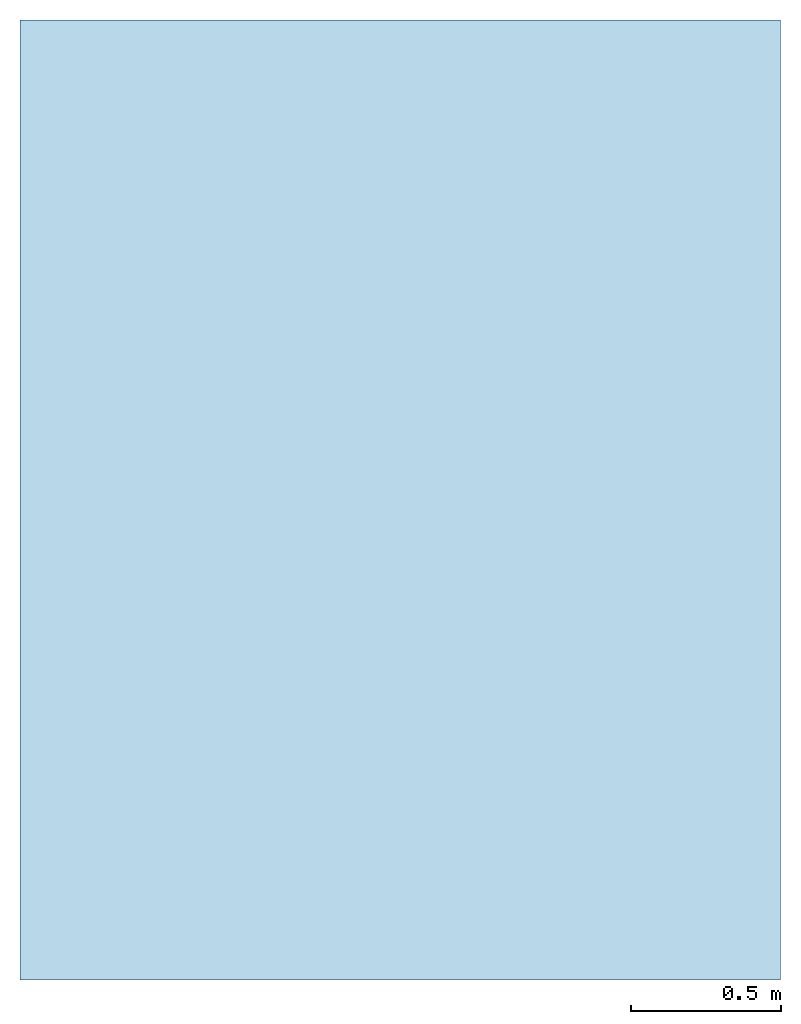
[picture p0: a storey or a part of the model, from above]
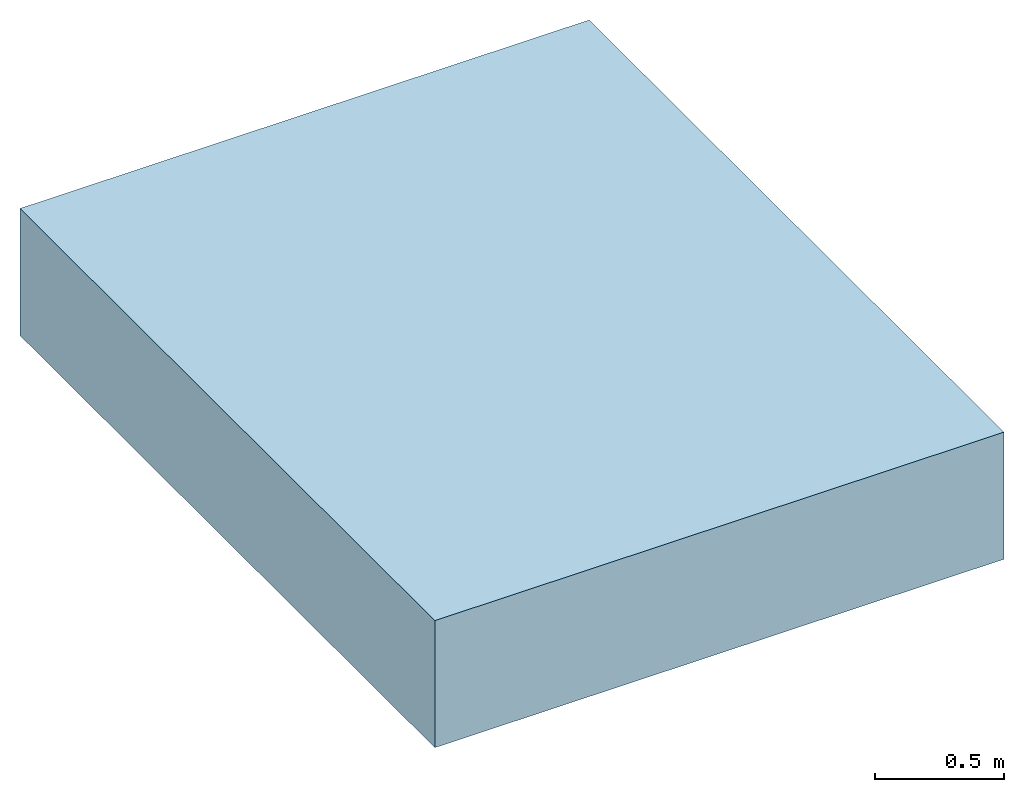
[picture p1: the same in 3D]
Properties of the parts of a building model (IFC2X3), part 1 of 4

# File
Description: ViewDefinition [CoordinationView_V2.0, SpaceBoundary2ndLevelAddOnView], Option [Drawing Scale: 100.000000], Option [Elements to export: Visible elements (on all stories)], Option [Partial Structure Display: Entire Model], Option [IFC Domain: All], Option [Structural Function: All Elements], Option [Convert Grid elements: On], Option [Convert IFC Annotations and ARCHICAD 2D elements: Off], Option [Convert 2D symbols of Doors and Windows: Off], Option [Export geometries that Participates in Collision Detection only: Off], Option [Split complex elements: On], Option [IFC Domain For Space Containment: Custom], Option [Elements in Solid Element Operations: Extruded/revolved], Option [Elements with junctions: Extruded/revolved without junctions], Option [Slabs with slanted edge(s): Extruded], Option [IFC Site Location: At Project Origin], Option [Curtain Wall export mode: Container Element], Option [Railing export mode: Container Element], Option [Stair export mode: Container Element], Option [Properties To Export: All properties], Option [Space containment: Off], Option [Bounding Box: Off], Option [Geometry to type objects: Off], Option [Element Properties: Visible Only], Option [Building Material Properties: Off], Option [Element Parameters: Off], Option [Component Parameters: Off], Option [IFC Base Quantities: Off], Option [Door Window Parameters: On], Option [IFC Space boundaries: On], Option [ARCHICAD Zone Categories as IFC Space classification data: Off], Option [Element Classifications: On]
File name: D:\Dropbox\01-L0121 Haapsalu, Paide ja Viljandi komandode ning Elva ühishoone projekteerimine\Elva ühishoone\08_KOONDMUDEL\01_IFC\AR_KUU90121E.ifc
Time: 2021-09-15T11:04:50
Author: Rohtla Juhan
Organization: Building Designer Office
Written by: The EXPRESS Data Manager Version 5.02.0100.09 : 26 Sep 2013
Made in: IFC file generated by GRAPHISOFT ARCHICAD 24.0.0 INT FULL Windows version (IFC add-on version: 3008 INT FULL).
Authorization: Rohtla Juhan

# IfcProject, ELVA ÜHISHOONE
Phase: PÕHIPROJEKT

# IfcSite, KIRDE 14, ELVA
Description: Kinnistu Kirjeldus; RefLatitude: 0, 0, 0, 0; RefLongitude: 0, 0, 0, 0; RefElevation: 0 mm; Classification: 1.0.1 IfcSite (kinnistu) (RKAS BIM + ARCHICAD Classification 24 + v 2.0)
AR_Kinnistu - 025_Max_kõrgus: 0 mm; 010_Katastritunnus: 17002:001:0035; 020_Pindala: 5119 m2; 015_Ehitatav_pindala: 1702.4 m2

# IfcBuilding, PPA ja Päästeameti ühishoone
Classification: 1.0.2 IfcBuilding (hoone) (RKAS BIM + ARCHICAD Classification 24 + v 2.0)
AR_Hoone - 035_Sprinkler: no; 040_Kõrgus: 0 mm; ?: 0 m2; 050_Neto_pindala: 0 m2; 055_Neto_ruumala: 0 m3; 001_Nimetus: PPA ja Päästreameti ühishoone; 030_Hoone_aadress: Kirde 14, Elva

# IfcBuildingStorey (5)
In: PPA ja Päästeameti ühishoone
Name | Elevation (mm)
Vundament | -1700
Esimene korrus | 0 | AR_Korrus - 060_Korruse_nimi: ESIMENE KORRUS; 065_Korruse_number: 1; 070_Maapealne: yes
Teine korrus | 3600 | AR_Korrus - 060_Korruse_nimi: TEINE KORRUS; 065_Korruse_number: 2; 070_Maapealne: yes
Katusekorrus | 7700
4. Story | 10700

# IfcSpace: 01_PPA (8)
InteriorOrExteriorSpace: INTERNAL; Classification: 1.21 IfcSpaceType (ruum) (RKAS BIM + ARCHICAD Classification)
Pset_SpaceCommon - Reference: Korruse avatud netopind; Category: 01_PPA
AR_Ruum - 115_Kategooria: 01_PPA; 110_Tüüp: Korruse avatud netopind
AC_Pset_RenovationAndPhasing - Renovation Status: Existing
Name | In | LongName = 100_Nimi | 105_Number | 120_Pindala (m2) | 125_Turvatsoon
007 | Esimene korrus | HOIURUUM | 007 | 66.6548 | PUNANE
008 | Esimene korrus | MAJAHOIDJA | 008 | 5.09534 | KOLLANE
105 | Esimene korrus | MENETLEJA | 105 | 7.96744 | SININE
106 | Esimene korrus | VESTLUSE RUUM | 106 | 8.04117 | SININE
108 | Esimene korrus | VARUSTUS | 108 | 4.1919 | PUNANE
107 | Esimene korrus | PIIRKONNA-KONSTAABLID | 107 | 26.3789 | SININE
222 | Teine korrus | PUHKERUUM+KÖÖK | 222 | 16.3328 | SININE
223 | Teine korrus | PATRULL-TEENISTUS | 223 | 20.7221 | SININE

# IfcSpace: 02_PUHAS TSOON PÄÄSTE (8)
In: Teine korrus
InteriorOrExteriorSpace: INTERNAL; Classification: 1.21 IfcSpaceType (ruum) (RKAS BIM + ARCHICAD Classification)
Pset_SpaceCommon - Reference: Korruse avatud netopind; Category: 02_PUHAS TSOON PÄÄSTE
AR_Ruum - 115_Kategooria: 02_PUHAS TSOON PÄÄSTE; 110_Tüüp: Korruse avatud netopind
AC_Pset_RenovationAndPhasing - Renovation Status: Existing
Name | LongName = 100_Nimi | 105_Number | 120_Pindala (m2) | 125_Turvatsoon
209 | WC | 209 | 1.18576 | RC3
207 | MEESKONNAVANEM | 207 | 11.2528 | ORANZ
208 | KOMANDOPEALIK | 208 | 14.178 | ORANZ
203 | PUHKETUBA | 203 | 9.59625 | ORANZ
202 | MEESKONNARUUM/KÖÖK | 202 | 64.1894 | ORANZ
204 | PUHKETUBA | 204 | 9.6 | ORANZ
205 | PUHKETUBA | 205 | 9.60045 | ORANZ
206 | PUHKETUBA | 206 | 11.0531 | ORANZ

# IfcSpace: 03_MUST TSOON PÄÄSTE (19)
In: Esimene korrus
InteriorOrExteriorSpace: INTERNAL; Classification: 1.21 IfcSpaceType (ruum) (RKAS BIM + ARCHICAD Classification)
Pset_SpaceCommon - Reference: Korruse avatud netopind; Category: 03_MUST TSOON PÄÄSTE
AR_Ruum - 115_Kategooria: 03_MUST TSOON PÄÄSTE
Name | LongName = 100_Nimi | 105_Number | 110_Tüüp | 120_Pindala (m2) | 125_Turvatsoon | Renovation Status
002 | VOOLIKUKUIVATUSTORN | 002 | Korruse avatud netopind | 8.11685 | ORANZ | New
121 | PR. HOOLDUS, HOIURUUM | 121 | Korruse avatud netopind | 42.4983 | ORANZ | Existing
004 | WC | 001 | Korruse avatud netopind | 1.7729 | ORANZ | New
119 | PUHAS LADU | 119 | Korruse avatud netopind | 23.362 | ORANZ | Existing
115 | ATV | 115 | Korruse avatud netopind | 46.0365 | ORANZ | Existing
114 | PESUBOKS | 114 | Korruse avatud netopind | 80.6371 | KOLLANE | Existing
11 | GARAAZ | 11 | Netopind | 318.751 | ORANZ | Existing
123 | TEHNIKAHOOLDUS | 123 | Korruse avatud netopind | 23.0162 | ORANZ | Existing
122 | HA. HOOLDUS | 122 | Korruse avatud netopind | 24.1263 | ORANZ | New
126 | PESURUUM/RIIETUS | 126 | Korruse avatud netopind | 14.4788 | ORANZ | Existing
116 | KORIDOR | 116 | Korruse avatud netopind | 8.95355 | KOLLANE | Existing
118 | PP.SEADE | 118 | Korruse avatud netopind | 1.87235 | KOLLANE | Existing
120 | MUST LADU | 120 | Korruse avatud netopind | 30.0442 | ORANZ | Existing
124 | KORISTUS | 124 | Korruse avatud netopind | 4.7031 | ORANZ | Existing
001 | VOOLIKUHOOLDUS | 001 | Korruse avatud netopind | 110.996 | ORANZ | New
117 | KORIDOR | 117 | Korruse avatud netopind | 2.50484 | ORANZ | New
005 | TÖÖRUUM | 005 | Korruse avatud netopind | 5.08268 | ORANZ | New
125 | WC | 125 | Korruse avatud netopind | 2.18599 | ORANZ | New
002 | VOOLIKULADU | 002 | Korruse avatud netopind | 28.539 | ORANZ | New

# IfcSpace: 04_TREPIKODA, KORIDORID, ÜLDRUUMID (9)
InteriorOrExteriorSpace: INTERNAL; Classification: 1.21 IfcSpaceType (ruum) (RKAS BIM + ARCHICAD Classification)
Pset_SpaceCommon - Category: 04_TREPIKODA, KORIDORID, ÜLDRUUMID
AR_Ruum - 115_Kategooria: 04_TREPIKODA, KORIDORID, ÜLDRUUMID
Name | In | LongName = 100_Nimi | Reference = 110_Tüüp | 105_Number | 120_Pindala (m2) | 125_Turvatsoon | Renovation Status
101 | Esimene korrus | FUAJEE, OOTERUUM | Korruse avatud netopind | 101 | 26.0202 | ROHELINE | Existing
103 | Esimene korrus | KORIDOR | Korruse avatud netopind | 103 | 12.2053 | RC3 | Existing
111 | Esimene korrus | KORIDOR | Vertikaalsete ühendusteede pind | 111 | 13.0543 | KOLLANE | Existing
100 | Esimene korrus | TK | Korruse avatud netopind | 100 | 3.10667 | ROHELINE | New
211 | Teine korrus | WC | Korruse avatud netopind | 211 | 1.40685 | KOLLANE | Existing
200 | Teine korrus | KORIDOR | Korruse avatud netopind | 200 | 47.0969 | KOLLANE | Existing
210 | Teine korrus | WC | Korruse avatud netopind | 210 | 1.40685 | KOLLANE | Existing
221 | Teine korrus | TREPIKODA | Vertikaalsete ühendusteede pind | 221 | 11.287 | KOLLANE | Existing
201 | Teine korrus | KORIDOR | Korruse avatud netopind | 200 | 3.16427 | KOLLANE | New

# IfcSpace: 04_ÜLDRUUMID (11)
InteriorOrExteriorSpace: INTERNAL; Classification: 1.21 IfcSpaceType (ruum) (RKAS BIM + ARCHICAD Classification)
Pset_SpaceCommon - Reference: Korruse avatud netopind; Category: 04_ÜLDRUUMID
AR_Ruum - 115_Kategooria: 04_ÜLDRUUMID; 110_Tüüp: Korruse avatud netopind
AC_Pset_RenovationAndPhasing - Renovation Status: Existing
Name | In | LongName = 100_Nimi | 105_Number | 120_Pindala (m2) | 125_Turvatsoon
104 | Esimene korrus | WC INVA | 104 | 6.46205 | ROHELINE
102 | Esimene korrus | ÕPPEKLASS | 102 | 64.6726 | KOLLANE
127 | Esimene korrus | TREPIKODA | 127 | 2.38765 | KOLLANE
218 | Teine korrus | WC | 218 | 1.62997 | KOLLANE
213 | Teine korrus | LEILIRUUM | 213 | 3.13597 | KOLLANE
212 | Teine korrus | RIIETUSRUUM | 212 | 57.9283 | KOLLANE
214 | Teine korrus | PESURUUM | 214 | 3.80744 | KOLLANE
215 | Teine korrus | WC | 215 | 1.90537 | KOLLANE
217 | Teine korrus | LEILIRUUM | 217 | 3.98084 | KOLLANE
216 | Teine korrus | PESURUUM | 216 | 6.3415 | KOLLANE
220 | Teine korrus | JÕUSAAL | 220 | 43.3762 | KOLLANE

# IfcSpace: 05_TEHNILISED RUUMID (8)
InteriorOrExteriorSpace: INTERNAL; Classification: 1.21 IfcSpaceType (ruum) (RKAS BIM + ARCHICAD Classification)
Pset_SpaceCommon - Category: 05_TEHNILISED RUUMID
AR_Ruum - 115_Kategooria: 05_TEHNILISED RUUMID
Name | In | LongName = 100_Nimi | Reference = 110_Tüüp | 105_Number | 120_Pindala (m2) | 125_Turvatsoon | Renovation Status
006 | Esimene korrus | GENERAATOR | Tehnopind | 006 | 16.381 | PUNANE | Existing
109 | Esimene korrus | SOOJASÕLM | Korruse avatud netopind | 109 | 5.34399 | KOLLANE | Existing
110 | Esimene korrus | KILBIRUUM | Tehnopind | 110 | 7.0841 | PUNANE | Existing
112 | Esimene korrus | KORISTUS | Korruse avatud netopind | 112 | 3.38859 | KOLLANE | Existing
224 | Teine korrus | VENTILATSIOON/KOMPRESSOR | Tehnopind | 224 | 51.1828 | KOLLANE | Existing
226 | Teine korrus | ÕVK | Tehnopind | 226 | 5.97177 | KOLLANE | Existing
226 | Teine korrus | KORISTAJA | Korruse avatud netopind | 226 | 3.3136 | KOLLANE | Existing
227 | Teine korrus | SERVER | Korruse avatud netopind | 227 | 4.10956 | PUNANE | New

# IfcSpace: 08_GARAAZ, 009
In: Esimene korrus
Type - ElementType: EXTERNAL; PredefinedType: USERDEFINED
LongName: KONTEINERITE VARJUALUNE; InteriorOrExteriorSpace: INTERNAL; Classification: External Space (RKAS BIM + ARCHICAD Classification)
Pset_SpaceCommon - Reference: Korruse avatud netopind; Category: 08_GARAAZ
AR_Ruum - 100_Nimi: KONTEINERITE VARJUALUNE; 105_Number: 009; 115_Kategooria: 08_GARAAZ; 110_Tüüp: Korruse avatud netopind; 120_Pindala: 226.204 m2; 125_Turvatsoon: ORANZ
AC_Pset_RenovationAndPhasing - Renovation Status: Existing

# IfcBeam: GENERIC - STRUCTURAL 100 x 60, LIIMPUITPRUSS
In: Esimene korrus
Type - PredefinedType: BEAM
Classification: 1.01 IfcBeamType (tala) (RKAS BIM + ARCHICAD Classification); Material: GENERIC - STRUCTURAL
Pset_BeamCommon - Reference: GENERIC - STRUCTURAL; Span: 12511 mm; Slope: 0 deg
AR_001-002 - 001_Nimetus: LIIMPUITPRUSS; 002_Tüüp: GENERIC - STRUCTURAL
AC_Pset_RenovationAndPhasing - Renovation Status: Existing

# IfcBeam: GENERIC - STRUCTURAL 160 x 50, LIIMPUITPRUSS
In: Esimene korrus
Type - PredefinedType: BEAM
Classification: 1.01 IfcBeamType (tala) (RKAS BIM + ARCHICAD Classification); Material: GENERIC - STRUCTURAL
Pset_BeamCommon - Reference: GENERIC - STRUCTURAL; Span: 1250 mm; Slope: 0 deg
AR_001-002 - 001_Nimetus: LIIMPUITPRUSS; 002_Tüüp: GENERIC - STRUCTURAL
AC_Pset_RenovationAndPhasing - Renovation Status: Existing

# IfcBeam: GENERIC - STRUCTURAL 160 x 60 (2)
In: Esimene korrus
Type - PredefinedType: BEAM
Classification: 1.01 IfcBeamType (tala) (RKAS BIM + ARCHICAD Classification); Material: GENERIC - STRUCTURAL
Pset_BeamCommon - Reference: GENERIC - STRUCTURAL; Slope: 0 deg
AR_001-002 - 001_Nimetus: LIIMPUITPRUSS; 002_Tüüp: GENERIC - STRUCTURAL
AC_Pset_RenovationAndPhasing - Renovation Status: Existing
Name | Span (mm)
LIIMPUITPRUSS | 12511
LIIMPUITPRUSS | 11211

# IfcBuildingElementPart (298)
Name | In | Material
34 x Vahtpolüstüreen (4) | Vundament | Vahtpolüstüreen (4)
10 x Concrete - Cast-in-Place Concrete - C12/15 | Vundament | Concrete - Cast-in-Place Concrete - C12/15
10 x Mineraalvill | Vundament | Mineraalvill
18 x Concrete, Cast In Situ | Vundament | Concrete, Cast In Situ
10 x Timber - Floor | Vundament | Timber - Floor
3 x Laudis | Esimene korrus | Laudis
2 x Tuulutusvahe (2) | Esimene korrus | Tuulutusvahe (2)
2 x ET-00_GENEERILINE - EHITUSTOODE | Esimene korrus | ET-00_GENEERILINE - EHITUSTOODE
2 x Profiilplekk | Esimene korrus | Profiilplekk
13 x Vahtpolüstüreen (4) | Esimene korrus | Vahtpolüstüreen (4)
2 x SBS Rullmaterjal | Esimene korrus | SBS Rullmaterjal
36 x Krohv | Esimene korrus | Krohv
13 x COLUMBIA KIVI | Esimene korrus | COLUMBIA KIVI
8 x Mineraalvill | Esimene korrus | Mineraalvill
7 x COLUMBIA KIVI (BETONEERITUD) | Esimene korrus | COLUMBIA KIVI (BETONEERITUD)
Kruus | Esimene korrus | Kruus
Liiv (2) | Esimene korrus | Liiv (2)
Betoonkivi | Esimene korrus | Betoonkivi
2 x Concrete - Cast-in-Place Concrete - C12/15 | Esimene korrus | Concrete - Cast-in-Place Concrete - C12/15
3 x Concrete, Cast In Situ | Esimene korrus | Concrete, Cast In Situ
3 x Timber - Floor | Esimene korrus | Timber - Floor
2 x  | Esimene korrus
2 x Fire Proofing | Esimene korrus | Fire Proofing
18 x Raudbetoon Paneelid (2) | Esimene korrus | Raudbetoon Paneelid (2)
Air Space | Esimene korrus | Air Space
Raudbetoon Paneelid | Esimene korrus | Raudbetoon Paneelid
7 x Laudis | Teine korrus | Laudis
Tuulutusvahe (2) | Teine korrus | Tuulutusvahe (2)
ET-00_GENEERILINE - EHITUSTOODE | Teine korrus | ET-00_GENEERILINE - EHITUSTOODE
Profiilplekk | Teine korrus | Profiilplekk
10 x Vahtpolüstüreen (4) | Teine korrus | Vahtpolüstüreen (4)
SBS Rullmaterjal | Teine korrus | SBS Rullmaterjal
5 x  | Teine korrus
5 x Fire Proofing | Teine korrus | Fire Proofing
6 x COLUMBIA KIVI (BETONEERITUD) | Teine korrus | COLUMBIA KIVI (BETONEERITUD)
18 x Air Space | Teine korrus | Air Space
18 x Raudbetoon Paneelid (2) | Teine korrus | Raudbetoon Paneelid (2)
Raudbetoon Paneelid | Teine korrus | Raudbetoon Paneelid
Mineraalvill | Teine korrus | Mineraalvill
Concrete, Cast In Situ | Teine korrus | Concrete, Cast In Situ
Timber - Floor | Teine korrus | Timber - Floor
8 x Krohv | Teine korrus | Krohv
4 x COLUMBIA KIVI | Teine korrus | COLUMBIA KIVI
2 x KON-00_GENEERILINE - KONSTRUKTSIOON | Teine korrus | KON-00_GENEERILINE - KONSTRUKTSIOON
2 x SV-00_GENEERILINE - SISEMINE VOODER | Teine korrus | SV-00_GENEERILINE - SISEMINE VOODER

# IfcBuildingElementProxy: A-SS01 260, VS-06
In: Esimene korrus
Classification: RKAS (RKAS BIM + ARCHICAD Classification)
AC_Pset_RenovationAndPhasing - Renovation Status: New

# IfcBuildingElementProxy: A-VS02 250, VS-06
In: Esimene korrus
Classification: RKAS (RKAS BIM + ARCHICAD Classification)
AC_Pset_RenovationAndPhasing - Renovation Status: New

# IfcColumn: Concrete - Structural 1300 x 400, RB post
In: Esimene korrus
Type - PredefinedType: COLUMN
Classification: 1.03 IfcColumnType (post) (RKAS BIM + ARCHICAD Classification); Material: Concrete - Structural
Pset_ColumnCommon - Slope: 0 deg; LoadBearing: yes; IsExternal: no
AR_001-002 - 001_Nimetus: RB post; 002_Tüüp: Concrete - Structural
AC_Pset_RenovationAndPhasing - Renovation Status: Existing

# IfcColumn: Concrete - Structural 1425 x 400, M_Concrete-Rectangular-Column:400 x 400mm:1416487
In: Esimene korrus
Type - PredefinedType: COLUMN
Classification: 1.03 IfcColumnType (post) (RKAS BIM + ARCHICAD Classification); Material: Concrete - Structural
Pset_ColumnCommon - Slope: 0 deg; Reference: 400 x 400mm; LoadBearing: yes; IsExternal: no
AR_001-002 - 001_Nimetus: RB post; 002_Tüüp: Concrete - Structural
AC_Pset_RenovationAndPhasing - Renovation Status: Existing

# IfcColumn: Concrete - Structural 1535 x 400, RB post
In: Esimene korrus
Type - PredefinedType: COLUMN
Classification: 1.03 IfcColumnType (post) (RKAS BIM + ARCHICAD Classification); Material: Concrete - Structural
Pset_ColumnCommon - Slope: 0 deg; LoadBearing: yes; IsExternal: no
AR_001-002 - 001_Nimetus: RB post; 002_Tüüp: Concrete - Structural
AC_Pset_RenovationAndPhasing - Renovation Status: Existing

# IfcColumn: Concrete - Structural 450 x 400 (4)
In: Esimene korrus
Type - PredefinedType: COLUMN
Classification: 1.03 IfcColumnType (post) (RKAS BIM + ARCHICAD Classification); Material: Concrete - Structural
Pset_ColumnCommon - Slope: 0 deg; LoadBearing: yes; IsExternal: no
AR_001-002 - 001_Nimetus: RB post; 002_Tüüp: Concrete - Structural
AC_Pset_RenovationAndPhasing - Renovation Status: Existing

# IfcColumn: GENERIC - STRUCTURAL 120 x 120 (2)
In: Teine korrus
Type - PredefinedType: COLUMN
Classification: 1.03 IfcColumnType (post) (RKAS BIM + ARCHICAD Classification); Material: GENERIC - STRUCTURAL
Pset_ColumnCommon - Slope: 90 deg
AR_001-002 - 001_Nimetus: TERASPOST; 002_Tüüp: GENERIC - STRUCTURAL
AC_Pset_RenovationAndPhasing - Renovation Status: New

# IfcColumn: GENERIC - STRUCTURAL 50 x 160 (19)
In: Esimene korrus
Type - PredefinedType: COLUMN
Classification: 1.03 IfcColumnType (post) (RKAS BIM + ARCHICAD Classification); Material: GENERIC - STRUCTURAL
Pset_ColumnCommon - Slope: 90 deg
AR_001-002 - 001_Nimetus: LIIMPUITPOST; 002_Tüüp: GENERIC - STRUCTURAL
AC_Pset_RenovationAndPhasing - Renovation Status: Existing

# IfcColumn: GENERIC - STRUCTURAL D140 (2)
In: Teine korrus
Type - PredefinedType: COLUMN
Classification: 1.03 IfcColumnType (post) (RKAS BIM + ARCHICAD Classification); Material: GENERIC - STRUCTURAL
Pset_ColumnCommon - Slope: 90 deg
AR_001-002 - 001_Nimetus: TORULIFT; 002_Tüüp: GENERIC - STRUCTURAL
AC_Pset_RenovationAndPhasing - Renovation Status: Existing

# IfcColumn: SBS Rullmaterjal D100 (16)
In: Esimene korrus
Type - PredefinedType: COLUMN
Classification: 1.03 IfcColumnType (post) (RKAS BIM + ARCHICAD Classification); Material: SBS Rullmaterjal
Pset_ColumnCommon - Slope: 0 deg; LoadBearing: yes; IsExternal: no
AR_001-002 - 001_Nimetus: RB post; 002_Tüüp: SBS Rullmaterjal
AC_Pset_RenovationAndPhasing - Renovation Status: New

# IfcCovering: IfcCovering (40)
In: Esimene korrus
Type - PredefinedType: FLOORING
Classification: 1.06 IfcCoveringType.FLOORING (põrandakatted) (RKAS BIM + ARCHICAD Classification); Material: SV-02_Puit - Põrand
Pset_CoveringCommon - TotalThickness: 5 mm
AR_Ripplagi_Viimistlus_Põrandakate - 215_Tulekindlusklass: Undefined; 220_Viimistlus: Undefined; 230_Niiskuskindel: no; 900_Tootja: Undefined; 905_Mudel: Undefined; 910_Tooteinfo: Undefined; 915_Kasutus-ja_hooldusjuhend: Undefined; 245_Aluspind: Undefined; 200_Materjal (MUDELIS): SV-02_Puit - Põrand
AC_Pset_RenovationAndPhasing - Renovation Status: New
Name | Reference = 205_Tüüp | AR_Ripplagi_Viimistlus_Põrandakate, 001_Nimetus = AR_001-002, 001_Nimetus | 210_Paksus (mm)
TV TÕUS - 001 | Riser | TV TÕUS - 001 | 1200
TV TÕUS - 002 | Riser | TV TÕUS - 002 | 1200
TV TÕUS - 003 | Riser | TV TÕUS - 003 | 1200
TV TÕUS - 004 | Riser | TV TÕUS - 004 | 1200
TV TÕUS - 005 | Riser | TV TÕUS - 005 | 1200
TV TÕUS - 006 | Riser | TV TÕUS - 006 | 1200
TV TÕUS - 007 | Riser | TV TÕUS - 007 | 1200
TV TÕUS - 008 | Riser | TV TÕUS - 008 | 1200
TV TÕUS - 009 | Riser | TV TÕUS - 009 | 1200
TV TÕUS - 010 | Riser | TV TÕUS - 010 | 1200
TV TÕUS - 011 | Riser | TV TÕUS - 011 | 1200
TV TÕUS - 012 | Riser | TV TÕUS - 012 | 1200
TV TÕUS - 013 | Riser | TV TÕUS - 013 | 1200
TV TÕUS - 014 | Riser | TV TÕUS - 014 | 1200
TV TÕUS - 015 | Riser | TV TÕUS - 015 | 1200
TV TÕUS - 016 | Riser | TV TÕUS - 016 | 1200
TV TÕUS - 017 | Riser | TV TÕUS - 017 | 1200
TV TÕUS - 018 | Riser | TV TÕUS - 018 | 1200
TV TÕUS - 019 | Riser | TV TÕUS - 019 | 1200
TV TÕUS - 020 | Riser | TV TÕUS - 020 | 1200
TV ASTE - 001 | Tread | TV ASTE - 001 | 5
TV ASTE - 002 | Tread | TV ASTE - 002 | 5
TV ASTE - 003 | Tread | TV ASTE - 003 | 5
TV ASTE - 004 | Tread | TV ASTE - 004 | 5
TV ASTE - 005 | Tread | TV ASTE - 005 | 5
TV ASTE - 006 | Tread | TV ASTE - 006 | 5
TV ASTE - 007 | Tread | TV ASTE - 007 | 5
TV ASTE - 008 | Tread | TV ASTE - 008 | 5
TV ASTE - 009 | Tread | TV ASTE - 009 | 5
TV ASTE - 010 | Tread | TV ASTE - 010 | 5
TV ASTE - 011 | Tread | TV ASTE - 011 | 5
TV ASTE - 012 | Tread | TV ASTE - 012 | 5
TV ASTE - 013 | Tread | TV ASTE - 013 | 5
TV ASTE - 014 | Tread | TV ASTE - 014 | 5
TV ASTE - 015 | Tread | TV ASTE - 015 | 5
TV ASTE - 016 | Tread | TV ASTE - 016 | 5
TV ASTE - 017 | Tread | TV ASTE - 017 | 5
TV ASTE - 018 | Tread | TV ASTE - 018 | 5
TV ASTE - 019 | Tread | TV ASTE - 019 | 5
TV ASTE - 020 | Tread | TV ASTE - 020 | 5

# IfcCovering: Titanium Zinc 100 (3)
In: Katusekorrus
Type - PredefinedType: CLADDING
Classification: 1.05 IfcCoveringType.CLADDING (viimistlus) (RKAS BIM + ARCHICAD Classification); Material: Titanium Zinc
Pset_CoveringCommon - Reference: Titanium Zinc; Material: Titanium Zinc; TotalThickness: 100 mm
AR_Ripplagi_Viimistlus_Põrandakate - 001_Nimetus: PARAPETIPLEKK; 200_Materjal: Titanium Zinc; 205_Tüüp: Titanium Zinc; 210_Paksus: 100 mm; 215_Tulekindlusklass: Undefined; 220_Viimistlus: Undefined; 230_Niiskuskindel: no; 900_Tootja: Undefined; 905_Mudel: Undefined; 910_Tooteinfo: Undefined; 915_Kasutus-ja_hooldusjuhend: Undefined; 240_Märghõõrdekindlus: Undefined; 245_Aluspind: Undefined; 200_Materjal (MUDELIS): Titanium Zinc
AR_001-002 - 001_Nimetus: PARAPETIPLEKK
AC_Pset_RenovationAndPhasing - Renovation Status: New
Name | 225_Pindala (m2)
PARAPETIPLEKK | 924.22
PARAPETIPLEKK | 10.4419
PARAPETIPLEKK | 247.46

# IfcDiscreteAccessory: Model Element 36 (7)
In: Katusekorrus
Description: Sewer component; Classification: 1.09 IfcDiscreteAccessoryType (tarvik) (RKAS BIM + ARCHICAD Classification); Material: IFC Building Material
AR_001-002 - 001_Nimetus: Katusetuulutus; 002_Tüüp: Model Element 36
Pset_QuantityTakeOff - Reference: Model Element 36
AC_Pset_RenovationAndPhasing - Renovation Status: Existing

# IfcDiscreteAccessory: Solar Collector Flat Plate 24 (135)
In: Katusekorrus
Description: Other pipe device; Classification: 1.09 IfcDiscreteAccessoryType (tarvik) (RKAS BIM + ARCHICAD Classification); Not defined (NS3420)
MagiCAD Pset_PipeDevice - PartType: Other pipe device; User Code: SPLIT3; RunningIndex: -; Status: Not defined; ProductCode: SPLIT3 "Panasonic WH-UX-09-DE8-1"; Manufacturer: Kaukomarkkinat; qv_SizingFlow_ls: 0.954; P_Heating_W: 12000; Storey: 3. KATUS
AR_001-002 - 001_Nimetus: Päikesepaneel; 002_Tüüp: Solar Collector Flat Plate
Pset_QuantityTakeOff - Reference: Solar Collector Flat Plate
AC_Pset_RenovationAndPhasing - Renovation Status: Existing

# IfcDiscreteAccessory: Text 3D 24 (2)
In: Teine korrus
Classification: 1.09 IfcDiscreteAccessoryType (tarvik) (RKAS BIM + ARCHICAD Classification)
Avatäited - 01 Nimetus: Katuseluuk
AR_001-002 - 001_Nimetus: HOONE SILT; 002_Tüüp: Text 3D
Pset_QuantityTakeOff - Reference: Text 3D
AC_Pset_RenovationAndPhasing - Renovation Status: Existing

# IfcDoor: Door 24, SU-06
In: Esimene korrus
Type - OperationType: SINGLE_SWING_LEFT; ParameterTakesPrecedence: no; Sizeable: no
Type - Door Lining Properties - LiningDepth: 115 mm; LiningThickness: 40 mm; LiningOffset: 190 mm
Type - Door Panel Properties - Panel 1 - PanelDepth: 40 mm; PanelOperation: SWINGING; PanelWidth: 1; PanelPosition: MIDDLE
OverallHeight: 2300 mm; OverallWidth: 900 mm; Classification: 1.10 IfcDoorStyle (uks) (RKAS BIM + ARCHICAD Classification); 522 Alumiiniumuksed (V1- EHITUSKULUDE LIIGITAMINE EVS 885:2005)
Avatäited - 10 Tulekindlus: EI-30
AR_Uks - 310_Materjal: ALUMIINIUM; 375_Viimistlus_seest: LENG JA RAAMID: PULBERVÄRVITUD, TOON: HALL, RAL 7045; 376_Viimistlus_väljast: LENG JA RAAMID: PULBERVÄRVITUD, TOON: HALL, RAL 7045; 001_Nimetus: SISEUKS; 300_Tüüp: SU-06; 305_Ava_mõõt: 900x2 300; 315_Avanemine: PAREMAKÄELINE ; ARCHICAD tüüp: Side Hung; 320_Klaas: ÜHEKORDNE KLAASPAKETT; 325_Helipidavus: UKSE HELIPIDAVUS 38 dB/ PAKETI HELIPIDAVUS 30 dB; 330_Tulekindlus: EI30; 335_Välispiire: no; 340_Soojusläbivus: 0; 345_Päikesekiirgus_tegur: Undefined; 350_Klaaspakett: KARASTATUD, LAMINEERITUD; 355_Pindala: 2.07 m2; 360_Ratastooliga: no; 365_Isesulguv: no; 370_Evakuatsiooniväljapääs: no; 380_Lukustus: UKS VARUSTADA SOLENOIDMOOTORLUKUGA (VT. NÕRKVOOLU PROJEKTI). SEESTPOOLT LIBLIKLUKUSTUSEGA, VÄLJASPOOLT VÕTMEGA LUKUSTATAV. KÄEPIDE ON ASSA RUKO-LINE, HARJATUD, ROOSTEVABA. HINGED VASTAVALT TOOTJALE. UKSESULGURINA KASUTADA UKSE VÕI LENGI SISSE SÜVISTATAVAT MUDELIT.; 900_Tootja: SCHÜCO; 905_Mudel: ADS 80 FR 30; 910_Tooteinfo: LÄHTUDA TOOTJAFIRMA INFOLEHELT; 915_Kasutus-ja_hooldusjuhend: LÄHTUDA TOOTJAFIRMA INFOLEHELT
Pset_DoorCommon - Reference: SU-06; ThermalTransmittance: 0; GlazingAreaFraction: 1.33437
AC_Pset_RenovationAndPhasing - Renovation Status: New

# IfcDoor: Door 24, SU-15
In: Esimene korrus
Type - OperationType: SINGLE_SWING_LEFT; ParameterTakesPrecedence: no; Sizeable: no
Type - Door Lining Properties - LiningThickness: 40 mm; ThresholdDepth: 100 mm; ThresholdThickness: 12 mm; LiningOffset: 0 mm; ThresholdOffset: 0 mm
Type - Door Panel Properties - Panel 1 - PanelDepth: 40 mm; PanelOperation: SWINGING; PanelWidth: 1; PanelPosition: MIDDLE
OverallHeight: 2300 mm; OverallWidth: 900 mm; Classification: 1.10 IfcDoorStyle (uks) (RKAS BIM + ARCHICAD Classification); 523 Terasuksed (V1- EHITUSKULUDE LIIGITAMINE EVS 885:2005)
Pset_ManufacturerTypeInformation - Manufacturer: SAKU METALL
AR_Uks - 310_Materjal: TERAS; 376_Viimistlus_väljast: LENG: HALL, RAL 7045, UKSELEHT: HALL, RAL 7045; 375_Viimistlus_seest: LENG: HALL, RAL 7045, UKSELEHT: HALL, RAL 7045; 001_Nimetus: SISEUKS; 300_Tüüp: SU-15; 305_Ava_mõõt: 900x2 300; 315_Avanemine: PAREMKÄE UKS ; ARCHICAD tüüp: Side Hung; 320_Klaas: -; 325_Helipidavus: -; 330_Tulekindlus: nõudeid ei esitata; 335_Välispiire: no; 340_Soojusläbivus: 0; 345_Päikesekiirgus_tegur: -; 350_Klaaspakett: -; 355_Pindala: 2.07 m2; 360_Ratastooliga: no; 365_Isesulguv: no; 370_Evakuatsiooniväljapääs: no; 380_Lukustus: SISSEPOOLE, SAN. RUUMI LIBLIKLUKUSTUS. VÄLJASPOOLT LUKUSTATAV, LUKUSTUSE ASENDI NÄITAJA. KÄEPIDE ASSA RUKOLINE, L-KUJULINE ÜMARATE KATETEGA LINK, HARJATUD, ROOSTEVABA, OTS TAGASIPÖÖRDEGA. HINGED VASTAVALT TOOTJALE.; 900_Tootja: SAKU METALL; 905_Mudel: -; 910_Tooteinfo: UKSESISENE VENTILATSIOONIREST (400x200 MM, TOON: HALL, RAL 7045). LÄHTUDA TOOTJAFIRMA INFOLEHEST; 915_Kasutus-ja_hooldusjuhend: LÄHTUDA TOOTJAFIRMA INFOLEHEST
Pset_DoorCommon - Reference: SU-15; ThermalTransmittance: 0
AC_Pset_RenovationAndPhasing - Renovation Status: New

# IfcDoor: Door 24 (2)
Type - OperationType: SINGLE_SWING_LEFT; ParameterTakesPrecedence: no; Sizeable: no
Type - Door Lining Properties - LiningThickness: 40 mm; ThresholdDepth: 100 mm; ThresholdThickness: 12 mm; LiningOffset: 0 mm; ThresholdOffset: 40 mm
Type - Door Panel Properties - Panel 1 - PanelDepth: 40 mm; PanelOperation: SWINGING; PanelWidth: 1; PanelPosition: MIDDLE
AR_Uks - 320_Klaas: -; 325_Helipidavus: -; 335_Välispiire: no; 340_Soojusläbivus: 0; 345_Päikesekiirgus_tegur: Undefined; 350_Klaaspakett: -; 360_Ratastooliga: no; 365_Isesulguv: no; 905_Mudel: -; 915_Kasutus-ja_hooldusjuhend: LÄHTUDA TOOTJAFIRMA INFOLEHEST
Pset_DoorCommon - ThermalTransmittance: 0
Pset_ManufacturerTypeInformation - Manufacturer: SAKU METALL VÕI ANALOOG
AC_Pset_RenovationAndPhasing - Renovation Status: New
Name | In | OverallHeight (mm) | OverallWidth (mm) | Classification | 310_Materjal | 376_Viimistlus_väljast | 375_Viimistlus_seest | 001_Nimetus | 300_Tüüp = Reference | 305_Ava_mõõt | 315_Avanemine | 330_Tulekindlus | 355_Pindala (m2) | 370_Evakuatsiooniväljapääs | 380_Lukustus | 900_Tootja | 910_Tooteinfo | FireRating = FireResistanceRating
SU-18* | Esimene korrus | 2300 | 900 | 1.10 IfcDoorStyle (uks) (RKAS BIM + ARCHICAD Classification); 523 Terasuksed (V1- EHITUSKULUDE LIIGITAMINE EVS 885:2005) | TERAS | LENG: HALL, RAL 7045, UKSELEHT: HALL, RAL 7045 | LENG: HALL, RAL 7045, UKSELEHT: HALL, RAL 7045 | SISEUKS | SU-18* | 900x2 300 | PAREMKÄE UKS ; ARCHICAD tüüp: Side Hung | EI30 | 2.07 | yes | VARUSTADA SOLENOIDMOOTORLUKUGA (VT. NÕRKVOOLU PROJEKTI). SISSEPOOLE LIBLIKLUKUSTUS, TREPIKOJA, KORIDORI POOLT LUKUSTAV VÕTMEGA. KÄEPIDE ASSA RUKOLINE, L-KUJULINE ÜMARATE KATETEGA LINK, HARJATUD, ROOSTEVABA, OTS TAGASIPÖÖRDEGA. HINGED VASTAVALT TOOTJALE. | SAKU METALL | LÄHTUDA TOOTJAFIRMA INFOLEHEST | EI-30 | Avatäited - 10 Tulekindlus: EI-30
SU-40 | Teine korrus | 2200 | 800 | 1.10 IfcDoorStyle (uks) (RKAS BIM + ARCHICAD Classification); 526 PVC uksed (V1- EHITUSKULUDE LIIGITAMINE EVS 885:2005) | PVC | <376_Viimistlus_väljast> | <375_Viimistlus_seest> | SISEUKS, PESURUUM | SU-40 | 800x2 200 | PAREMAKÄE UKS; ARCHICAD tüüp: Side Hung | nõudeid ei esitata | 1.76 | no | MITTELUKUSTATAV. KÄEPIDE ASSA RUKOLINE, L-KUJULINE ÜMARATE KATETEGA LINK, HARJATUD, ROOSTEVABA, OTS TAGASIPÖÖRDEGA. HINGED VASTAVALT TOOTJALE. | - | UKSESISENE VENTILATSIOONIREST (400x200 MM), TOON: UKSELEHEGA SAMASUUNE. LÄHTUDA TOOTJAFIRMA INFOLEHEST | EI-30/Sa

# IfcDoor: Door 24 (3)
In: Teine korrus
Type - OperationType: SINGLE_SWING_LEFT; ParameterTakesPrecedence: no; Sizeable: no
Type - Door Lining Properties - LiningThickness: 40 mm; ThresholdDepth: 100 mm; ThresholdThickness: 12 mm; LiningOffset: 140 mm; ThresholdOffset: 140 mm
Type - Door Panel Properties - Panel 1 - PanelDepth: 40 mm; PanelOperation: SWINGING; PanelWidth: 1; PanelPosition: MIDDLE
AR_Uks - 320_Klaas: -; 325_Helipidavus: -; 335_Välispiire: no; 340_Soojusläbivus: 0; 345_Päikesekiirgus_tegur: Undefined; 350_Klaaspakett: -; 365_Isesulguv: no; 915_Kasutus-ja_hooldusjuhend: LÄHTUDA TOOTJAFIRMA INFOLEHEST
Pset_DoorCommon - FireRating: EI-30/Sa; ThermalTransmittance: 0
Pset_FireRatingProperties - FireResistanceRating: EI-30/Sa
Pset_ManufacturerTypeInformation - Manufacturer: SAKU METALL VÕI ANALOOG
AC_Pset_RenovationAndPhasing - Renovation Status: New
Name | OverallHeight (mm) | OverallWidth (mm) | Classification | 310_Materjal | 375_Viimistlus_seest = 376_Viimistlus_väljast | 001_Nimetus | 300_Tüüp = Reference | 305_Ava_mõõt | 315_Avanemine | 330_Tulekindlus | 355_Pindala (m2) | 360_Ratastooliga | 370_Evakuatsiooniväljapääs | 380_Lukustus | 900_Tootja | 905_Mudel | 910_Tooteinfo
2 x SU-35 | 2200 | 800 | 1.10 IfcDoorStyle (uks) (RKAS BIM + ARCHICAD Classification); 525 Puituksed (V1- EHITUSKULUDE LIIGITAMINE EVS 885:2005) | PUIT | LENG: HALL, RAL 7045, UKSELEHT: KASESPOON | SU-35 | SU-35 | 800x2 200 | PAREMAKÄE UKS; ARCHICAD tüüp: Side Hung | nõudeid ei esitata | 1.76 | yes | no | VÄLJASPOOLT LUKUSTATAV JA LISADA LUKUSTUSASENDI NÄITAJA, SISSEPOOLE LIBLIKLUKUSTUS. KÄEPIDE ASSA RUKOLINE, L-KUJULINE ÜMARATE KATETEGA LINK, HARJATUD, ROOSTEVABA, OTS TAGASIPÖÖRDEGA. HINGED VASTAVALT TOOTJALE. | JELD-WEN | 40D | UKSE KOHALE VENTILATSIOONIREST. LÄHTUDA TOOTJAFIRMA INFOLEHEST
SU-23* | 2300 | 900 | 1.10 IfcDoorStyle (uks) (RKAS BIM + ARCHICAD Classification); 523 Terasuksed (V1- EHITUSKULUDE LIIGITAMINE EVS 885:2005) | TERAS | LENG: HALL, RAL 7045, UKSELEHT: HALL, RAL 7045 | SISEUKS | SU-23* | 900x2 300 | PAREMKÄE UKS ; ARCHICAD tüüp: Side Hung | EI30 | 2.07 | no | yes | VARUSTADA SOLENOIDMOOTORLUKUGA (VT. NÕRKVOOLU PROJEKTI). SISSEPOOLE LIBLIKLUKUSTUS, TREPIKOJA, KORIDORI POOLT LUKUSTAV VÕTMEGA. KÄEPIDE ASSA RUKOLINE, L-KUJULINE ÜMARATE KATETEGA LINK, HARJATUD, ROOSTEVABA, OTS TAGASIPÖÖRDEGA. HINGED VASTAVALT TOOTJALE. | SAKU METALL | - | LÄHTUDA TOOTJAFIRMA INFOLEHEST | Avatäited - 10 Tulekindlus: EI-30

# IfcDoor: Door 24, SU-34
In: Esimene korrus
Type - OperationType: SINGLE_SWING_LEFT; ParameterTakesPrecedence: no; Sizeable: no
Type - Door Lining Properties - LiningThickness: 40 mm; ThresholdDepth: 150 mm; ThresholdThickness: 12 mm; LiningOffset: 0 mm; ThresholdOffset: 0 mm
Type - Door Panel Properties - Panel 1 - PanelDepth: 40 mm; PanelOperation: SWINGING; PanelWidth: 1; PanelPosition: MIDDLE
OverallHeight: 2200 mm; OverallWidth: 1000 mm; Classification: 1.10 IfcDoorStyle (uks) (RKAS BIM + ARCHICAD Classification); 525 Puituksed (V1- EHITUSKULUDE LIIGITAMINE EVS 885:2005)
AR_Uks - 315_Avanemine: <315_Avanemine>; 310_Materjal: PUIT; 375_Viimistlus_seest: LENG: HALL, RAL 7045, UKSELEHT: KASESPOON; 376_Viimistlus_väljast: LENG: HALL, RAL 7045, UKSELEHT: KASESPOON; 001_Nimetus: SU-34; 300_Tüüp: SU-34; 305_Ava_mõõt: 1 000x2 200; 320_Klaas: -; 325_Helipidavus: -; 330_Tulekindlus: nõudeid ei esitata; 335_Välispiire: no; 340_Soojusläbivus: 0; 345_Päikesekiirgus_tegur: Undefined; 350_Klaaspakett: -; 355_Pindala: 2.2 m2; 360_Ratastooliga: yes; 365_Isesulguv: no; 370_Evakuatsiooniväljapääs: no; 380_Lukustus: VÄLJASPOOLT LUKUSTATAV JA LISADA LUKUSTUSASENDI NÄITAJA, SISSEPOOLE LIBLIKLUKUSTUS. KÄEPIDE ASSA RUKOLINE, L-KUJULINE ÜMARATE KATETEGA LINK, HARJATUD, ROOSTEVABA, OTS TAGASIPÖÖRDEGA. HINGED VASTAVALT TOOTJALE.; 900_Tootja: JELD-WEN; 905_Mudel: 40D; 910_Tooteinfo: UKSE KOHALE VENTILATSIOONIREST. LÄHTUDA TOOTJAFIRMA INFOLEHEST; 915_Kasutus-ja_hooldusjuhend: LÄHTUDA TOOTJAFIRMA INFOLEHEST
Pset_DoorCommon - Reference: SU-34; FireRating: EI-30/Sa; ThermalTransmittance: 0
Pset_FireRatingProperties - FireResistanceRating: EI-30/Sa
Pset_ManufacturerTypeInformation - Manufacturer: SAKU METALL VÕI ANALOOG
AC_Pset_RenovationAndPhasing - Renovation Status: New

# IfcDoor: Door 24 (2)
Type - OperationType: SINGLE_SWING_LEFT; ParameterTakesPrecedence: no; Sizeable: no
Type - Door Lining Properties - LiningThickness: 40 mm; ThresholdDepth: 150 mm; ThresholdThickness: 12 mm; LiningOffset: 0 mm; ThresholdOffset: 40 mm
Type - Door Panel Properties - Panel 1 - PanelDepth: 40 mm; PanelOperation: SWINGING; PanelWidth: 1; PanelPosition: MIDDLE
OverallHeight: 2200 mm
AR_Uks - 320_Klaas: -; 325_Helipidavus: -; 330_Tulekindlus: nõudeid ei esitata; 335_Välispiire: no; 340_Soojusläbivus: 0; 345_Päikesekiirgus_tegur: Undefined; 350_Klaaspakett: -; 360_Ratastooliga: no; 365_Isesulguv: no; 370_Evakuatsiooniväljapääs: no; 915_Kasutus-ja_hooldusjuhend: LÄHTUDA TOOTJAFIRMA INFOLEHEST
Pset_DoorCommon - FireRating: EI-30/Sa; ThermalTransmittance: 0
Pset_FireRatingProperties - FireResistanceRating: EI-30/Sa
Pset_ManufacturerTypeInformation - Manufacturer: SAKU METALL VÕI ANALOOG
AC_Pset_RenovationAndPhasing - Renovation Status: New
Name | In | OverallWidth (mm) | Classification | 380_Lukustus | 315_Avanemine | 310_Materjal | 375_Viimistlus_seest | 376_Viimistlus_väljast | 001_Nimetus | 300_Tüüp = Reference | 305_Ava_mõõt | 355_Pindala (m2) | 900_Tootja | 905_Mudel | 910_Tooteinfo
SU-37 | Esimene korrus | 900 | 1.10 IfcDoorStyle (uks) (RKAS BIM + ARCHICAD Classification); 525 Puituksed (V1- EHITUSKULUDE LIIGITAMINE EVS 885:2005) | VÄLJASPOOLT LUKUSTATAV, SISSEPOOLE LIBLIKLUKUSTUS. KÄEPIDE ASSA RUKOLINE, L-KUJULINE ÜMARATE KATETEGA LINK, HARJATUD, ROOSTEVABA, OTS TAGASIPÖÖRDEGA. HINGED VASTAVALT TOOTJALE. | <315_Avanemine> | PUIT | LENG: HALL, RAL 7045, UKSELEHT: KASESPOON | LENG: HALL, RAL 7045, UKSELEHT: KASESPOON | SU-37 | SU-37 | 900x2 200 | 1.98 | JELD-WEN | 40D | UKSE KOHALE VENTILATSIOONIREST. LÄHTUDA TOOTJAFIRMA INFOLEHEST
SU-40 | Teine korrus | 800 | 1.10 IfcDoorStyle (uks) (RKAS BIM + ARCHICAD Classification); 526 PVC uksed (V1- EHITUSKULUDE LIIGITAMINE EVS 885:2005) | MITTELUKUSTATAV. KÄEPIDE ASSA RUKOLINE, L-KUJULINE ÜMARATE KATETEGA LINK, HARJATUD, ROOSTEVABA, OTS TAGASIPÖÖRDEGA. HINGED VASTAVALT TOOTJALE. | PAREMAKÄE UKS; ARCHICAD tüüp: Side Hung | PVC | <375_Viimistlus_seest> | <376_Viimistlus_väljast> | SISEUKS, PESURUUM | SU-40 | 800x2 200 | 1.76 | - | - | UKSESISENE VENTILATSIOONIREST (400x200 MM), TOON: UKSELEHEGA SAMASUUNE. LÄHTUDA TOOTJAFIRMA INFOLEHEST

# IfcDoor: Door 24 (3)
In: Esimene korrus
Type - OperationType: SINGLE_SWING_LEFT; ParameterTakesPrecedence: no; Sizeable: no
Type - Door Lining Properties - LiningThickness: 40 mm; ThresholdDepth: 150 mm; ThresholdThickness: 12 mm; LiningOffset: 190 mm; ThresholdOffset: 230 mm
Type - Door Panel Properties - Panel 1 - PanelDepth: 40 mm; PanelOperation: SWINGING; PanelWidth: 1; PanelPosition: MIDDLE
OverallHeight: 2300 mm; OverallWidth: 900 mm
AR_Uks - 305_Ava_mõõt: 900x2 300; 320_Klaas: -; 325_Helipidavus: -; 335_Välispiire: no; 340_Soojusläbivus: 0; 345_Päikesekiirgus_tegur: Undefined; 350_Klaaspakett: -; 355_Pindala: 2.07 m2; 360_Ratastooliga: no; 365_Isesulguv: no; 910_Tooteinfo: LÄHTUDA TOOTJAFIRMA INFOLEHEST; 915_Kasutus-ja_hooldusjuhend: LÄHTUDA TOOTJAFIRMA INFOLEHEST
Pset_DoorCommon - ThermalTransmittance: 0
Pset_ManufacturerTypeInformation - Manufacturer: SAKU METALL VÕI ANALOOG
AC_Pset_RenovationAndPhasing - Renovation Status: New
Name | Classification | 310_Materjal | 376_Viimistlus_väljast = 375_Viimistlus_seest | 001_Nimetus | 300_Tüüp = Reference | 315_Avanemine | 330_Tulekindlus | 370_Evakuatsiooniväljapääs | 380_Lukustus | 900_Tootja | 905_Mudel | FireRating = FireResistanceRating
SU-17* | 1.10 IfcDoorStyle (uks) (RKAS BIM + ARCHICAD Classification); 523 Terasuksed (V1- EHITUSKULUDE LIIGITAMINE EVS 885:2005) | TERAS | LENG: HALL, RAL 7045, UKSELEHT: HALL, RAL 7045 | SISEUKS | SU-17* | PAREMAKÄE UKS ; ARCHICAD tüüp: Side Hung | EI30 | yes | VARUSTADA SOLENOIDMOOTORLUKUGA (VT. NÕRKVOOLU PROJEKTI). SISSEPOOLE LIBLIKLUKUSTUS, TREPIKOJA, KORIDORI POOLT LUKUSTAV VÕTMEGA. KÄEPIDE ASSA RUKOLINE, L-KUJULINE ÜMARATE KATETEGA LINK, HARJATUD, ROOSTEVABA, OTS TAGASIPÖÖRDEGA. HINGED VASTAVALT TOOTJALE. | SAKU METALL | - | EI-30 | Avatäited - 10 Tulekindlus: EI-30
SU-18* | 1.10 IfcDoorStyle (uks) (RKAS BIM + ARCHICAD Classification); 523 Terasuksed (V1- EHITUSKULUDE LIIGITAMINE EVS 885:2005) | TERAS | LENG: HALL, RAL 7045, UKSELEHT: HALL, RAL 7045 | SISEUKS | SU-18* | PAREMKÄE UKS ; ARCHICAD tüüp: Side Hung | EI30 | yes | VARUSTADA SOLENOIDMOOTORLUKUGA (VT. NÕRKVOOLU PROJEKTI). SISSEPOOLE LIBLIKLUKUSTUS, TREPIKOJA, KORIDORI POOLT LUKUSTAV VÕTMEGA. KÄEPIDE ASSA RUKOLINE, L-KUJULINE ÜMARATE KATETEGA LINK, HARJATUD, ROOSTEVABA, OTS TAGASIPÖÖRDEGA. HINGED VASTAVALT TOOTJALE. | SAKU METALL | -
SU-32 | 1.10 IfcDoorStyle (uks) (RKAS BIM + ARCHICAD Classification); 525 Puituksed (V1- EHITUSKULUDE LIIGITAMINE EVS 885:2005) | PUIT | LENG: HALL, RAL 7045, UKSELEHT: KASESPOON | SU-32 | SU-32 | <315_Avanemine> | nõudeid ei esitata | no | VÄLJASPOOLT LUKUSTATAV, SISSEPOOLE LIBLIKLUKUSTUS. KÄEPIDE ASSA RUKOLINE, L-KUJULINE ÜMARATE KATETEGA LINK, HARJATUD, ROOSTEVABA, OTS TAGASIPÖÖRDEGA. HINGED VASTAVALT TOOTJALE. | JELD-WEN | S41 | EI-30/Sa

# IfcDoor: Door 24 (2)
In: Teine korrus
Type - OperationType: SINGLE_SWING_LEFT; ParameterTakesPrecedence: no; Sizeable: no
Type - Door Lining Properties - LiningThickness: 40 mm; ThresholdDepth: 160 mm; ThresholdThickness: 12 mm; LiningOffset: 0 mm; ThresholdOffset: 40 mm
Type - Door Panel Properties - Panel 1 - PanelDepth: 40 mm; PanelOperation: SWINGING; PanelWidth: 1; PanelPosition: MIDDLE
AR_Uks - 320_Klaas: -; 325_Helipidavus: -; 330_Tulekindlus: nõudeid ei esitata; 335_Välispiire: no; 340_Soojusläbivus: 0; 345_Päikesekiirgus_tegur: Undefined; 350_Klaaspakett: -; 365_Isesulguv: no; 915_Kasutus-ja_hooldusjuhend: LÄHTUDA TOOTJAFIRMA INFOLEHEST
Pset_DoorCommon - FireRating: EI-30/Sa; ThermalTransmittance: 0
Pset_FireRatingProperties - FireResistanceRating: EI-30/Sa
Pset_ManufacturerTypeInformation - Manufacturer: SAKU METALL VÕI ANALOOG
AC_Pset_RenovationAndPhasing - Renovation Status: New
Name | OverallHeight (mm) | OverallWidth (mm) | Classification | 310_Materjal | 375_Viimistlus_seest = 376_Viimistlus_väljast | 001_Nimetus | 300_Tüüp = Reference | 305_Ava_mõõt | 315_Avanemine | 355_Pindala (m2) | 360_Ratastooliga | 370_Evakuatsiooniväljapääs | 380_Lukustus | 900_Tootja | 905_Mudel | 910_Tooteinfo
SU-19 | 2300 | 900 | 1.10 IfcDoorStyle (uks) (RKAS BIM + ARCHICAD Classification); 523 Terasuksed (V1- EHITUSKULUDE LIIGITAMINE EVS 885:2005) | TERAS | LENG: HALL, RAL 7045, UKSELEHT: HALL, RAL 7045 | SISEUKS | SU-19 | 900x2 300 | PAREMKÄE UKS ; ARCHICAD tüüp: Side Hung | 2.07 | no | yes | MITTELUKUSTATAV. KÄEPIDE ASSA RUKOLINE, L-KUJULINE ÜMARATE KATETEGA LINK, HARJATUD, ROOSTEVABA, OTS TAGASIPÖÖRDEGA. HINGED VASTAVALT TOOTJALE. | SAKU METALL | - | SOOJUSTATUD UKS. LÄHTUDA TOOTJAFIRMA INFOLEHEST | Avatäited - 10 Tulekindlus: EI-30
SU-35 | 2200 | 800 | 1.10 IfcDoorStyle (uks) (RKAS BIM + ARCHICAD Classification); 525 Puituksed (V1- EHITUSKULUDE LIIGITAMINE EVS 885:2005) | PUIT | LENG: HALL, RAL 7045, UKSELEHT: KASESPOON | SU-35 | SU-35 | 800x2 200 | PAREMAKÄE UKS; ARCHICAD tüüp: Side Hung | 1.76 | yes | no | VÄLJASPOOLT LUKUSTATAV JA LISADA LUKUSTUSASENDI NÄITAJA, SISSEPOOLE LIBLIKLUKUSTUS. KÄEPIDE ASSA RUKOLINE, L-KUJULINE ÜMARATE KATETEGA LINK, HARJATUD, ROOSTEVABA, OTS TAGASIPÖÖRDEGA. HINGED VASTAVALT TOOTJALE. | JELD-WEN | 40D | UKSE KOHALE VENTILATSIOONIREST. LÄHTUDA TOOTJAFIRMA INFOLEHEST

# IfcDoor: Door 24 (2)
In: Teine korrus
Type - OperationType: SINGLE_SWING_LEFT; ParameterTakesPrecedence: no; Sizeable: no
Type - Door Lining Properties - LiningThickness: 40 mm; ThresholdDepth: 160 mm; ThresholdThickness: 12 mm; LiningOffset: 200 mm; ThresholdOffset: 200 mm
Type - Door Panel Properties - Panel 1 - PanelDepth: 40 mm; PanelOperation: SWINGING; PanelWidth: 1; PanelPosition: MIDDLE
OverallHeight: 2300 mm; OverallWidth: 900 mm; Classification: 1.10 IfcDoorStyle (uks) (RKAS BIM + ARCHICAD Classification); 525 Puituksed (V1- EHITUSKULUDE LIIGITAMINE EVS 885:2005)
AR_Uks - 001_Nimetus: SU-33b; 300_Tüüp: SU-33b; 305_Ava_mõõt: 900x2 300; 315_Avanemine: PAREMAKÄE UKS; ARCHICAD tüüp: Side Hung; 320_Klaas: -; 325_Helipidavus: 30dB; 330_Tulekindlus: nõudeid ei esitata; 335_Välispiire: no; 340_Soojusläbivus: 0; 345_Päikesekiirgus_tegur: Undefined; 350_Klaaspakett: -; 355_Pindala: 2.07 m2; 360_Ratastooliga: no; 365_Isesulguv: no; 370_Evakuatsiooniväljapääs: no; 380_Lukustus: VÄLJASPOOLT LUKUSTATAV, SISSEPOOLE LIBLIKLUKUSTUS. KÄEPIDE ASSA RUKOLINE, L-KUJULINE ÜMARATE KATETEGA LINK, HARJATUD, ROOSTEVABA, OTS TAGASIPÖÖRDEGA. HINGED VASTAVALT TOOTJALE.; 900_Tootja: JELD-WEN; 905_Mudel: S41; 910_Tooteinfo: LÄHTUDA TOOTJAFIRMA INFOLEHEST; 915_Kasutus-ja_hooldusjuhend: LÄHTUDA TOOTJAFIRMA INFOLEHEST
Pset_DoorCommon - Reference: SU-33b; FireRating: EI-30/Sa; ThermalTransmittance: 0
Pset_FireRatingProperties - FireResistanceRating: EI-30/Sa
Pset_ManufacturerTypeInformation - Manufacturer: SAKU METALL VÕI ANALOOG
AC_Pset_RenovationAndPhasing - Renovation Status: New
Name | 310_Materjal | 375_Viimistlus_seest = 376_Viimistlus_väljast
SU-33b | PUIT | LENG: HALL, RAL 7045, UKSELEHT: KASESPOON
SU-33b | MUDELIS: väljast-PULBERVÄRVITUD, TOON: HALL, RAL 7045; KASESPOON; seest-PULBERVÄRVITUD, TOON: HALL, RAL 7045; KASESPOON; MÄRKUS: PUIT | MUDELIS: PULBERVÄRVITUD, TOON: HALL, RAL 7045; KASESPOON; MÄRKUS: LENG JA RAAMID: PULBERVÄRVITUD, TOON: HALL, RAL 7045, UKSELEHT: KASESPOON

# IfcDoor: Door 24 (2)
In: Esimene korrus
Type - OperationType: SINGLE_SWING_LEFT; ParameterTakesPrecedence: no; Sizeable: no
Type - Door Lining Properties - LiningThickness: 40 mm; ThresholdDepth: 200 mm; ThresholdThickness: 12 mm; LiningOffset: 0 mm; ThresholdOffset: 40 mm
Type - Door Panel Properties - Panel 1 - PanelDepth: 40 mm; PanelOperation: SWINGING; PanelWidth: 1; PanelPosition: MIDDLE
OverallHeight: 2300 mm; Classification: 1.10 IfcDoorStyle (uks) (RKAS BIM + ARCHICAD Classification); 523 Terasuksed (V1- EHITUSKULUDE LIIGITAMINE EVS 885:2005)
AR_Uks - 310_Materjal: TERAS; 376_Viimistlus_väljast: LENG: HALL, RAL 7045, UKSELEHT: HALL, RAL 7045; 375_Viimistlus_seest: LENG: HALL, RAL 7045, UKSELEHT: HALL, RAL 7045; 001_Nimetus: SISEUKS; 315_Avanemine: PAREMAKÄE UKS ; ARCHICAD tüüp: Side Hung; 320_Klaas: -; 325_Helipidavus: -; 335_Välispiire: no; 340_Soojusläbivus: 0; 350_Klaaspakett: -; 360_Ratastooliga: no; 365_Isesulguv: no; 900_Tootja: SAKU METALL; 905_Mudel: -; 915_Kasutus-ja_hooldusjuhend: LÄHTUDA TOOTJAFIRMA INFOLEHEST
Pset_DoorCommon - ThermalTransmittance: 0
AC_Pset_RenovationAndPhasing - Renovation Status: New
Name | OverallWidth (mm) | 300_Tüüp = Reference | 305_Ava_mõõt | 330_Tulekindlus | 345_Päikesekiirgus_tegur | 355_Pindala (m2) | 370_Evakuatsiooniväljapääs | 380_Lukustus | 910_Tooteinfo | Manufacturer
SU-17* | 900 | SU-17* | 900x2 300 | EI30 | Undefined | 2.07 | yes | VARUSTADA SOLENOIDMOOTORLUKUGA (VT. NÕRKVOOLU PROJEKTI). SISSEPOOLE LIBLIKLUKUSTUS, TREPIKOJA, KORIDORI POOLT LUKUSTAV VÕTMEGA. KÄEPIDE ASSA RUKOLINE, L-KUJULINE ÜMARATE KATETEGA LINK, HARJATUD, ROOSTEVABA, OTS TAGASIPÖÖRDEGA. HINGED VASTAVALT TOOTJALE. | LÄHTUDA TOOTJAFIRMA INFOLEHEST | SAKU METALL VÕI ANALOOG | Avatäited - 10 Tulekindlus: EI-30; Pset_DoorCommon - FireRating: EI-30; Pset_FireRatingProperties - FireResistanceRating: EI-30
SU-13 | 800 | SU-13 | 800x2 300 | nõudeid ei esitata | - | 1.84 | no | SISSEPOOLE, SAN. RUUMI LIBLIKLUKUSTUS. VÄLJASPOOLT LUKUSTATAV, LUKUSTUSE ASENDI NÄITAJA. KÄEPIDE ASSA RUKOLINE, L-KUJULINE ÜMARATE KATETEGA LINK, HARJATUD, ROOSTEVABA, OTS TAGASIPÖÖRDEGA. HINGED VASTAVALT TOOTJALE. | UKSESISENE VENTILATSIOONIREST (400x200 MM, TOON: HALL, RAL 7045). LÄHTUDA TOOTJAFIRMA INFOLEHEST | SAKU METALL

# IfcDoor: Door 24 (2)
In: Teine korrus
Type - OperationType: SINGLE_SWING_LEFT; ParameterTakesPrecedence: no; Sizeable: no
Type - Door Lining Properties - LiningThickness: 40 mm; ThresholdDepth: 257 mm; ThresholdThickness: 12 mm; LiningOffset: 297 mm; ThresholdOffset: 297 mm
Type - Door Panel Properties - Panel 1 - PanelDepth: 40 mm; PanelOperation: SWINGING; PanelWidth: 1; PanelPosition: MIDDLE
OverallHeight: 2200 mm; OverallWidth: 700 mm; Classification: 1.10 IfcDoorStyle (uks) (RKAS BIM + ARCHICAD Classification); 524 Klaasuksed (V1- EHITUSKULUDE LIIGITAMINE EVS 885:2005)
AR_Uks - 310_Materjal: PUIT; 375_Viimistlus_seest: LENG: HALL, RAL 7045, UKSELEHT: KASESPOON; 376_Viimistlus_väljast: LENG: HALL, RAL 7045, UKSELEHT: KASESPOON; 001_Nimetus: SISEUKS, LEILIRUUM; 300_Tüüp: SU-39; 305_Ava_mõõt: 700x2 200; 315_Avanemine: PAREMAKÄE UKS; ARCHICAD tüüp: Side Hung; 320_Klaas: ÜHEKORDNE KLAASIST UKSELEHT; 325_Helipidavus: -; 330_Tulekindlus: nõudeid ei esitata; 335_Välispiire: no; 340_Soojusläbivus: 0; 345_Päikesekiirgus_tegur: Undefined; 350_Klaaspakett: 8 MM, MATISTATUD KARASTATUD KLAAS; 355_Pindala: 1.54 m2; 360_Ratastooliga: no; 365_Isesulguv: no; 370_Evakuatsiooniväljapääs: no; 380_Lukustus: MITTELUKUSTATAV. PUIDUST VERTIKAALNE KÄEPIDE. HINGED VASTAVALT TOOTJALE.; 900_Tootja: JELD-WEN; 905_Mudel: SAUNA SAVU; 910_Tooteinfo: LÄHTUDA TOOTJAFIRMA INFOLEHEST; 915_Kasutus-ja_hooldusjuhend: LÄHTUDA TOOTJAFIRMA INFOLEHEST
Pset_DoorCommon - Reference: SU-39; ThermalTransmittance: 0
Pset_ManufacturerTypeInformation - Manufacturer: JELD-WEN/ SAUNA SAVU VÕI ANALOOG
AC_Pset_RenovationAndPhasing - Renovation Status: New

# IfcDoor: Door 24, SU-36
In: Teine korrus
Type - OperationType: SINGLE_SWING_RIGHT; ParameterTakesPrecedence: no; Sizeable: no
Type - Door Lining Properties - LiningThickness: 40 mm; ThresholdDepth: 100 mm; ThresholdThickness: 12 mm; LiningOffset: 0 mm; ThresholdOffset: 40 mm
Type - Door Panel Properties - Panel 1 - PanelDepth: 40 mm; PanelOperation: SWINGING; PanelWidth: 1; PanelPosition: MIDDLE
OverallHeight: 2200 mm; OverallWidth: 800 mm; Classification: 1.10 IfcDoorStyle (uks) (RKAS BIM + ARCHICAD Classification); 525 Puituksed (V1- EHITUSKULUDE LIIGITAMINE EVS 885:2005)
AR_Uks - 310_Materjal: PUIT; 375_Viimistlus_seest: LENG: HALL, RAL 7045, UKSELEHT: KASESPOON; 376_Viimistlus_väljast: LENG: HALL, RAL 7045, UKSELEHT: KASESPOON; 001_Nimetus: SU-36; 300_Tüüp: SU-36; 305_Ava_mõõt: 800x2 200; 315_Avanemine: VASAKUKÄE UKS; ARCHICAD tüüp: Side Hung; 320_Klaas: -; 325_Helipidavus: -; 330_Tulekindlus: nõudeid ei esitata; 335_Välispiire: no; 340_Soojusläbivus: 0; 345_Päikesekiirgus_tegur: Undefined; 350_Klaaspakett: -; 355_Pindala: 1.76 m2; 360_Ratastooliga: yes; 365_Isesulguv: no; 370_Evakuatsiooniväljapääs: no; 380_Lukustus: VÄLJASPOOLT LUKUSTATAV JA LISADA LUKUSTUSASENDI NÄITAJA, SISSEPOOLE LIBLIKLUKUSTUS. KÄEPIDE ASSA RUKOLINE, L-KUJULINE ÜMARATE KATETEGA LINK, HARJATUD, ROOSTEVABA, OTS TAGASIPÖÖRDEGA. HINGED VASTAVALT TOOTJALE.; 900_Tootja: JELD-WEN; 905_Mudel: 40D; 910_Tooteinfo: UKSE KOHALE VENTILATSIOONIREST. LÄHTUDA TOOTJAFIRMA INFOLEHEST; 915_Kasutus-ja_hooldusjuhend: LÄHTUDA TOOTJAFIRMA INFOLEHEST
Pset_DoorCommon - Reference: SU-36; FireRating: EI-30/Sa; ThermalTransmittance: 0
Pset_FireRatingProperties - FireResistanceRating: EI-30/Sa
Pset_ManufacturerTypeInformation - Manufacturer: SAKU METALL VÕI ANALOOG
AC_Pset_RenovationAndPhasing - Renovation Status: New

# IfcDoor: Door 24, SU-13
In: Esimene korrus
Type - OperationType: SINGLE_SWING_RIGHT; ParameterTakesPrecedence: no; Sizeable: no
Type - Door Lining Properties - LiningThickness: 40 mm; ThresholdDepth: 100 mm; ThresholdThickness: 12 mm; LiningOffset: 140 mm; ThresholdOffset: 180 mm
Type - Door Panel Properties - Panel 1 - PanelDepth: 40 mm; PanelOperation: SWINGING; PanelWidth: 1; PanelPosition: MIDDLE
OverallHeight: 2300 mm; OverallWidth: 800 mm; Classification: 1.10 IfcDoorStyle (uks) (RKAS BIM + ARCHICAD Classification); 523 Terasuksed (V1- EHITUSKULUDE LIIGITAMINE EVS 885:2005)
Pset_DoorCommon - Reference: SU-13; ThermalTransmittance: 0
AR_Uks - 001_Nimetus: SISEUKS; 300_Tüüp: SU-13; 305_Ava_mõõt: 800x2 300; 310_Materjal: MUDELIS: väljast-PULBERVÄRVITUD, TOON: HALL, RAL 7045; PULBERVÄRVITUD, TOON: HALL, RAL 7045; seest-PULBERVÄRVITUD, TOON: HALL, RAL 7045; PULBERVÄRVITUD, TOON: HALL, RAL 7045; MÄRKUS: TERAS; 315_Avanemine: PAREMAKÄE UKS ; ARCHICAD tüüp: Side Hung; 320_Klaas: -; 325_Helipidavus: -; 330_Tulekindlus: nõudeid ei esitata; 335_Välispiire: no; 340_Soojusläbivus: 0; 345_Päikesekiirgus_tegur: -; 350_Klaaspakett: -; 355_Pindala: 1.84 m2; 360_Ratastooliga: no; 365_Isesulguv: no; 370_Evakuatsiooniväljapääs: no; 375_Viimistlus_seest: MUDELIS: PULBERVÄRVITUD, TOON: HALL, RAL 7045; PULBERVÄRVITUD, TOON: HALL, RAL 7045; MÄRKUS: LENG: HALL, RAL 7045, UKSELEHT: HALL, RAL 7045; 376_Viimistlus_väljast: MUDELIS: PULBERVÄRVITUD, TOON: HALL, RAL 7045; PULBERVÄRVITUD, TOON: HALL, RAL 7045; MÄRKUS: LENG: HALL, RAL 7045, UKSELEHT: HALL, RAL 7045; 380_Lukustus: SISSEPOOLE, SAN. RUUMI LIBLIKLUKUSTUS. VÄLJASPOOLT LUKUSTATAV, LUKUSTUSE ASENDI NÄITAJA. KÄEPIDE ASSA RUKOLINE, L-KUJULINE ÜMARATE KATETEGA LINK, HARJATUD, ROOSTEVABA, OTS TAGASIPÖÖRDEGA. HINGED VASTAVALT TOOTJALE.; 900_Tootja: SAKU METALL; 905_Mudel: -; 910_Tooteinfo: UKSESISENE VENTILATSIOONIREST (400x200 MM, TOON: HALL, RAL 7045). LÄHTUDA TOOTJAFIRMA INFOLEHEST; 915_Kasutus-ja_hooldusjuhend: LÄHTUDA TOOTJAFIRMA INFOLEHEST
Pset_ManufacturerTypeInformation - Manufacturer: JELD-WEN/ 40D VÕI ANALOOG
AC_Pset_RenovationAndPhasing - Renovation Status: New

# IfcDoor: Door 24 (2)
In: Teine korrus
Type - OperationType: SINGLE_SWING_RIGHT; ParameterTakesPrecedence: no; Sizeable: no
Type - Door Lining Properties - LiningThickness: 40 mm; ThresholdDepth: 150 mm; ThresholdThickness: 12 mm; LiningOffset: 0 mm; ThresholdOffset: 0 mm
Type - Door Panel Properties - Panel 1 - PanelDepth: 40 mm; PanelOperation: SWINGING; PanelWidth: 1; PanelPosition: MIDDLE
AR_Uks - 320_Klaas: -; 325_Helipidavus: -; 335_Välispiire: no; 340_Soojusläbivus: 0; 345_Päikesekiirgus_tegur: Undefined; 350_Klaaspakett: -; 360_Ratastooliga: no; 365_Isesulguv: no; 915_Kasutus-ja_hooldusjuhend: LÄHTUDA TOOTJAFIRMA INFOLEHEST
Pset_DoorCommon - FireRating: EI-30/Sa; ThermalTransmittance: 0
Pset_FireRatingProperties - FireResistanceRating: EI-30/Sa
Pset_ManufacturerTypeInformation - Manufacturer: SAKU METALL VÕI ANALOOG
AC_Pset_RenovationAndPhasing - Renovation Status: New
Name | OverallHeight (mm) | OverallWidth (mm) | Classification | 310_Materjal | 375_Viimistlus_seest = 376_Viimistlus_väljast | 001_Nimetus | 300_Tüüp = Reference | 305_Ava_mõõt | 315_Avanemine | 330_Tulekindlus | 355_Pindala (m2) | 370_Evakuatsiooniväljapääs | 380_Lukustus | 900_Tootja | 905_Mudel | 910_Tooteinfo
SU-17*b | 2300 | 900 | 1.10 IfcDoorStyle (uks) (RKAS BIM + ARCHICAD Classification); 523 Terasuksed (V1- EHITUSKULUDE LIIGITAMINE EVS 885:2005) | TERAS | LENG: HALL, RAL 7045, UKSELEHT: HALL, RAL 7045 | SISEUKS | SU-17*b | 900x2 300 | PAREMAKÄE UKS ; ARCHICAD tüüp: Side Hung | EI30 | 2.07 | yes | VARUSTADA SOLENOIDMOOTORLUKUGA (VT. NÕRKVOOLU PROJEKTI). SISSEPOOLE LIBLIKLUKUSTUS, TREPIKOJA, KORIDORI POOLT LUKUSTAV VÕTMEGA. KÄEPIDE ASSA RUKOLINE, L-KUJULINE ÜMARATE KATETEGA LINK, HARJATUD, ROOSTEVABA, OTS TAGASIPÖÖRDEGA. HINGED VASTAVALT TOOTJALE. | SAKU METALL | - | LÄHTUDA TOOTJAFIRMA INFOLEHEST | Avatäited - 10 Tulekindlus: EI-30
SU-37b | 2200 | 800 | 1.10 IfcDoorStyle (uks) (RKAS BIM + ARCHICAD Classification); 525 Puituksed (V1- EHITUSKULUDE LIIGITAMINE EVS 885:2005) | PUIT | LENG: HALL, RAL 7045, UKSELEHT: KASESPOON | SU-37b | SU-37b | 800x2 200 | VASAKUKÄE UKS; ARCHICAD tüüp: Side Hung | nõudeid ei esitata | 1.76 | no | VÄLJASPOOLT LUKUSTATAV, SISSEPOOLE LIBLIKLUKUSTUS. KÄEPIDE ASSA RUKOLINE, L-KUJULINE ÜMARATE KATETEGA LINK, HARJATUD, ROOSTEVABA, OTS TAGASIPÖÖRDEGA. HINGED VASTAVALT TOOTJALE. | JELD-WEN | 40D | UKSE KOHALE VENTILATSIOONIREST. LÄHTUDA TOOTJAFIRMA INFOLEHEST

# IfcDoor: Door 24, SU-40
In: Teine korrus
Type - OperationType: SINGLE_SWING_RIGHT; ParameterTakesPrecedence: no; Sizeable: no
Type - Door Lining Properties - LiningThickness: 40 mm; ThresholdDepth: 150 mm; ThresholdThickness: 12 mm; LiningOffset: 0 mm; ThresholdOffset: 40 mm
Type - Door Panel Properties - Panel 1 - PanelDepth: 40 mm; PanelOperation: SWINGING; PanelWidth: 1; PanelPosition: MIDDLE
OverallHeight: 2200 mm; OverallWidth: 800 mm; Classification: 1.10 IfcDoorStyle (uks) (RKAS BIM + ARCHICAD Classification); 526 PVC uksed (V1- EHITUSKULUDE LIIGITAMINE EVS 885:2005)
AR_Uks - 360_Ratastooliga: no; 375_Viimistlus_seest: <375_Viimistlus_seest>; 376_Viimistlus_väljast: <376_Viimistlus_väljast>; 310_Materjal: PVC; 001_Nimetus: SISEUKS, PESURUUM; 300_Tüüp: SU-40; 305_Ava_mõõt: 800x2 200; 315_Avanemine: PAREMAKÄE UKS; ARCHICAD tüüp: Side Hung; 320_Klaas: -; 325_Helipidavus: -; 330_Tulekindlus: nõudeid ei esitata; 335_Välispiire: no; 340_Soojusläbivus: 0; 345_Päikesekiirgus_tegur: Undefined; 350_Klaaspakett: -; 355_Pindala: 1.76 m2; 365_Isesulguv: no; 370_Evakuatsiooniväljapääs: no; 380_Lukustus: MITTELUKUSTATAV. KÄEPIDE ASSA RUKOLINE, L-KUJULINE ÜMARATE KATETEGA LINK, HARJATUD, ROOSTEVABA, OTS TAGASIPÖÖRDEGA. HINGED VASTAVALT TOOTJALE.; 900_Tootja: -; 905_Mudel: -; 910_Tooteinfo: UKSESISENE VENTILATSIOONIREST (400x200 MM), TOON: UKSELEHEGA SAMASUUNE. LÄHTUDA TOOTJAFIRMA INFOLEHEST; 915_Kasutus-ja_hooldusjuhend: LÄHTUDA TOOTJAFIRMA INFOLEHEST
Pset_DoorCommon - Reference: SU-40; FireRating: EI-30/Sa; ThermalTransmittance: 0
Pset_FireRatingProperties - FireResistanceRating: EI-30/Sa
Pset_ManufacturerTypeInformation - Manufacturer: SAKU METALL VÕI ANALOOG
AC_Pset_RenovationAndPhasing - Renovation Status: New

# IfcDoor: Door 24, SU-14
In: Esimene korrus
Type - OperationType: SINGLE_SWING_RIGHT; ParameterTakesPrecedence: no; Sizeable: no
Type - Door Lining Properties - LiningThickness: 40 mm; ThresholdDepth: 150 mm; ThresholdThickness: 12 mm; LiningOffset: 190 mm; ThresholdOffset: 190 mm
Type - Door Panel Properties - Panel 1 - PanelDepth: 40 mm; PanelOperation: SWINGING; PanelWidth: 1; PanelPosition: MIDDLE
OverallHeight: 2300 mm; OverallWidth: 900 mm; Classification: 1.10 IfcDoorStyle (uks) (RKAS BIM + ARCHICAD Classification); 523 Terasuksed (V1- EHITUSKULUDE LIIGITAMINE EVS 885:2005)
Pset_ManufacturerTypeInformation - Manufacturer: SAKU METALL
AR_Uks - 310_Materjal: TERAS; 376_Viimistlus_väljast: LENG: HALL, RAL 7045, UKSELEHT: HALL, RAL 7045; 375_Viimistlus_seest: LENG: HALL, RAL 7045, UKSELEHT: HALL, RAL 7045; 001_Nimetus: SISEUKS; 300_Tüüp: SU-14; 305_Ava_mõõt: 900x2 300; 315_Avanemine: VASAKUKÄE UKS; ARCHICAD tüüp: Side Hung; 320_Klaas: -; 325_Helipidavus: -; 330_Tulekindlus: nõudeid ei esitata; 335_Välispiire: no; 340_Soojusläbivus: 0; 345_Päikesekiirgus_tegur: -; 350_Klaaspakett: -; 355_Pindala: 2.07 m2; 360_Ratastooliga: no; 365_Isesulguv: no; 370_Evakuatsiooniväljapääs: no; 380_Lukustus: SISSEPOOLE, SAN. RUUMI LIBLIKLUKUSTUS. VÄLJASPOOLT LUKUSTATAV, LUKUSTUSE ASENDI NÄITAJA. KÄEPIDE ASSA RUKOLINE, L-KUJULINE ÜMARATE KATETEGA LINK, HARJATUD, ROOSTEVABA, OTS TAGASIPÖÖRDEGA. HINGED VASTAVALT TOOTJALE.; 900_Tootja: SAKU METALL; 905_Mudel: -; 910_Tooteinfo: UKSESISENE VENTILATSIOONIREST (400x200 MM, TOON: HALL, RAL 7045). LÄHTUDA TOOTJAFIRMA INFOLEHEST; 915_Kasutus-ja_hooldusjuhend: LÄHTUDA TOOTJAFIRMA INFOLEHEST
Pset_DoorCommon - Reference: SU-14; ThermalTransmittance: 0
AC_Pset_RenovationAndPhasing - Renovation Status: New

# IfcDoor: Door 24, SU-15
In: Esimene korrus
Type - OperationType: SINGLE_SWING_RIGHT; ParameterTakesPrecedence: no; Sizeable: no
Type - Door Lining Properties - LiningThickness: 40 mm; ThresholdDepth: 150 mm; ThresholdThickness: 12 mm; LiningOffset: 190 mm; ThresholdOffset: 230 mm
Type - Door Panel Properties - Panel 1 - PanelDepth: 40 mm; PanelOperation: SWINGING; PanelWidth: 1; PanelPosition: MIDDLE
OverallHeight: 2300 mm; OverallWidth: 900 mm; Classification: 1.10 IfcDoorStyle (uks) (RKAS BIM + ARCHICAD Classification); 523 Terasuksed (V1- EHITUSKULUDE LIIGITAMINE EVS 885:2005)
Pset_ManufacturerTypeInformation - Manufacturer: SAKU METALL
AR_Uks - 310_Materjal: TERAS; 376_Viimistlus_väljast: LENG: HALL, RAL 7045, UKSELEHT: HALL, RAL 7045; 375_Viimistlus_seest: LENG: HALL, RAL 7045, UKSELEHT: HALL, RAL 7045; 001_Nimetus: SISEUKS; 300_Tüüp: SU-15; 305_Ava_mõõt: 900x2 300; 315_Avanemine: PAREMKÄE UKS ; ARCHICAD tüüp: Side Hung; 320_Klaas: -; 325_Helipidavus: -; 330_Tulekindlus: nõudeid ei esitata; 335_Välispiire: no; 340_Soojusläbivus: 0; 345_Päikesekiirgus_tegur: -; 350_Klaaspakett: -; 355_Pindala: 2.07 m2; 360_Ratastooliga: no; 365_Isesulguv: no; 370_Evakuatsiooniväljapääs: no; 380_Lukustus: SISSEPOOLE, SAN. RUUMI LIBLIKLUKUSTUS. VÄLJASPOOLT LUKUSTATAV, LUKUSTUSE ASENDI NÄITAJA. KÄEPIDE ASSA RUKOLINE, L-KUJULINE ÜMARATE KATETEGA LINK, HARJATUD, ROOSTEVABA, OTS TAGASIPÖÖRDEGA. HINGED VASTAVALT TOOTJALE.; 900_Tootja: SAKU METALL; 905_Mudel: -; 910_Tooteinfo: UKSESISENE VENTILATSIOONIREST (400x200 MM, TOON: HALL, RAL 7045). LÄHTUDA TOOTJAFIRMA INFOLEHEST; 915_Kasutus-ja_hooldusjuhend: LÄHTUDA TOOTJAFIRMA INFOLEHEST
Pset_DoorCommon - Reference: SU-15; ThermalTransmittance: 0
AC_Pset_RenovationAndPhasing - Renovation Status: New

# IfcDoor: Door 24 (3)
In: Teine korrus
Type - OperationType: SINGLE_SWING_RIGHT; ParameterTakesPrecedence: no; Sizeable: no
Type - Door Lining Properties - LiningThickness: 40 mm; ThresholdDepth: 160 mm; ThresholdThickness: 12 mm; LiningOffset: 200 mm; ThresholdOffset: 200 mm
Type - Door Panel Properties - Panel 1 - PanelDepth: 40 mm; PanelOperation: SWINGING; PanelWidth: 1; PanelPosition: MIDDLE
OverallHeight: 2300 mm; OverallWidth: 900 mm; Classification: 1.10 IfcDoorStyle (uks) (RKAS BIM + ARCHICAD Classification); 525 Puituksed (V1- EHITUSKULUDE LIIGITAMINE EVS 885:2005)
AR_Uks - 310_Materjal: PUIT; 375_Viimistlus_seest: LENG: HALL, RAL 7045, UKSELEHT: KASESPOON; 376_Viimistlus_väljast: LENG: HALL, RAL 7045, UKSELEHT: KASESPOON; 001_Nimetus: SU-33; 300_Tüüp: SU-33; 305_Ava_mõõt: 900x2 300; 315_Avanemine: VASAKUKÄE UKS; ARCHICAD tüüp: Side Hung; 320_Klaas: -; 325_Helipidavus: 30dB; 330_Tulekindlus: nõudeid ei esitata; 335_Välispiire: no; 340_Soojusläbivus: 0; 345_Päikesekiirgus_tegur: Undefined; 350_Klaaspakett: -; 355_Pindala: 2.07 m2; 360_Ratastooliga: no; 365_Isesulguv: no; 370_Evakuatsiooniväljapääs: no; 380_Lukustus: VÄLJASPOOLT LUKUSTATAV, SISSEPOOLE LIBLIKLUKUSTUS. KÄEPIDE ASSA RUKOLINE, L-KUJULINE ÜMARATE KATETEGA LINK, HARJATUD, ROOSTEVABA, OTS TAGASIPÖÖRDEGA. HINGED VASTAVALT TOOTJALE.; 900_Tootja: JELD-WEN; 905_Mudel: S41; 910_Tooteinfo: LÄHTUDA TOOTJAFIRMA INFOLEHEST; 915_Kasutus-ja_hooldusjuhend: LÄHTUDA TOOTJAFIRMA INFOLEHEST
Pset_DoorCommon - Reference: SU-33; FireRating: EI-30/Sa; ThermalTransmittance: 0
Pset_FireRatingProperties - FireResistanceRating: EI-30/Sa
Pset_ManufacturerTypeInformation - Manufacturer: SAKU METALL VÕI ANALOOG
AC_Pset_RenovationAndPhasing - Renovation Status: New

# IfcDoor: Door with Sidelight on Side 2 24 (4)
Type - OperationType: SINGLE_SWING_LEFT; ParameterTakesPrecedence: no; Sizeable: no
Type - Door Panel Properties - Panel 1 - PanelDepth: 40 mm; PanelOperation: SWINGING; PanelWidth: 1; PanelPosition: MIDDLE
OverallHeight: 2300 mm
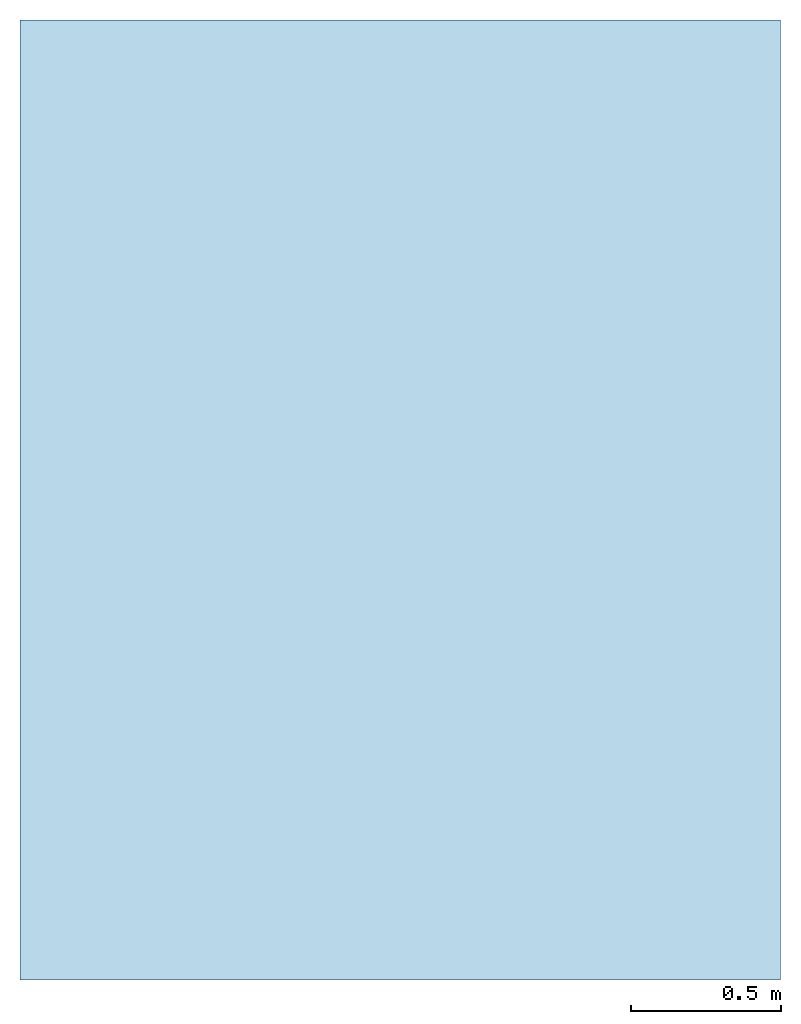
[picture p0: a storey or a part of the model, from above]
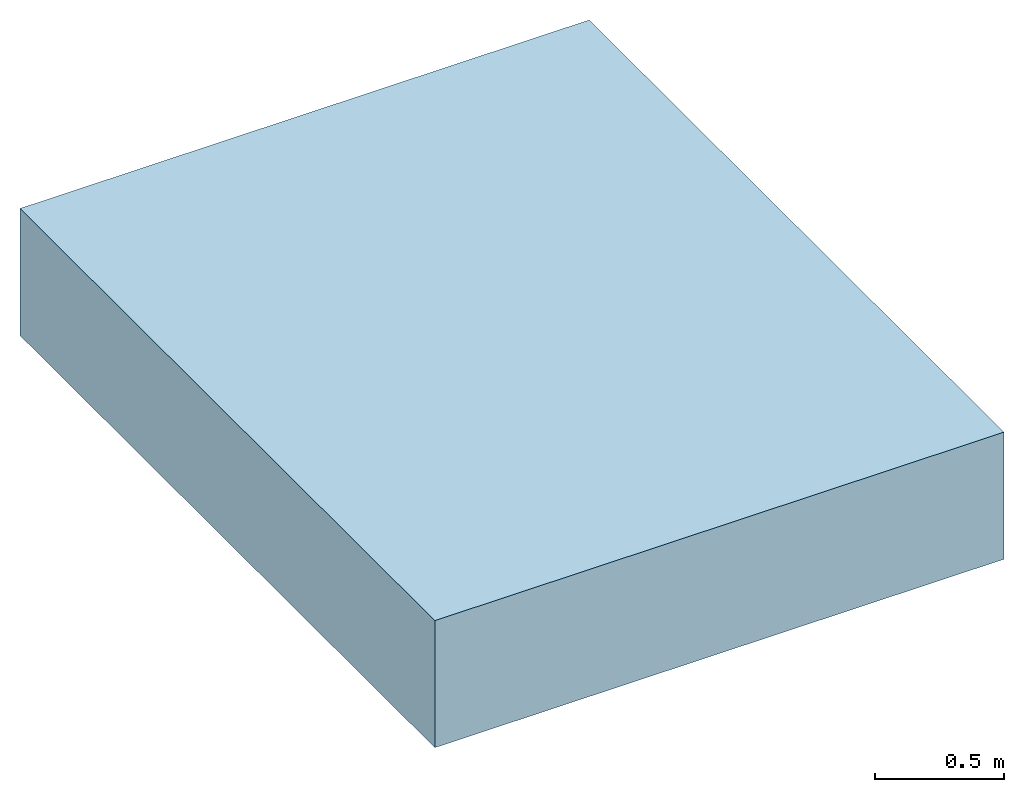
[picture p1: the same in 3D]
Properties of the parts of a building model (IFC2X3), part 2 of 4

# IfcDoor: Door with Sidelight on Side 2 24 (4)
AR_Uks - 001_Nimetus: SISEUKS; 330_Tulekindlus: nõudeid ei esitata; 335_Välispiire: no; 340_Soojusläbivus: 0; 360_Ratastooliga: yes; 910_Tooteinfo: LÄHTUDA TOOTJAFIRMA INFOLEHEST; 915_Kasutus-ja_hooldusjuhend: LÄHTUDA TOOTJAFIRMA INFOLEHEST
Pset_DoorCommon - ThermalTransmittance: 0
AC_Pset_RenovationAndPhasing - Renovation Status: New
Name | In | OverallWidth (mm) | Classification | 315_Avanemine | 310_Materjal | 375_Viimistlus_seest = 376_Viimistlus_väljast | 300_Tüüp = Reference | 305_Ava_mõõt | 320_Klaas | 325_Helipidavus | 345_Päikesekiirgus_tegur | 350_Klaaspakett | 355_Pindala (m2) | 365_Isesulguv = 370_Evakuatsiooniväljapääs | 380_Lukustus | 900_Tootja | 905_Mudel | AcousticRating | GlazingAreaFraction | Manufacturer
SU-28 | Esimene korrus | 2000 | 1.10 IfcDoorStyle (uks) (RKAS BIM + ARCHICAD Classification); 525 Puituksed (V1- EHITUSKULUDE LIIGITAMINE EVS 885:2005) | <315_Avanemine> | PUIT | LENG: HALL, RAL 7045, UKSELEHT: KASESPOON | SU-28 | 2 000x2 300 | 6+6MM, KARASTATUD KLAAS, LAMINEERITUD | 30dB | - | 2X PAKETT | 4.6 | no | SISSEPOOLE LIBLIKLUKUSTUS, VÄLJASPOOLT LUKUSTAV VÕTMEGA. KÄEPIDE ASSA RUKOLINE, L-KUJULINE ÜMARATE KATETEGA LINK, HARJATUD, ROOSTEVABA, OTS TAGASIPÖÖRATUD. HINGED VASTAVALT TOOTJALE. | JELD-WEN | S41 | 30dB | 2.2644 | JELD-WEN/ S41 VÕI ANALOOG
SU-04 | Esimene korrus | 1300 | 1.10 IfcDoorStyle (uks) (RKAS BIM + ARCHICAD Classification); 522 Alumiiniumuksed (V1- EHITUSKULUDE LIIGITAMINE EVS 885:2005) | AKTIIVNE UKSELEHT PAREMAKÄELINE ; ARCHICAD tüüp: Side Hung | ALUMIINIUM | LENG JA RAAMID: PULBERVÄRVITUD, TOON: HALL, RAL 7045 | SU-04 | 1 300x2 300 | ÜHEKORDNE PAKETT | - | Undefined | KARASTATUD KLAAS, LAMINEERITUD | 2.99 | yes | VARUSTADA SOLENOIDMOOTORLUKUGA (VT. NÕRKVOOL). MÕLEMALE POOLE AKTIIVSELE UKSELEHELE LIBLIKLUKUSTUS. KÄEPIDE ASSA RUKOLINE, L-KUJULINE ÜMARATE KATETEGA LINK, HARJATUD, ROOSTEVABA, OTS TAGASIPÖÖRDEGA. HINGED VASTAVALT TOOTJALE. UKSETÕKIS TOOTEKESKNE (UKSESULGURIS). UKSESULGUR VT LUKUSTUSPROJEKT. | SCHÜCO | AWS/ADS 50.NI |  | 2.12765 | SCHÜCO
SU-29 | Teine korrus | 2424.05 | 1.10 IfcDoorStyle (uks) (RKAS BIM + ARCHICAD Classification); 525 Puituksed (V1- EHITUSKULUDE LIIGITAMINE EVS 885:2005) | PAREMAKÄE UKS; ARCHICAD tüüp: Side Hung | PUIT | LENG: HALL, RAL 7045, UKSELEHT: KASESPOON | SU-29 | 2 424x2 300 | 6+6MM, KARASTATUD KLAAS, LAMINEERITUD | 30dB | - | 2X PAKETT | 5.57532 | no | SISSEPOOLE LIBLIKLUKUSTUS, VÄLJASPOOLT LUKUSTAV VÕTMEGA. KÄEPIDE ASSA RUKOLINE, L-KUJULINE ÜMARATE KATETEGA LINK, HARJATUD, ROOSTEVABA, OTS TAGASIPÖÖRATUD. HINGED VASTAVALT TOOTJALE. | JELD-WEN | S41 | 30dB | 3.20579 | JELD-WEN/ S41 VÕI ANALOOG
SU-29 | Teine korrus | 2434.05 | 1.10 IfcDoorStyle (uks) (RKAS BIM + ARCHICAD Classification); 525 Puituksed (V1- EHITUSKULUDE LIIGITAMINE EVS 885:2005) | PAREMAKÄE UKS; ARCHICAD tüüp: Side Hung | PUIT | LENG: HALL, RAL 7045, UKSELEHT: KASESPOON | SU-29 | 2 434x2 300 | 6+6MM, KARASTATUD KLAAS, LAMINEERITUD | 30dB | - | 2X PAKETT | 5.59832 | no | SISSEPOOLE LIBLIKLUKUSTUS, VÄLJASPOOLT LUKUSTAV VÕTMEGA. KÄEPIDE ASSA RUKOLINE, L-KUJULINE ÜMARATE KATETEGA LINK, HARJATUD, ROOSTEVABA, OTS TAGASIPÖÖRATUD. HINGED VASTAVALT TOOTJALE. | JELD-WEN | S41 | 30dB | 3.22799 | JELD-WEN/ S41 VÕI ANALOOG

# IfcDoor: Door with Sidelight on Side 2 24 (6)
Type - OperationType: SINGLE_SWING_RIGHT; ParameterTakesPrecedence: no; Sizeable: no
Type - Door Panel Properties - Panel 1 - PanelDepth: 40 mm; PanelOperation: SWINGING; PanelWidth: 1; PanelPosition: MIDDLE
OverallHeight: 2300 mm
AR_Uks - 001_Nimetus: SISEUKS; 330_Tulekindlus: nõudeid ei esitata; 335_Välispiire: no; 340_Soojusläbivus: 0; 910_Tooteinfo: LÄHTUDA TOOTJAFIRMA INFOLEHEST; 915_Kasutus-ja_hooldusjuhend: LÄHTUDA TOOTJAFIRMA INFOLEHEST
Pset_DoorCommon - ThermalTransmittance: 0
AC_Pset_RenovationAndPhasing - Renovation Status: New
Name | In | OverallWidth (mm) | Classification | 315_Avanemine | 310_Materjal | 375_Viimistlus_seest = 376_Viimistlus_väljast | 300_Tüüp = Reference | 305_Ava_mõõt | 320_Klaas | 325_Helipidavus | 345_Päikesekiirgus_tegur | 350_Klaaspakett | 355_Pindala (m2) | 360_Ratastooliga | 365_Isesulguv | 370_Evakuatsiooniväljapääs | 380_Lukustus | 900_Tootja | 905_Mudel | GlazingAreaFraction | Manufacturer
2 x SU-27 | Esimene korrus | 1500 | 1.10 IfcDoorStyle (uks) (RKAS BIM + ARCHICAD Classification); 525 Puituksed (V1- EHITUSKULUDE LIIGITAMINE EVS 885:2005) | <315_Avanemine> | PUIT | LENG: HALL, RAL 7045, UKSELEHT: KASESPOON | SU-27 | 1 500x2 300 | 6+6MM, KARASTATUD KLAAS, LAMINEERITUD | 30dB | - | 2X PAKETT | 3.45 | yes | no | no | SISSEPOOLE LIBLIKLUKUSTUS, VÄLJASPOOLT LUKUSTAV VÕTMEGA. KÄEPIDE ASSA RUKOLINE, L-KUJULINE ÜMARATE KATETEGA LINK, HARJATUD, ROOSTEVABA, OTS TAGASIPÖÖRATUD. HINGED VASTAVALT TOOTJALE. | JELD-WEN | S41 | 1.1544 | JELD-WEN/ S41 VÕI ANALOOG | Pset_DoorCommon - AcousticRating: 30dB
SU-05 | Esimene korrus | 1200 | 1.10 IfcDoorStyle (uks) (RKAS BIM + ARCHICAD Classification); 522 Alumiiniumuksed (V1- EHITUSKULUDE LIIGITAMINE EVS 885:2005) | <315_Avanemine> | ALUMIINIUM | LENG JA RAAMID: PULBERVÄRVITUD, TOON: HALL, RAL 7045 | SU-05 | 1 200x2 300 | ÜHEKORDNE PAKETT | - | Undefined | KARASTATUD KLAAS, LAMINEERITUD | 2.76 | yes | yes | yes | MITTELUKUSTATAV. KÄEPIDE ON DIAMANTEK OLD SF 2200 MM, HARJATUD, ROOSTEVABA. UKSETÕKIS TOOTEKESKNE (UKSESULGURIS). UKSESULGUR VT LUKUSTUSPROJEKT. HINGED VASTAVALT TOOTJALE. | SCHÜCO | AWS/ADS 50.NI | 1.90565 | SCHÜCO
SU-31 | Teine korrus | 1300 | 1.10 IfcDoorStyle (uks) (RKAS BIM + ARCHICAD Classification); 525 Puituksed (V1- EHITUSKULUDE LIIGITAMINE EVS 885:2005) | VASAKUKÄE UKS; ARCHICAD tüüp: Side Hung | PUIT | LENG: HALL, RAL 7045, UKSELEHT: KASESPOON | SU-31 | 1 300x2 300 | 2X PAKETT | - | Undefined | 6+6MM, KARASTATUD KLAAS, LAMINEERITUD | 2.99 | no | no | yes | VARUSTADA SOLENOIDMOOTORLUKUGA (VT. NÕRKVOOL). MÕLEMALE POOLE AKTIIVSELE UKSELEHELE LIBLIKLUKUSTUS. KÄEPIDE ASSA RUKOLINE, L-KUJULINE ÜMARATE KATETEGA LINK, HARJATUD, ROOSTEVABA, OTS TAGASIPÖÖRDEGA. HINGED VASTAVALT TOOTJALE. UKSETÕKIS TOOTEKESKNE (UKSESULGURIS). UKSESULGUR VT LUKUSTUSPROJEKT. | JELD-WEN | 40D | 2.12765 | JELD-WEN/ 40D VÕI ANALOOG
SU-07 | Teine korrus | 1300 | 1.10 IfcDoorStyle (uks) (RKAS BIM + ARCHICAD Classification); 522 Alumiiniumuksed (V1- EHITUSKULUDE LIIGITAMINE EVS 885:2005) | AKTIIVNE UKSELEHT PAREMAKÄELINE ; ARCHICAD tüüp: Side Hung | ALUMIINIUM | LENG JA RAAMID: PULBERVÄRVITUD, TOON: HALL, RAL 7045 | SU-07 | 1 300x2 300 | ÜHEKORDNE PAKETT | - | Undefined | KARASTATUD KLAAS, LAMINEERITUD | 2.99 | no | no | yes | MITTELUKUSTATAV. KÄEPIDE ON ASSA RUKOLINE, L-KUJULINE ÜMARATE KATETEGA LINK, HARJATUD, ROOSTEVABA, OTS TAGASIPÖÖRATUD. HINGED VASTAVALT TOOTJALE (SCHÜCO). UKSETÕKIS TOOTEKESKNE (UKSESULGURIS). UKSESULGUR VT LUKUSTUSPROJEKT. | SCHÜCO | AWS/ADS 50.NI | 2.12765
SU-08 | Teine korrus | 1300 | 1.10 IfcDoorStyle (uks) (RKAS BIM + ARCHICAD Classification); 522 Alumiiniumuksed (V1- EHITUSKULUDE LIIGITAMINE EVS 885:2005) | VASAKUKÄE UKS; ARCHICAD tüüp: Side Hung | ALUMIINIUM | LENG JA RAAMID: PULBERVÄRVITUD, TOON: HALL, RAL 7045 | SU-08 | 1 300x2 300 | ÜHEKORDNE PAKETT | - | Undefined | KARASTATUD KLAAS, LAMINEERITUD | 2.99 | no | no | yes | VARUSTADA SOLENOIDMOOTORLUKUGA (VT. NÕRKVOOL). MÕLEMALE POOLE AKTIIVSELE UKSELEHELE LIBLIKLUKUSTUS. KÄEPIDE ASSA RUKOLINE, L-KUJULINE ÜMARATE KATETEGA LINK, HARJATUD, ROOSTEVABA, OTS TAGASIPÖÖRDEGA. HINGED VASTAVALT TOOTJALE. UKSETÕKIS TOOTEKESKNE (UKSESULGURIS). UKSESULGUR VT LUKUSTUSPROJEKT. | SCHÜCO | AWS/ADS 50.NI | 2.12765

# IfcDoor: Door with Sidelight on Side 2 and Transom 24, VU-02
In: Esimene korrus
Type - OperationType: SINGLE_SWING_RIGHT; ParameterTakesPrecedence: no; Sizeable: no
Type - Door Panel Properties - Panel 1 - PanelDepth: 40 mm; PanelOperation: SWINGING; PanelWidth: 1; PanelPosition: MIDDLE
OverallHeight: 2800 mm; OverallWidth: 1200 mm; Classification: 1.10 IfcDoorStyle (uks) (RKAS BIM + ARCHICAD Classification); 432 Alumiiniumuksed ja -väravad (V1- EHITUSKULUDE LIIGITAMINE EVS 885:2005)
Avatäited - 06 Soojusläbivus: U≤1,0 W/m²K
AR_Uks - 300_Tüüp: VU-02; 001_Nimetus: VÄLISUKS; 310_Materjal: ALUMIINIUM; 375_Viimistlus_seest: PULBERVÄRVITUD, TUMEHALL, RAL 7016; 376_Viimistlus_väljast: PULBERVÄRVITUD, TUMEHALL, RAL 7016; 305_Ava_mõõt: 1 200x2 800; 315_Avanemine: Väljapoole, vasak ; ARCHICAD tüüp: Side Hung; 320_Klaas: 2X KLAASPAKETT, PAKETI VAHELIISTU TOON: TUMEHALL, RAL 7016; 325_Helipidavus: 30dB; 330_Tulekindlus: EI30; 335_Välispiire: yes; 340_Soojusläbivus: 0; 345_Päikesekiirgus_tegur: g=0,38, VALGUSE LÄBIPAISTVUS 63%; 350_Klaaspakett: 2K SUNGUARD 6KarSel+16CF-14RST; 355_Pindala: 3.36 m2; 360_Ratastooliga: yes; 365_Isesulguv: yes; 370_Evakuatsiooniväljapääs: yes; 380_Lukustus: VARUSTADA MOOTORELEKTRILUKUGA (VT. NÕRKVOOLU PROJEKTI). VÄLJASPOOLT LUKUSTAV VÕTMEGA. SISSEPOOLE AKTIIVSELE UKSELEHELE LIBLIKLUKUSTUS, PASSIIVSELE SERVARIIV. LUKUKORPUS VASTAVALT LUKUSTUSPROJEKTILE. KÕIK LUKUD PEAVAD OLEMA SARJASTATAVAD. KÄEPIDE ON DIAMANTEK OLD SF 2200 MM, HARJATUD, ROOSTEVABA. LISADA RAAMISISENE ASENDIANDUR.; 900_Tootja: SCHÜCO; 905_Mudel: ADS 80 FR 30; 910_Tooteinfo: LÄHTUDA TOOTJAFIRMA INFOLEHEST; 915_Kasutus-ja_hooldusjuhend: LÄHTUDA TOOTJAFIRMA INFOLEHEST. TURVAMÄRGISTUS 1500MM KÕRGUSEL.
Pset_DoorCommon - Reference: VU-02; ThermalTransmittance: 0; GlazingAreaFraction: 2.34381; IsExternal: yes
AC_Pset_RenovationAndPhasing - Renovation Status: New

# IfcDoor: Door with Transom 24 (2)
In: Esimene korrus
Type - OperationType: SINGLE_SWING_LEFT; ParameterTakesPrecedence: no; Sizeable: no
Type - Door Lining Properties - LiningDepth: 115 mm; LiningThickness: 40 mm; TransomThickness: 40 mm; TransomOffset: 2300 mm; LiningOffset: 0 mm
Type - Door Panel Properties - Panel 1 - PanelDepth: 40 mm; PanelOperation: SWINGING; PanelWidth: 1; PanelPosition: MIDDLE
OverallHeight: 2800 mm; OverallWidth: 900 mm; Classification: 1.10 IfcDoorStyle (uks) (RKAS BIM + ARCHICAD Classification); 432 Alumiiniumuksed ja -väravad (V1- EHITUSKULUDE LIIGITAMINE EVS 885:2005)
Avatäited - 06 Soojusläbivus: U≤1,0 W/m²K
AR_Uks - 310_Materjal: TERAS; 375_Viimistlus_seest: PULBERVÄRVITUD, TUMEHALL, RAL 7016; 376_Viimistlus_väljast: PULBERVÄRVITUD, TUMEHALL, RAL 7016; 001_Nimetus: VÄLISUKS; 300_Tüüp: VU-03; 305_Ava_mõõt: 900x2 800; 315_Avanemine: Väljapoole, parem ; ARCHICAD tüüp: Side Hung; 320_Klaas: -; 325_Helipidavus: 30dB; 330_Tulekindlus: nõudeid ei esitata; 335_Välispiire: yes; 340_Soojusläbivus: 0; 345_Päikesekiirgus_tegur: -; 350_Klaaspakett: -; 355_Pindala: 2.52 m2; 360_Ratastooliga: yes; 365_Isesulguv: yes; 370_Evakuatsiooniväljapääs: no; 380_Lukustus: VARUSTADA MOOTORELEKTRILUKUGA (VT. NÕRKVOOLU PROJEKTI). MÕLEMALTPOOLT LUKUSTATAV VÕTMEGA. LUKUKORPUS VASTAVALT LUKUSTUSPROJEKTILE. KÕIK LUKUD PEAVAD OLEMA SARJASTATAVAD. KÄEPIDE ASSA RUKOLINE, L-KUJULINE ÜMARATE KATETEGA LINK, HARJATUD, ROOSTEVABA, ÄRAPÖÖRATUD OTSAGA. LISADA RAAMISISENE ASENDIANDUR.; 900_Tootja: SAKU METALL; 905_Mudel: -; 910_Tooteinfo: LÄHTUDA TOOTJAFIRMA INFOLEHEST; 915_Kasutus-ja_hooldusjuhend: LÄHTUDA TOOTJAFIRMA INFOLEHEST
Pset_DoorCommon - Reference: VU-03; ThermalTransmittance: 0; GlazingAreaFraction: 0.3444; IsExternal: yes
AC_Pset_RenovationAndPhasing - Renovation Status: New

# IfcDoor: Door with Transom 24, VU-03
In: Esimene korrus
Type - OperationType: SINGLE_SWING_RIGHT; ParameterTakesPrecedence: no; Sizeable: no
Type - Door Lining Properties - LiningDepth: 115 mm; LiningThickness: 40 mm; TransomThickness: 40 mm; TransomOffset: 2300 mm; LiningOffset: 250 mm
Type - Door Panel Properties - Panel 1 - PanelDepth: 40 mm; PanelOperation: SWINGING; PanelWidth: 1; PanelPosition: MIDDLE
OverallHeight: 2800 mm; OverallWidth: 900 mm; Classification: 1.10 IfcDoorStyle (uks) (RKAS BIM + ARCHICAD Classification); 432 Alumiiniumuksed ja -väravad (V1- EHITUSKULUDE LIIGITAMINE EVS 885:2005)
Avatäited - 06 Soojusläbivus: U≤1,0 W/m²K
AR_Uks - 310_Materjal: TERAS; 375_Viimistlus_seest: PULBERVÄRVITUD, TUMEHALL, RAL 7016; 376_Viimistlus_väljast: PULBERVÄRVITUD, TUMEHALL, RAL 7016; 001_Nimetus: VÄLISUKS; 300_Tüüp: VU-03; 305_Ava_mõõt: 900x2 800; 315_Avanemine: Väljapoole, parem ; ARCHICAD tüüp: Side Hung; 320_Klaas: -; 325_Helipidavus: 30dB; 330_Tulekindlus: nõudeid ei esitata; 335_Välispiire: yes; 340_Soojusläbivus: 0; 345_Päikesekiirgus_tegur: -; 350_Klaaspakett: -; 355_Pindala: 2.52 m2; 360_Ratastooliga: yes; 365_Isesulguv: yes; 370_Evakuatsiooniväljapääs: no; 380_Lukustus: VARUSTADA MOOTORELEKTRILUKUGA (VT. NÕRKVOOLU PROJEKTI). MÕLEMALTPOOLT LUKUSTATAV VÕTMEGA. LUKUKORPUS VASTAVALT LUKUSTUSPROJEKTILE. KÕIK LUKUD PEAVAD OLEMA SARJASTATAVAD. KÄEPIDE ASSA RUKOLINE, L-KUJULINE ÜMARATE KATETEGA LINK, HARJATUD, ROOSTEVABA, ÄRAPÖÖRATUD OTSAGA. LISADA RAAMISISENE ASENDIANDUR.; 900_Tootja: SAKU METALL; 905_Mudel: -; 910_Tooteinfo: LÄHTUDA TOOTJAFIRMA INFOLEHEST; 915_Kasutus-ja_hooldusjuhend: LÄHTUDA TOOTJAFIRMA INFOLEHEST
Pset_DoorCommon - Reference: VU-03; ThermalTransmittance: 0; GlazingAreaFraction: 0.3444; IsExternal: yes
AC_Pset_RenovationAndPhasing - Renovation Status: New

# IfcDoor: Door with Transom 24, VU-03
In: Esimene korrus
Type - OperationType: SINGLE_SWING_RIGHT; ParameterTakesPrecedence: no; Sizeable: no
Type - Door Lining Properties - LiningDepth: 115 mm; LiningThickness: 40 mm; TransomThickness: 40 mm; TransomOffset: 2300 mm; LiningOffset: 350 mm
Type - Door Panel Properties - Panel 1 - PanelDepth: 40 mm; PanelOperation: SWINGING; PanelWidth: 1; PanelPosition: MIDDLE
OverallHeight: 4200 mm; OverallWidth: 900 mm; Classification: 1.10 IfcDoorStyle (uks) (RKAS BIM + ARCHICAD Classification); 432 Alumiiniumuksed ja -väravad (V1- EHITUSKULUDE LIIGITAMINE EVS 885:2005)
Pset_DoorCommon - Reference: VU-03; ThermalTransmittance: 0; GlazingAreaFraction: 1.4924; IsExternal: yes
AR_Uks - 001_Nimetus: VÄLISUKS; 300_Tüüp: VU-03; 305_Ava_mõõt: 900x4 200; 310_Materjal: MUDELIS: väljast-PULBERVÄRVITUD, TOON: TUMEHALL, RAL 7016; PULBERVÄRVITUD, TOON: TUMEHALL, RAL 7016; seest-PULBERVÄRVITUD, TOON: TUMEHALL, RAL 7016; PULBERVÄRVITUD, TOON: TUMEHALL, RAL 7016; MÄRKUS: TERAS; 315_Avanemine: Väljapoole, parem ; ARCHICAD tüüp: Side Hung; 320_Klaas: -; 325_Helipidavus: 30dB; 330_Tulekindlus: nõudeid ei esitata; 335_Välispiire: yes; 340_Soojusläbivus: 0; 345_Päikesekiirgus_tegur: -; 350_Klaaspakett: -; 355_Pindala: 3.78 m2; 360_Ratastooliga: yes; 365_Isesulguv: yes; 370_Evakuatsiooniväljapääs: no; 375_Viimistlus_seest: MUDELIS: PULBERVÄRVITUD, TOON: TUMEHALL, RAL 7016; PULBERVÄRVITUD, TOON: TUMEHALL, RAL 7016; MÄRKUS: PULBERVÄRVITUD, TOON: TUMEHALL, RAL 7016; 376_Viimistlus_väljast: MUDELIS: PULBERVÄRVITUD, TOON: TUMEHALL, RAL 7016; PULBERVÄRVITUD, TOON: TUMEHALL, RAL 7016; MÄRKUS: PULBERVÄRVITUD, TOON: TUMEHALL, RAL 7016; 380_Lukustus: VARUSTADA MOOTORELEKTRILUKUGA (VT. NÕRKVOOLU PROJEKTI). MÕLEMALTPOOLT LUKUSTATAV VÕTMEGA. LUKUKORPUS VASTAVALT LUKUSTUSPROJEKTILE. KÕIK LUKUD PEAVAD OLEMA SARJASTATAVAD. KÄEPIDE ASSA RUKOLINE, L-KUJULINE ÜMARATE KATETEGA LINK, HARJATUD, ROOSTEVABA, ÄRAPÖÖRATUD OTSAGA. LISADA RAAMISISENE ASENDIANDUR.; 900_Tootja: SAKU METALL; 905_Mudel: -; 910_Tooteinfo: LÄHTUDA TOOTJAFIRMA INFOLEHEST; 915_Kasutus-ja_hooldusjuhend: LÄHTUDA TOOTJAFIRMA INFOLEHEST
AC_Pset_RenovationAndPhasing - Renovation Status: New

# IfcDoor: Doors-Industrial_ASSA-ABLOY-OH1042F-overhead-sectional-door (7)
In: Esimene korrus
Type - ParameterTakesPrecedence: no; Sizeable: no
OverallWidth: 4000 mm; Classification: 1.10 IfcDoorStyle (uks) (RKAS BIM + ARCHICAD Classification); 432 Alumiiniumuksed ja -väravad (V1- EHITUSKULUDE LIIGITAMINE EVS 885:2005)
AR_Uks - 365_Isesulguv: no; 001_Nimetus: GARAAŽIUKS; 310_Materjal: ALUMIINIUM; 315_Avanemine: MOOTORIGA AVATAV JA SULETAV; 320_Klaas: 3x, KARASTATUD, LAMINEERITUD; 325_Helipidavus: 30dB; 330_Tulekindlus: nõudeid ei esitata; 335_Välispiire: yes; 340_Soojusläbivus: 2.2; 360_Ratastooliga: no; 900_Tootja: ASSA-ABLOY; 905_Mudel: OH1042F; 910_Tooteinfo: VASTAVALT TOOTJAFIRMA INFOLEHELE
Pset_DoorCommon - IsExternal: yes
AC_Pset_RenovationAndPhasing - Renovation Status: New
Name | OverallHeight (mm) | 370_Evakuatsiooniväljapääs | 300_Tüüp = Reference | 376_Viimistlus_väljast | 375_Viimistlus_seest | 305_Ava_mõõt | 345_Päikesekiirgus_tegur | 350_Klaaspakett | 355_Pindala (m2) | 380_Lukustus | 915_Kasutus-ja_hooldusjuhend
GU-03 | 2800 | yes | GU-03 | <376_Viimistlus_väljast> | <375_Viimistlus_seest> | 4 000x2 800 | g=0,55; VALGUSE LÄBIPAISTVUS 70% | 6 MM SELEKTIIV + 4 + 6 MM SELEKTIIV / 14mm ChrU | 11.2 | AJAM, MIS VÕIMALDAB UKSELEHE TÕSTE 2,8 M KÕRGUSENI 21 SEKUNDIGA. LUKUSTUS INNER RANGE SEERIA. KÄIGUTEEUKS VARUSTADA SOLENOIDMOOTORLUKUGA (VT. NÕRKVOOLU PROJEKTI). SISSEPOOLE LIBLIKLUKUSTUS, VÄLJASPOOLT LUKUSTATAV VÕTMEGA. KÄEPIDE ON ASSA RUKO-LINE, HARJATUD, ROOSTEVABA. HINGED VASTAVALT TOOTJALE, OTS TAGASIPÖÖRDEGA . KÄIGUTEE UKSETÕKIS TOOTEKESKNE. VARUSTADA | VASTAVALT TOOTJAFIRMA INFOLEHELE. 1-VT. JOONISEID AR-7-07, AR-7-08, AR-7-15 2-IGA VÄRAV KOMPLEKTEERITUD KAHE KAASASKANTAVA PULDIGA (ÜKS MASINAS, TEINE KOMANDOPEALIKU KÄES). SAMAST PULDIST PEAB OLEMA VÕIMALIK GARAAŽI VALVE ALLA PANNA. GARAAŽIUSTE PULT PEAB AVAMA MÕLEMA PIIRDEAIA VÄRAVAD JA VÕIMALDAMA HOONE VALVESTAMIST. 3- LISAKS VÄRAVA AVAMISEKS-SULGEMISEKS STATSIONAARNE LÜLITI GARAAZIVÄRAVA KÕRVAL SEINAL. 4- KÕIKI VÄRAVAID PEAB OLEMA VÕIMALIK VABASTADA AJAMI VEOSÜSTEEMIST JA AVADA-SULGEDA KÄSITSI. PEAB OLEMA KIIRESTI JA ILMA LISAVAHENDITETA KÄSITSI AVATAV. 5- VÄLJAKUTSELE REAGEERIVA PÄÄSTETEHNIKA GARAAŽIVÄRAVATE AVANEMISKIIRUS MINIMAALSELT 21 CM SEKUNDIGA. 6- PESUBOKSI JA REMONDIBOKSI VÄRAVAAJAM PEAB OLEMA VEEJOAKINDEL (IP 65). 7- IGALE VÄRAVALE PAIGALDADA KAHE SIGNAALTULEGA (PUNANE JA ROHELINE) FOOR. ROHELINE SÜTTIB ALLES VÄRAVA TÄIELIKUL AVANEMISEL. FOORI ASUKOHT PEAB OLEMA HÄSTI JÄLGITAV OPERATIIVSÕIDUKI JUHI KOHALT. 8- ARVESTADA ÖÖPÄEVARINGSEKS UKSETSÜKLITE ARVUKS VÄHEMALT 50 9- VÄRAVATEL PEAB OLEMA TURVALISUST TAGAV ÜLESLÜKKAMISKAITSE 10- KÕIGIL PAIGALDATAVATEL VÄRAVATEL ON NÕUTAV TOOTJAPOOLNE ÖÖPÄEVARINGNE TEHNILINE TUGI 11-GARAAŽIUKSES KÄÄNDUKS AVANEB VÄLJAPOOLE
4 x GU-01 | 4400 | no | GU-01 | PULBERVÄRVITUD, TUMEHALL, RAL 7016 | PULBERVÄRVITUD, TUMEHALL, RAL 7016 | 4 000x4 400 | g=0,38, VALGUSE LÄBIPAISTVUS 63% | 6MM SUNGUARD SN70/37 + 4 + 6MM SELEKTIIV / 14MM CHRU | 17.6 | AJAM, MIS VÕIMALDAB UKSELEHE TÕSTE 4,4M KÕRGUSENI 21 SEKUNDIGA. LUKUSTUS INNER RANGE SEERIA. | VASTAVALT TOOTJAFIRMA INFOLEHELE. 1-VT. JOONISEID AR-7-07, AR-7-08, AR-7-15 2-IGA VÄRAV KOMPLEKTEERITUD KAHE KAASASKANTAVA PULDIGA (ÜKS MASINAS, TEINE KOMANDOPEALIKU KÄES). SAMAST PULDIST PEAB OLEMA VÕIMALIK GARAAŽI VALVE ALLA PANNA. GARAAŽIUSTE PULT PEAB AVAMA MÕLEMA PIIRDEAIA VÄRAVAD JA VÕIMALDAMA HOONE VALVESTAMIST. 3- LISAKS VÄRAVA AVAMISEKS-SULGEMISEKS STATSIONAARNE LÜLITI GARAAZIVÄRAVA KÕRVAL SEINAL. 4- KÕIKI VÄRAVAID PEAB OLEMA VÕIMALIK VABASTADA AJAMI VEOSÜSTEEMIST JA AVADA-SULGEDA KÄSITSI. PEAB OLEMA KIIRESTI JA ILMA LISAVAHENDITETA KÄSITSI AVATAV. 5- VÄLJAKUTSELE REAGEERIVA PÄÄSTETEHNIKA GARAAŽIVÄRAVATE AVANEMISKIIRUS MINIMAALSELT 21 CM SEKUNDIGA. 6- PESUBOKSI JA REMONDIBOKSI VÄRAVAAJAM PEAB OLEMA VEEJOAKINDEL (IP 65). 7- IGALE VÄRAVALE PAIGALDADA KAHE SIGNAALTULEGA (PUNANE JA ROHELINE) FOOR. ROHELINE SÜTTIB ALLES VÄRAVA TÄIELIKUL AVANEMISEL. FOORI ASUKOHT PEAB OLEMA HÄSTI JÄLGITAV OPERATIIVSÕIDUKI JUHI KOHALT. 8- ARVESTADA ÖÖPÄEVARINGSEKS UKSETSÜKLITE ARVUKS VÄHEMALT 50 9- VÄRAVATEL PEAB OLEMA TURVALISUST TAGAV ÜLESLÜKKAMISKAITSE 10- KÕIGIL PAIGALDATAVATEL VÄRAVATEL ON NÕUTAV TOOTJAPOOLNE ÖÖPÄEVARINGNE TEHNILINE TUGI.
2 x GU-02 | 4400 | yes | GU-02 | PULBERVÄRVITUD, TUMEHALL, RAL 7016 | PULBERVÄRVITUD, TUMEHALL, RAL 7016 | 4 000x4 400 | g=0,38, VALGUSE LÄBIPAISTVUS 63% | 6MM SUNGUARD SN70/37 + 4 + 6MM SELEKTIIV / 14MM CHRU | 17.6 | AJAM, MIS VÕIMALDAB UKSELEHE TÕSTE 4,4M KÕRGUSENI 21 SEKUNDIGA. LUKUSTUS INNER RANGE SEERIA. KÄIGUTEEUKS VARUSTADA SOLENOIDMOOTORLUKUGA (VT. NÕRKVOOLU PROJEKTI). SISSEPOOLE LIBLIKLUKUSTUS, VÄLJASPOOLT LUKUSTATAV VÕTMEGA. KÄEPIDE ON ASSA RUKO-LINE, HARJATUD, ROOSTEVABA. HINGED VASTAVALT TOOTJALE, OTS TAGASIPÖÖRDEGA . KÄIGUTEE UKSETÕKIS TOOTEKESKNE. VARUSTADA KAABLIÜLEVIIGUGA . | VASTAVALT TOOTJAFIRMA INFOLEHELE. 1-VT. JOONISEID AR-7-07, AR-7-08, AR-7-15 2-IGA VÄRAV KOMPLEKTEERITUD KAHE KAASASKANTAVA PULDIGA (ÜKS MASINAS, TEINE KOMANDOPEALIKU KÄES). SAMAST PULDIST PEAB OLEMA VÕIMALIK GARAAŽI VALVE ALLA PANNA. GARAAŽIUSTE PULT PEAB AVAMA MÕLEMA PIIRDEAIA VÄRAVAD JA VÕIMALDAMA HOONE VALVESTAMIST. 3- LISAKS VÄRAVA AVAMISEKS-SULGEMISEKS STATSIONAARNE LÜLITI GARAAZIVÄRAVA KÕRVAL SEINAL. 4- KÕIKI VÄRAVAID PEAB OLEMA VÕIMALIK VABASTADA AJAMI VEOSÜSTEEMIST JA AVADA-SULGEDA KÄSITSI. PEAB OLEMA KIIRESTI JA ILMA LISAVAHENDITETA KÄSITSI AVATAV. 5- VÄLJAKUTSELE REAGEERIVA PÄÄSTETEHNIKA GARAAŽIVÄRAVATE AVANEMISKIIRUS MINIMAALSELT 21 CM SEKUNDIGA. 6- PESUBOKSI JA REMONDIBOKSI VÄRAVAAJAM PEAB OLEMA VEEJOAKINDEL (IP 65). 7- IGALE VÄRAVALE PAIGALDADA KAHE SIGNAALTULEGA (PUNANE JA ROHELINE) FOOR. ROHELINE SÜTTIB ALLES VÄRAVA TÄIELIKUL AVANEMISEL. FOORI ASUKOHT PEAB OLEMA HÄSTI JÄLGITAV OPERATIIVSÕIDUKI JUHI KOHALT. 8- ARVESTADA ÖÖPÄEVARINGSEKS UKSETSÜKLITE ARVUKS VÄHEMALT 50 9- VÄRAVATEL PEAB OLEMA TURVALISUST TAGAV ÜLESLÜKKAMISKAITSE 10- KÕIGIL PAIGALDATAVATEL VÄRAVATEL ON NÕUTAV TOOTJAPOOLNE ÖÖPÄEVARINGNE TEHNILINE TUGI 11-GARAAŽIUKSES KÄÄNDUKS AVANEB VÄLJAPOOLE

# IfcDoor: Double Door 24, SU-25
In: Teine korrus
Type - OperationType: DOUBLE_DOOR_SINGLE_SWING; ParameterTakesPrecedence: no; Sizeable: no
Type - Door Lining Properties - LiningDepth: 115 mm; LiningThickness: 40 mm; LiningOffset: 190 mm
Type - Door Panel Properties - Panel 1 - PanelDepth: 40 mm; PanelOperation: SWINGING; PanelWidth: 0.512371; PanelPosition: RIGHT
Type - Door Panel Properties - Panel 2 - PanelDepth: 40 mm; PanelOperation: SWINGING; PanelWidth: 0.512371; PanelPosition: LEFT
OverallHeight: 2300 mm; OverallWidth: 1050 mm; Classification: 1.10 IfcDoorStyle (uks) (RKAS BIM + ARCHICAD Classification); 523 Terasuksed (V1- EHITUSKULUDE LIIGITAMINE EVS 885:2005)
AR_Uks - 310_Materjal: TERAS; 375_Viimistlus_seest: LENG: HALL, RAL 7045, UKSELEHT: HALL, RAL 7045; 376_Viimistlus_väljast: LENG: HALL, RAL 7045, UKSELEHT: HALL, RAL 7045; 001_Nimetus: SISEUKS; 300_Tüüp: SU-25; 305_Ava_mõõt: 1 050x2 300; 315_Avanemine: -; ARCHICAD tüüp: Side Hung; 320_Klaas: -; 325_Helipidavus: -; 330_Tulekindlus: nõudeid ei esitata; 335_Välispiire: no; 340_Soojusläbivus: 0; 345_Päikesekiirgus_tegur: Undefined; 350_Klaaspakett: -; 355_Pindala: 2.415 m2; 360_Ratastooliga: no; 365_Isesulguv: no; 370_Evakuatsiooniväljapääs: no; 380_Lukustus: MITTELUKUSTATAV, MAGNETFIKSAATORITEGA. HINGED VASTAVALT TOOTJALE. UKSESULGURINA KASUTADA UKSE VÕI LENGI SISSE SÜVISTATAVAT MUDELIT; 900_Tootja: SAKU METALL; 905_Mudel: -; 910_Tooteinfo: LÄHTUDA TOOTJAFIRMA INFOLEHEST; 915_Kasutus-ja_hooldusjuhend: LÄHTUDA TOOTJAFIRMA INFOLEHEST
Pset_DoorCommon - Reference: SU-25; ThermalTransmittance: 0
AC_Pset_RenovationAndPhasing - Renovation Status: New

# IfcDoor: Double Door 24, SU-25
In: Teine korrus
Type - OperationType: DOUBLE_DOOR_SINGLE_SWING; ParameterTakesPrecedence: no; Sizeable: no
Type - Door Lining Properties - LiningDepth: 115 mm; LiningThickness: 40 mm; LiningOffset: 240 mm
Type - Door Panel Properties - Panel 1 - PanelDepth: 40 mm; PanelOperation: SWINGING; PanelWidth: 0.512371; PanelPosition: RIGHT
Type - Door Panel Properties - Panel 2 - PanelDepth: 40 mm; PanelOperation: SWINGING; PanelWidth: 0.512371; PanelPosition: LEFT
OverallHeight: 2300 mm; OverallWidth: 1050 mm; Classification: 1.10 IfcDoorStyle (uks) (RKAS BIM + ARCHICAD Classification); 523 Terasuksed (V1- EHITUSKULUDE LIIGITAMINE EVS 885:2005)
AR_Uks - 310_Materjal: TERAS; 375_Viimistlus_seest: LENG: HALL, RAL 7045, UKSELEHT: HALL, RAL 7045; 376_Viimistlus_väljast: LENG: HALL, RAL 7045, UKSELEHT: HALL, RAL 7045; 001_Nimetus: SISEUKS; 300_Tüüp: SU-25; 305_Ava_mõõt: 1 050x2 300; 315_Avanemine: -; ARCHICAD tüüp: Side Hung; 320_Klaas: -; 325_Helipidavus: -; 330_Tulekindlus: nõudeid ei esitata; 335_Välispiire: no; 340_Soojusläbivus: 0; 345_Päikesekiirgus_tegur: Undefined; 350_Klaaspakett: -; 355_Pindala: 2.415 m2; 360_Ratastooliga: no; 365_Isesulguv: no; 370_Evakuatsiooniväljapääs: no; 380_Lukustus: MITTELUKUSTATAV, MAGNETFIKSAATORITEGA. HINGED VASTAVALT TOOTJALE. UKSESULGURINA KASUTADA UKSE VÕI LENGI SISSE SÜVISTATAVAT MUDELIT; 900_Tootja: SAKU METALL; 905_Mudel: -; 910_Tooteinfo: LÄHTUDA TOOTJAFIRMA INFOLEHEST; 915_Kasutus-ja_hooldusjuhend: LÄHTUDA TOOTJAFIRMA INFOLEHEST
Pset_DoorCommon - Reference: SU-25; ThermalTransmittance: 0
AC_Pset_RenovationAndPhasing - Renovation Status: New

# IfcDoor: Double Door 24, SU-01
In: Esimene korrus
Type - OperationType: DOUBLE_DOOR_SINGLE_SWING; ParameterTakesPrecedence: no; Sizeable: no
Type - Door Lining Properties - LiningDepth: 115 mm; LiningThickness: 40 mm; ThresholdDepth: 75 mm; ThresholdThickness: 12 mm; LiningOffset: 0 mm; ThresholdOffset: 40 mm
Type - Door Panel Properties - Panel 1 - PanelDepth: 40 mm; PanelOperation: SWINGING; PanelWidth: 0.506977; PanelPosition: RIGHT
Type - Door Panel Properties - Panel 2 - PanelDepth: 40 mm; PanelOperation: SWINGING; PanelWidth: 0.506977; PanelPosition: LEFT
OverallHeight: 2300 mm; OverallWidth: 1800 mm; Classification: 1.10 IfcDoorStyle (uks) (RKAS BIM + ARCHICAD Classification); 522 Alumiiniumuksed (V1- EHITUSKULUDE LIIGITAMINE EVS 885:2005)
Pset_ManufacturerTypeInformation - Manufacturer: SCHÜCO
AR_Uks - 365_Isesulguv: yes; 310_Materjal: ALUMIINIUM; 315_Avanemine: VÄLJAPOOLE AVANEV, AKTIIVNE UKSELEHT PAREMAKÄELINE; 375_Viimistlus_seest: LENG JA RAAMID: PULBERVÄRVITUD, TOON: HALL, RAL 7045; 376_Viimistlus_väljast: LENG JA RAAMID: PULBERVÄRVITUD, TOON: HALL, RAL 7045; 001_Nimetus: SISEMINE TUULEKOJA UKS; 300_Tüüp: SU-01; 305_Ava_mõõt: 1 800x2 300; 320_Klaas: ÜHEKORDNE PAKETT; 325_Helipidavus: -; 330_Tulekindlus: nõudeid ei esitata; 335_Välispiire: no; 340_Soojusläbivus: 0; 345_Päikesekiirgus_tegur: -; 350_Klaaspakett: KARASTATUD KLAAS, LAMINEERITUD; 355_Pindala: 4.14 m2; 360_Ratastooliga: yes; 370_Evakuatsiooniväljapääs: yes; 380_Lukustus: AKTIIVNE UKSELEHT MITTELUKUSTATAV, PASSIIVSELE SERVARIIV. KÄEPIDE DIAMANTEK OLD SF 2200 MM, HARJATUD, ROOSTEVABA. HINGED VASTAVALT TOOTJALE. UKSETÕKIS TOOTEKESKNE (UKSESULGURIS). UKSESULGUR MÕLEMAL UKSELEHEL VT LUKUSTUSPROJEKT; 900_Tootja: SCHÜCO; 905_Mudel: AWS/ADS 50.NI; 910_Tooteinfo: LÄHTUDA TOOTJAFIRMA INFOLEHEST; 915_Kasutus-ja_hooldusjuhend: LÄHTUDA TOOTJAFIRMA INFOLEHEST
Pset_DoorCommon - Reference: SU-01; ThermalTransmittance: 0; GlazingAreaFraction: 2.78477; IsExternal: no
AC_Pset_RenovationAndPhasing - Renovation Status: New

# IfcDoor: Double Door 24, SU-02*
In: Esimene korrus
Type - OperationType: DOUBLE_DOOR_SINGLE_SWING; ParameterTakesPrecedence: no; Sizeable: no
Type - Door Lining Properties - LiningDepth: 115 mm; LiningThickness: 40 mm; ThresholdDepth: 75 mm; ThresholdThickness: 12 mm; LiningOffset: 190 mm; ThresholdOffset: 230 mm
Type - Door Panel Properties - Panel 1 - PanelDepth: 40 mm; PanelOperation: SWINGING; PanelWidth: 0.506977; PanelPosition: RIGHT
Type - Door Panel Properties - Panel 2 - PanelDepth: 40 mm; PanelOperation: SWINGING; PanelWidth: 0.506977; PanelPosition: LEFT
OverallHeight: 2300 mm; OverallWidth: 1800 mm; Classification: 1.10 IfcDoorStyle (uks) (RKAS BIM + ARCHICAD Classification); 522 Alumiiniumuksed (V1- EHITUSKULUDE LIIGITAMINE EVS 885:2005)
AR_Uks - 315_Avanemine: VÄLJAPOOLE AVANEV, AKTIIVNE UKSELEHT PAREMAKÄELINE; 310_Materjal: ALUMIINIUM; 375_Viimistlus_seest: LENG JA RAAMID: PULBERVÄRVITUD, TOON: HALL, RAL 7045; 376_Viimistlus_väljast: LENG JA RAAMID: PULBERVÄRVITUD, TOON: HALL, RAL 7045; 001_Nimetus: SISEUKS; 300_Tüüp: SU-02*; 305_Ava_mõõt: 1 800x2 300; 320_Klaas: ÜHEKORDNE PAKETT; 325_Helipidavus: -; 330_Tulekindlus: EI30; 335_Välispiire: no; 340_Soojusläbivus: 0; 345_Päikesekiirgus_tegur: Undefined; 350_Klaaspakett: KARASTATUD KLAAS, LAMINEERITUD; 355_Pindala: 4.14 m2; 360_Ratastooliga: yes; 365_Isesulguv: no; 370_Evakuatsiooniväljapääs: yes; 380_Lukustus: VARUSTADA SOLENOIDMOOTORLUKUGA (VT. NÕRKVOOLU PROJEKTI). SISSEPOOLE (GARAAŽI POOLE) LIBLIKLUKUSTUS, VÄLJASPOOLT LUKUSTATAV VÕTMEGA, PASSIIVSELE UKSELEHELE SERVARIIV. KÄEPIDE ASSA RUKOLINE, L-KUJULINE ÜMARATE KATETEGA LINK, HARJATUD, ROOSTEVABA, OTS TAGASIPÖÖRDEGA. HINGED VASTAVALT TOOTJALE.; 900_Tootja: SCHÜCO; 905_Mudel: ADS 80 FR 30; 910_Tooteinfo: LÄHTUDA TOOTJAFIRMA INFOLEHEST; 915_Kasutus-ja_hooldusjuhend: LÄHTUDA TOOTJAFIRMA INFOLEHEST
Pset_ManufacturerTypeInformation - Manufacturer: SCHÜCO
Pset_FireRatingProperties - FireResistanceRating: EI-30
Pset_DoorCommon - FireRating: EI-30; Reference: SU-02*; ThermalTransmittance: 0; GlazingAreaFraction: 2.78477; IsExternal: no
AC_Pset_RenovationAndPhasing - Renovation Status: New

# IfcDoor: Double Door 24, SU-22*
In: Teine korrus
Type - OperationType: DOUBLE_DOOR_SINGLE_SWING; ParameterTakesPrecedence: no; Sizeable: no
Type - Door Lining Properties - LiningThickness: 40 mm; ThresholdDepth: 100 mm; ThresholdThickness: 12 mm; LiningOffset: 0 mm; ThresholdOffset: 40 mm
Type - Door Panel Properties - Panel 1 - PanelDepth: 40 mm; PanelOperation: SWINGING; PanelWidth: 0.796721; PanelPosition: LEFT
Type - Door Panel Properties - Panel 2 - PanelDepth: 40 mm; PanelOperation: SWINGING; PanelWidth: 0.222951; PanelPosition: RIGHT
OverallHeight: 2300 mm; OverallWidth: 1300 mm; Classification: 1.10 IfcDoorStyle (uks) (RKAS BIM + ARCHICAD Classification); 523 Terasuksed (V1- EHITUSKULUDE LIIGITAMINE EVS 885:2005)
AR_Uks - 310_Materjal: TERAS; 375_Viimistlus_seest: LENG: HALL, RAL 7045, UKSELEHT: HALL, RAL 7045; 376_Viimistlus_väljast: LENG: HALL, RAL 7045, UKSELEHT: HALL, RAL 7045; 001_Nimetus: SISEUKS; 300_Tüüp: SU-22*; 305_Ava_mõõt: 1 300x2 300; 315_Avanemine: Undefined - Vasak ; ARCHICAD tüüp: Side Hung; 320_Klaas: -; 325_Helipidavus: -; 330_Tulekindlus: EI30; 335_Välispiire: no; 340_Soojusläbivus: 0; 345_Päikesekiirgus_tegur: Undefined; 350_Klaaspakett: -; 355_Pindala: 2.99 m2; 360_Ratastooliga: no; 365_Isesulguv: no; 370_Evakuatsiooniväljapääs: yes; 380_Lukustus: VARUSTADA SOLENOIDMOOTORLUKUGA (VT. NÕRKVOOLU PROJEKTI). SISSEPOOLE LIBLIKLUKUSTUS, TREPIKOJA, KORIDORI POOLT LUKUSTAV VÕTMEGA. KÄEPIDE ASSA RUKOLINE, L-KUJULINE ÜMARATE KATETEGA LINK, HARJATUD, ROOSTEVABA, OTS TAGASIPÖÖRDEGA. HINGED VASTAVALT TOOTJALE.; 900_Tootja: SAKU METALL; 905_Mudel: -; 910_Tooteinfo: LÄHTUDA TOOTJAFIRMA INFOLEHEST; 915_Kasutus-ja_hooldusjuhend: LÄHTUDA TOOTJAFIRMA INFOLEHEST
Pset_DoorCommon - Reference: SU-22*; FireRating: EI-30/Sa; ThermalTransmittance: 0
Pset_FireRatingProperties - FireResistanceRating: EI-30/Sa
Pset_ManufacturerTypeInformation - Manufacturer: SAKU METALL VÕI ANALOOG
AC_Pset_RenovationAndPhasing - Renovation Status: New

# IfcDoor: Double Door 24, SU-21*
In: Teine korrus
Type - OperationType: DOUBLE_DOOR_SINGLE_SWING; ParameterTakesPrecedence: no; Sizeable: no
Type - Door Lining Properties - LiningThickness: 40 mm; ThresholdDepth: 100 mm; ThresholdThickness: 12 mm; LiningOffset: 140 mm; ThresholdOffset: 180 mm
Type - Door Panel Properties - Panel 1 - PanelDepth: 40 mm; PanelOperation: SWINGING; PanelWidth: 0.796721; PanelPosition: RIGHT
Type - Door Panel Properties - Panel 2 - PanelDepth: 40 mm; PanelOperation: SWINGING; PanelWidth: 0.222951; PanelPosition: LEFT
OverallHeight: 2300 mm; OverallWidth: 1300 mm; Classification: 1.10 IfcDoorStyle (uks) (RKAS BIM + ARCHICAD Classification); 523 Terasuksed (V1- EHITUSKULUDE LIIGITAMINE EVS 885:2005)
AR_Uks - 310_Materjal: TERAS; 375_Viimistlus_seest: LENG: HALL, RAL 7045, UKSELEHT: HALL, RAL 7045; 376_Viimistlus_väljast: LENG: HALL, RAL 7045, UKSELEHT: HALL, RAL 7045; 001_Nimetus: SISEUKS; 300_Tüüp: SU-21*; 305_Ava_mõõt: 1 300x2 300; 315_Avanemine: PAREMKÄE UKS ; ARCHICAD tüüp: Side Hung; 320_Klaas: -; 325_Helipidavus: -; 330_Tulekindlus: EI30; 335_Välispiire: no; 340_Soojusläbivus: 0; 345_Päikesekiirgus_tegur: Undefined; 350_Klaaspakett: -; 355_Pindala: 2.99 m2; 360_Ratastooliga: no; 365_Isesulguv: no; 370_Evakuatsiooniväljapääs: yes; 380_Lukustus: VARUSTADA SOLENOIDMOOTORLUKUGA (VT. NÕRKVOOLU PROJEKTI). SISSEPOOLE LIBLIKLUKUSTUS, TREPIKOJA, KORIDORI POOLT LUKUSTAV VÕTMEGA. KÄEPIDE ASSA RUKOLINE, L-KUJULINE ÜMARATE KATETEGA LINK, HARJATUD, ROOSTEVABA, OTS TAGASIPÖÖRDEGA. HINGED VASTAVALT TOOTJALE.; 900_Tootja: SAKU METALL; 905_Mudel: -; 910_Tooteinfo: LÄHTUDA TOOTJAFIRMA INFOLEHEST; 915_Kasutus-ja_hooldusjuhend: LÄHTUDA TOOTJAFIRMA INFOLEHEST
Pset_DoorCommon - Reference: SU-21*; FireRating: EI-30/Sa; ThermalTransmittance: 0
Pset_FireRatingProperties - FireResistanceRating: EI-30/Sa
Pset_ManufacturerTypeInformation - Manufacturer: SAKU METALL VÕI ANALOOG
AC_Pset_RenovationAndPhasing - Renovation Status: New

# IfcDoor: Double Door 24, SU-03
In: Esimene korrus
Type - OperationType: DOUBLE_DOOR_SINGLE_SWING; ParameterTakesPrecedence: no; Sizeable: no
Type - Door Lining Properties - LiningThickness: 40 mm; ThresholdDepth: 150 mm; ThresholdThickness: 12 mm; LiningOffset: 0 mm; ThresholdOffset: 0 mm
Type - Door Panel Properties - Panel 1 - PanelDepth: 40 mm; PanelOperation: SWINGING; PanelWidth: 0.506593; PanelPosition: RIGHT
Type - Door Panel Properties - Panel 2 - PanelDepth: 40 mm; PanelOperation: SWINGING; PanelWidth: 0.506593; PanelPosition: LEFT
OverallHeight: 2300 mm; OverallWidth: 1900 mm; Classification: 1.10 IfcDoorStyle (uks) (RKAS BIM + ARCHICAD Classification); 522 Alumiiniumuksed (V1- EHITUSKULUDE LIIGITAMINE EVS 885:2005)
AR_Uks - 310_Materjal: ALUMIINIUM; 375_Viimistlus_seest: LENG JA RAAMID: PULBERVÄRVITUD, TOON: HALL, RAL 7045; 376_Viimistlus_väljast: LENG JA RAAMID: PULBERVÄRVITUD, TOON: HALL, RAL 7045; 001_Nimetus: SISEUKS; 300_Tüüp: SU-03; 305_Ava_mõõt: 1 900x2 300; 315_Avanemine: AKTIIVNE UKSELEHT PAREMAKÄELINE ; ARCHICAD tüüp: Side Hung; 320_Klaas: ÜHEKORDNE PAKETT; 325_Helipidavus: 30dB; 330_Tulekindlus: nõudeid ei esitata; 335_Välispiire: no; 340_Soojusläbivus: 0; 345_Päikesekiirgus_tegur: Undefined; 350_Klaaspakett: KARASTATUD KLAAS, LAMINEERITUD; 355_Pindala: 4.37 m2; 360_Ratastooliga: yes; 365_Isesulguv: no; 370_Evakuatsiooniväljapääs: yes; 380_Lukustus: VARUSTADA SOLENOIDMOOTORLUKUGA FUAJEE POOLE (VT. NÕRKVOOLU PROJEKTI). SISSEPOOLE LIBLIKLUKUSTUS, VÄLJASPOOLT LUKUSTATAV VÕTMEGA, PASSIIVSELE UKSELEHELE SERVARIIV. KÄEPIDE ASSA RUKOLINE, L-KUJULINE ÜMARATE KATETEGA LINK, HARJATUD, ROOSTEVABA, OTS TAGASIPÖÖRDEGA. HINGED VASTAVALT TOOTJALE.; 900_Tootja: SCHÜCO; 905_Mudel: AWS/ADS 50.NI; 910_Tooteinfo: LÄHTUDA TOOTJAFIRMA INFOLEHEST; 915_Kasutus-ja_hooldusjuhend: LÄHTUDA TOOTJAFIRMA INFOLEHEST
Pset_ManufacturerTypeInformation - Manufacturer: SCHÜCO
Pset_DoorCommon - Reference: SU-03; AcousticRating: 30dB; ThermalTransmittance: 0; GlazingAreaFraction: 2.99197
AC_Pset_RenovationAndPhasing - Renovation Status: New

# IfcDoor: Double Door 24, SU-24*
In: Teine korrus
Type - OperationType: DOUBLE_DOOR_SINGLE_SWING; ParameterTakesPrecedence: no; Sizeable: no
Type - Door Lining Properties - LiningThickness: 40 mm; ThresholdDepth: 150 mm; ThresholdThickness: 12 mm; LiningOffset: 0 mm; ThresholdOffset: 0 mm
Type - Door Panel Properties - Panel 1 - PanelDepth: 40 mm; PanelOperation: SWINGING; PanelWidth: 0.508451; PanelPosition: RIGHT
Type - Door Panel Properties - Panel 2 - PanelDepth: 40 mm; PanelOperation: SWINGING; PanelWidth: 0.508451; PanelPosition: LEFT
OverallHeight: 2300 mm; OverallWidth: 1500 mm; Classification: 1.10 IfcDoorStyle (uks) (RKAS BIM + ARCHICAD Classification); 523 Terasuksed (V1- EHITUSKULUDE LIIGITAMINE EVS 885:2005)
Avatäited - 10 Tulekindlus: EI-30
Pset_ManufacturerTypeInformation - Manufacturer: SAKU METALL
AR_Uks - 310_Materjal: TERAS; 375_Viimistlus_seest: LENG: HALL, RAL 7045, UKSELEHT: HALL, RAL 7045; 376_Viimistlus_väljast: LENG: HALL, RAL 7045, UKSELEHT: HALL, RAL 7045; 001_Nimetus: SISEUKS; 300_Tüüp: SU-24*; 305_Ava_mõõt: 1 500x2 300; 315_Avanemine: PAREMAKÄE UKS; ARCHICAD tüüp: Side Hung; 320_Klaas: -; 325_Helipidavus: 40 dB; 330_Tulekindlus: EI30; 335_Välispiire: no; 340_Soojusläbivus: 0; 345_Päikesekiirgus_tegur: Undefined; 350_Klaaspakett: -; 355_Pindala: 3.45 m2; 360_Ratastooliga: no; 365_Isesulguv: no; 370_Evakuatsiooniväljapääs: no; 380_Lukustus: VARUSTADA SOLENOIDMOOTORLUKUGA (VT. NÕRKVOOL). SISSEPOOLE LIBLIKLUKUSTUS, VÄLJASPOOLT (JÕUSAALIS) LUKUSTATAV VÕTMEGA, PASSIIVSELE UKSELEHELE SERVARIIV. KÄEPIDE ASSA RUKOLINE, L-KUJULINE ÜMARATE KATETEGA LINK, HARJATUD, ROOSTEVABA, OTS TAGASIPÖÖRDEGA. HINGED VASTAVALT TOOTJALE.; 900_Tootja: SAKU METALL; 905_Mudel: -; 910_Tooteinfo: LÄHTUDA TOOTJAFIRMA INFOLEHEST; 915_Kasutus-ja_hooldusjuhend: LÄHTUDA TOOTJAFIRMA INFOLEHEST
Pset_DoorCommon - Reference: SU-24*; FireRating: EI-30/Sa; ThermalTransmittance: 0
Pset_FireRatingProperties - FireResistanceRating: EI-30/Sa
AC_Pset_RenovationAndPhasing - Renovation Status: New

# IfcDoor: Double Door 24, SU-16
In: Esimene korrus
Type - OperationType: DOUBLE_DOOR_SINGLE_SWING; ParameterTakesPrecedence: no; Sizeable: no
Type - Door Lining Properties - LiningThickness: 40 mm; ThresholdDepth: 150 mm; ThresholdThickness: 12 mm; LiningOffset: 0 mm; ThresholdOffset: 40 mm
Type - Door Panel Properties - Panel 1 - PanelDepth: 40 mm; PanelOperation: SWINGING; PanelWidth: 0.307143; PanelPosition: LEFT
Type - Door Panel Properties - Panel 2 - PanelDepth: 40 mm; PanelOperation: SWINGING; PanelWidth: 0.714286; PanelPosition: RIGHT
OverallHeight: 2300 mm; OverallWidth: 1200 mm; Classification: 1.10 IfcDoorStyle (uks) (RKAS BIM + ARCHICAD Classification); 523 Terasuksed (V1- EHITUSKULUDE LIIGITAMINE EVS 885:2005)
Pset_ManufacturerTypeInformation - Manufacturer: SAKU METALL
AR_Uks - 310_Materjal: TERAS; 376_Viimistlus_väljast: LENG: HALL, RAL 7045, UKSELEHT: HALL, RAL 7045; 375_Viimistlus_seest: LENG: HALL, RAL 7045, UKSELEHT: HALL, RAL 7045; 001_Nimetus: SISEUKS; 300_Tüüp: SU-16; 305_Ava_mõõt: 1 200x2 300; 315_Avanemine: PAREMAKÄE UKS; ARCHICAD tüüp: Side Hung; 320_Klaas: -; 325_Helipidavus: -; 330_Tulekindlus: nõudeid ei esitata; 335_Välispiire: no; 340_Soojusläbivus: 0; 345_Päikesekiirgus_tegur: Undefined; 350_Klaaspakett: -; 355_Pindala: 2.76 m2; 360_Ratastooliga: no; 365_Isesulguv: no; 370_Evakuatsiooniväljapääs: no; 380_Lukustus: VARUSTADA SOLENOIDMOOTORLUKUGA (VT. NÕRKVOOL). SISSEPOOLE LIBLIKLUKUSTUS, VÄLJASPOOLT LUKUSTATAV VÕTMEGA, PASSIIVSELE UKSELEHELE SERVARIIV. KÄEPIDE ASSA RUKOLINE, L-KUJULINE ÜMARATE KATETEGA LINK, HARJATUD, ROOSTEVABA, OTS TAGASIPÖÖRDEGA. HINGED VASTAVALT TOOTJALE.; 900_Tootja: SAKU METALL; 905_Mudel: -; 910_Tooteinfo: LÄHTUDA TOOTJAFIRMA INFOLEHEST; 915_Kasutus-ja_hooldusjuhend: LÄHTUDA TOOTJAFIRMA INFOLEHEST
Pset_DoorCommon - Reference: SU-16; ThermalTransmittance: 0
AC_Pset_RenovationAndPhasing - Renovation Status: New

# IfcDoor: Double Door 24, SU-12
In: Esimene korrus
Type - OperationType: DOUBLE_DOOR_SINGLE_SWING; ParameterTakesPrecedence: no; Sizeable: no
Type - Door Lining Properties - LiningThickness: 40 mm; ThresholdDepth: 150 mm; ThresholdThickness: 12 mm; LiningOffset: 190 mm; ThresholdOffset: 190 mm
Type - Door Panel Properties - Panel 1 - PanelDepth: 40 mm; PanelOperation: SWINGING; PanelWidth: 0.307143; PanelPosition: LEFT
Type - Door Panel Properties - Panel 2 - PanelDepth: 40 mm; PanelOperation: SWINGING; PanelWidth: 0.714286; PanelPosition: RIGHT
OverallHeight: 2300 mm; OverallWidth: 1200 mm; Classification: 1.10 IfcDoorStyle (uks) (RKAS BIM + ARCHICAD Classification); 523 Terasuksed (V1- EHITUSKULUDE LIIGITAMINE EVS 885:2005)
Pset_ManufacturerTypeInformation - Manufacturer: SAKU METALL
AR_Uks - 310_Materjal: TERAS; 376_Viimistlus_väljast: LENG: HALL, RAL 7045, UKSELEHT: HALL, RAL 7045; 375_Viimistlus_seest: LENG: HALL, RAL 7045, UKSELEHT: HALL, RAL 7045; 001_Nimetus: SISEUKS; 300_Tüüp: SU-12; 305_Ava_mõõt: 1 200x2 300; 315_Avanemine: PAREMAKÄE UKS; ARCHICAD tüüp: Side Hung; 320_Klaas: -; 325_Helipidavus: -; 330_Tulekindlus: nõudeid ei esitata; 335_Välispiire: no; 340_Soojusläbivus: 0; 345_Päikesekiirgus_tegur: Undefined; 350_Klaaspakett: -; 355_Pindala: 2.76 m2; 360_Ratastooliga: no; 365_Isesulguv: no; 370_Evakuatsiooniväljapääs: no; 380_Lukustus: VARUSTADA SOLENOIDMOOTORLUKUGA (VT. NÕRKVOOL). SISSEPOOLE LIBLIKLUKUSTUS, VÄLJASPOOLT LUKUSTATAV VÕTMEGA, PASSIIVSELE UKSELEHELE SERVARIIV. KÄEPIDE ASSA RUKOLINE, L-KUJULINE ÜMARATE KATETEGA LINK, HARJATUD, ROOSTEVABA, OTS TAGASIPÖÖRDEGA. HINGED VASTAVALT TOOTJALE.; 900_Tootja: SAKU METALL; 905_Mudel: -; 910_Tooteinfo: LÄHTUDA TOOTJAFIRMA INFOLEHEST; 915_Kasutus-ja_hooldusjuhend: LÄHTUDA TOOTJAFIRMA INFOLEHEST
Pset_DoorCommon - Reference: SU-12; ThermalTransmittance: 0
AC_Pset_RenovationAndPhasing - Renovation Status: New

# IfcDoor: Double Door 24, SU-16
In: Esimene korrus
Type - OperationType: DOUBLE_DOOR_SINGLE_SWING; ParameterTakesPrecedence: no; Sizeable: no
Type - Door Lining Properties - LiningThickness: 40 mm; ThresholdDepth: 150 mm; ThresholdThickness: 12 mm; LiningOffset: 190 mm; ThresholdOffset: 190 mm
Type - Door Panel Properties - Panel 1 - PanelDepth: 40 mm; PanelOperation: SWINGING; PanelWidth: 0.307143; PanelPosition: RIGHT
Type - Door Panel Properties - Panel 2 - PanelDepth: 40 mm; PanelOperation: SWINGING; PanelWidth: 0.714286; PanelPosition: LEFT
OverallHeight: 2300 mm; OverallWidth: 1200 mm; Classification: 1.10 IfcDoorStyle (uks) (RKAS BIM + ARCHICAD Classification); 523 Terasuksed (V1- EHITUSKULUDE LIIGITAMINE EVS 885:2005)
Pset_ManufacturerTypeInformation - Manufacturer: SAKU METALL
AR_Uks - 310_Materjal: TERAS; 376_Viimistlus_väljast: LENG: HALL, RAL 7045, UKSELEHT: HALL, RAL 7045; 375_Viimistlus_seest: LENG: HALL, RAL 7045, UKSELEHT: HALL, RAL 7045; 001_Nimetus: SISEUKS; 300_Tüüp: SU-16; 305_Ava_mõõt: 1 200x2 300; 315_Avanemine: PAREMAKÄE UKS; ARCHICAD tüüp: Side Hung; 320_Klaas: -; 325_Helipidavus: -; 330_Tulekindlus: nõudeid ei esitata; 335_Välispiire: no; 340_Soojusläbivus: 0; 345_Päikesekiirgus_tegur: Undefined; 350_Klaaspakett: -; 355_Pindala: 2.76 m2; 360_Ratastooliga: no; 365_Isesulguv: no; 370_Evakuatsiooniväljapääs: no; 380_Lukustus: VARUSTADA SOLENOIDMOOTORLUKUGA (VT. NÕRKVOOL). SISSEPOOLE LIBLIKLUKUSTUS, VÄLJASPOOLT LUKUSTATAV VÕTMEGA, PASSIIVSELE UKSELEHELE SERVARIIV. KÄEPIDE ASSA RUKOLINE, L-KUJULINE ÜMARATE KATETEGA LINK, HARJATUD, ROOSTEVABA, OTS TAGASIPÖÖRDEGA. HINGED VASTAVALT TOOTJALE.; 900_Tootja: SAKU METALL; 905_Mudel: -; 910_Tooteinfo: LÄHTUDA TOOTJAFIRMA INFOLEHEST; 915_Kasutus-ja_hooldusjuhend: LÄHTUDA TOOTJAFIRMA INFOLEHEST
Pset_DoorCommon - Reference: SU-16; ThermalTransmittance: 0
AC_Pset_RenovationAndPhasing - Renovation Status: New

# IfcDoor: Double Door 24, SU-20*
In: Teine korrus
Type - OperationType: DOUBLE_DOOR_SINGLE_SWING; ParameterTakesPrecedence: no; Sizeable: no
Type - Door Lining Properties - LiningThickness: 40 mm; ThresholdDepth: 150 mm; ThresholdThickness: 12 mm; LiningOffset: 190 mm; ThresholdOffset: 190 mm
Type - Door Panel Properties - Panel 1 - PanelDepth: 40 mm; PanelOperation: SWINGING; PanelWidth: 0.621053; PanelPosition: RIGHT
Type - Door Panel Properties - Panel 2 - PanelDepth: 40 mm; PanelOperation: SWINGING; PanelWidth: 0.394737; PanelPosition: LEFT
OverallHeight: 2300 mm; OverallWidth: 1600 mm; Classification: 1.10 IfcDoorStyle (uks) (RKAS BIM + ARCHICAD Classification); 523 Terasuksed (V1- EHITUSKULUDE LIIGITAMINE EVS 885:2005)
Avatäited - 10 Tulekindlus: EI-30
Pset_ManufacturerTypeInformation - Manufacturer: SAKU METALL
AR_Uks - 310_Materjal: TERAS; 375_Viimistlus_seest: LENG: HALL, RAL 7045, UKSELEHT: HALL, RAL 7045; 376_Viimistlus_väljast: LENG: HALL, RAL 7045, UKSELEHT: HALL, RAL 7045; 001_Nimetus: SISEUKS; 300_Tüüp: SU-20*; 305_Ava_mõõt: 1 600x2 300; 315_Avanemine: PAREMAKÄE UKS; ARCHICAD tüüp: Side Hung; 320_Klaas: -; 325_Helipidavus: 40 dB; 330_Tulekindlus: EI30; 335_Välispiire: no; 340_Soojusläbivus: 0; 345_Päikesekiirgus_tegur: Undefined; 350_Klaaspakett: -; 355_Pindala: 3.68 m2; 360_Ratastooliga: no; 365_Isesulguv: no; 370_Evakuatsiooniväljapääs: no; 380_Lukustus: VARUSTADA SOLENOIDMOOTORLUKUGA (VT. NÕRKVOOL). SISSEPOOLE LIBLIKLUKUSTUS, VÄLJASPOOLT (JÕUSAALIS) LUKUSTATAV VÕTMEGA, PASSIIVSELE UKSELEHELE SERVARIIV. KÄEPIDE ASSA RUKOLINE, L-KUJULINE ÜMARATE KATETEGA LINK, HARJATUD, ROOSTEVABA, OTS TAGASIPÖÖRDEGA. HINGED VASTAVALT TOOTJALE.; 900_Tootja: SAKU METALL; 905_Mudel: -; 910_Tooteinfo: LÄHTUDA TOOTJAFIRMA INFOLEHEST; 915_Kasutus-ja_hooldusjuhend: LÄHTUDA TOOTJAFIRMA INFOLEHEST
Pset_DoorCommon - Reference: SU-20*; FireRating: EI-30/Sa; ThermalTransmittance: 0
Pset_FireRatingProperties - FireResistanceRating: EI-30/Sa
AC_Pset_RenovationAndPhasing - Renovation Status: New

# IfcDoor: Double Door 24, SU-12
In: Esimene korrus
Type - OperationType: DOUBLE_DOOR_SINGLE_SWING; ParameterTakesPrecedence: no; Sizeable: no
Type - Door Lining Properties - LiningThickness: 40 mm; ThresholdDepth: 150 mm; ThresholdThickness: 12 mm; LiningOffset: 190 mm; ThresholdOffset: 230 mm
Type - Door Panel Properties - Panel 1 - PanelDepth: 40 mm; PanelOperation: SWINGING; PanelWidth: 0.307143; PanelPosition: RIGHT
Type - Door Panel Properties - Panel 2 - PanelDepth: 40 mm; PanelOperation: SWINGING; PanelWidth: 0.714286; PanelPosition: LEFT
OverallHeight: 2300 mm; OverallWidth: 1200 mm; Classification: 1.10 IfcDoorStyle (uks) (RKAS BIM + ARCHICAD Classification); 523 Terasuksed (V1- EHITUSKULUDE LIIGITAMINE EVS 885:2005)
Pset_ManufacturerTypeInformation - Manufacturer: SAKU METALL
AR_Uks - 310_Materjal: TERAS; 376_Viimistlus_väljast: LENG: HALL, RAL 7045, UKSELEHT: HALL, RAL 7045; 375_Viimistlus_seest: LENG: HALL, RAL 7045, UKSELEHT: HALL, RAL 7045; 001_Nimetus: SISEUKS; 300_Tüüp: SU-12; 305_Ava_mõõt: 1 200x2 300; 315_Avanemine: PAREMAKÄE UKS; ARCHICAD tüüp: Side Hung; 320_Klaas: -; 325_Helipidavus: -; 330_Tulekindlus: nõudeid ei esitata; 335_Välispiire: no; 340_Soojusläbivus: 0; 345_Päikesekiirgus_tegur: Undefined; 350_Klaaspakett: -; 355_Pindala: 2.76 m2; 360_Ratastooliga: no; 365_Isesulguv: no; 370_Evakuatsiooniväljapääs: no; 380_Lukustus: VARUSTADA SOLENOIDMOOTORLUKUGA (VT. NÕRKVOOL). SISSEPOOLE LIBLIKLUKUSTUS, VÄLJASPOOLT LUKUSTATAV VÕTMEGA, PASSIIVSELE UKSELEHELE SERVARIIV. KÄEPIDE ASSA RUKOLINE, L-KUJULINE ÜMARATE KATETEGA LINK, HARJATUD, ROOSTEVABA, OTS TAGASIPÖÖRDEGA. HINGED VASTAVALT TOOTJALE.; 900_Tootja: SAKU METALL; 905_Mudel: -; 910_Tooteinfo: LÄHTUDA TOOTJAFIRMA INFOLEHEST; 915_Kasutus-ja_hooldusjuhend: LÄHTUDA TOOTJAFIRMA INFOLEHEST
Pset_DoorCommon - Reference: SU-12; ThermalTransmittance: 0
AC_Pset_RenovationAndPhasing - Renovation Status: New

# IfcDoor: Double Door 24, SU-11
In: Esimene korrus
Type - OperationType: DOUBLE_DOOR_SINGLE_SWING; ParameterTakesPrecedence: no; Sizeable: no
Type - Door Lining Properties - LiningThickness: 40 mm; ThresholdDepth: 160 mm; ThresholdThickness: 12 mm; LiningOffset: 200 mm; ThresholdOffset: 200 mm
Type - Door Panel Properties - Panel 1 - PanelDepth: 40 mm; PanelOperation: SWINGING; PanelWidth: 0.358678; PanelPosition: LEFT
Type - Door Panel Properties - Panel 2 - PanelDepth: 40 mm; PanelOperation: SWINGING; PanelWidth: 0.661157; PanelPosition: RIGHT
OverallHeight: 2300 mm; OverallWidth: 1290 mm; Classification: 1.10 IfcDoorStyle (uks) (RKAS BIM + ARCHICAD Classification); 523 Terasuksed (V1- EHITUSKULUDE LIIGITAMINE EVS 885:2005)
Pset_DoorCommon - Reference: SU-11; FireRating: EI-30/Sa; ThermalTransmittance: 0
AR_Uks - 001_Nimetus: SISEUKS; 300_Tüüp: SU-11; 305_Ava_mõõt: 1 290x2 300; 310_Materjal: MUDELIS: väljast-PULBERVÄRVITUD, TOON: HALL, RAL 7045; PULBERVÄRVITUD, TOON: HALL, RAL 7045; seest-PULBERVÄRVITUD, TOON: HALL, RAL 7045; PULBERVÄRVITUD, TOON: HALL, RAL 7045; MÄRKUS: TERAS; 315_Avanemine: PAREMAKÄE UKS; ARCHICAD tüüp: Side Hung; 320_Klaas: -; 325_Helipidavus: -; 330_Tulekindlus: nõudeid ei esitata; 335_Välispiire: no; 340_Soojusläbivus: 0; 345_Päikesekiirgus_tegur: Undefined; 350_Klaaspakett: -; 355_Pindala: 2.967 m2; 360_Ratastooliga: no; 365_Isesulguv: no; 370_Evakuatsiooniväljapääs: no; 375_Viimistlus_seest: MUDELIS: PULBERVÄRVITUD, TOON: HALL, RAL 7045; PULBERVÄRVITUD, TOON: HALL, RAL 7045; MÄRKUS: LENG: HALL, RAL 7045, UKSELEHT: HALL, RAL 7045; 376_Viimistlus_väljast: MUDELIS: PULBERVÄRVITUD, TOON: HALL, RAL 7045; PULBERVÄRVITUD, TOON: HALL, RAL 7045; MÄRKUS: LENG: HALL, RAL 7045, UKSELEHT: HALL, RAL 7045; 380_Lukustus: SISSEPOOLE LIBLIKLUKUSTUS, VÄLJASPOOLT LUKUSTATAV VÕTMEGA, PASSIIVSELE UKSELEHELE SERVARIIV. KÄEPIDE ASSA RUKOLINE, L-KUJULINE ÜMARATE KATETEGA LINK, HARJATUD, ROOSTEVABA, OTS TAGASIPÖÖRDEGA. HINGED VASTAVALT TOOTJALE.; 900_Tootja: SAKU METALL; 905_Mudel: -; 910_Tooteinfo: LÄHTUDA TOOTJAFIRMA INFOLEHEST; 915_Kasutus-ja_hooldusjuhend: LÄHTUDA TOOTJAFIRMA INFOLEHEST
Pset_FireRatingProperties - FireResistanceRating: EI-30/Sa
Pset_ManufacturerTypeInformation - Manufacturer: SAKU METALL VÕI ANALOOG
AC_Pset_RenovationAndPhasing - Renovation Status: New

# IfcDoor: Double Door 24 (3)
In: Esimene korrus
Type - OperationType: DOUBLE_DOOR_SINGLE_SWING; ParameterTakesPrecedence: no; Sizeable: no
Type - Door Lining Properties - LiningThickness: 40 mm; ThresholdDepth: 200 mm; ThresholdThickness: 12 mm; LiningOffset: 0 mm; ThresholdOffset: 40 mm
Type - Door Panel Properties - Panel 1 - PanelDepth: 40 mm; PanelOperation: SWINGING; PanelWidth: 0.307143; PanelPosition: RIGHT
Type - Door Panel Properties - Panel 2 - PanelDepth: 40 mm; PanelOperation: SWINGING; PanelWidth: 0.714286; PanelPosition: LEFT
OverallHeight: 2300 mm; OverallWidth: 1200 mm; Classification: 1.10 IfcDoorStyle (uks) (RKAS BIM + ARCHICAD Classification); 523 Terasuksed (V1- EHITUSKULUDE LIIGITAMINE EVS 885:2005)
Pset_ManufacturerTypeInformation - Manufacturer: SAKU METALL
AR_Uks - 310_Materjal: TERAS; 376_Viimistlus_väljast: LENG: HALL, RAL 7045, UKSELEHT: HALL, RAL 7045; 375_Viimistlus_seest: LENG: HALL, RAL 7045, UKSELEHT: HALL, RAL 7045; 001_Nimetus: SISEUKS; 305_Ava_mõõt: 1 200x2 300; 315_Avanemine: PAREMAKÄE UKS; ARCHICAD tüüp: Side Hung; 320_Klaas: -; 325_Helipidavus: -; 335_Välispiire: no; 340_Soojusläbivus: 0; 345_Päikesekiirgus_tegur: Undefined; 350_Klaaspakett: -; 355_Pindala: 2.76 m2; 360_Ratastooliga: no; 365_Isesulguv: no; 370_Evakuatsiooniväljapääs: no; 900_Tootja: SAKU METALL; 905_Mudel: -; 910_Tooteinfo: LÄHTUDA TOOTJAFIRMA INFOLEHEST; 915_Kasutus-ja_hooldusjuhend: LÄHTUDA TOOTJAFIRMA INFOLEHEST
Pset_DoorCommon - ThermalTransmittance: 0
AC_Pset_RenovationAndPhasing - Renovation Status: New
Name | 300_Tüüp = Reference | 330_Tulekindlus | 380_Lukustus | 10 Tulekindlus = FireRating = FireResistanceRating
SU-11 | SU-11 | nõudeid ei esitata | SISSEPOOLE LIBLIKLUKUSTUS, VÄLJASPOOLT LUKUSTATAV VÕTMEGA, PASSIIVSELE UKSELEHELE SERVARIIV. KÄEPIDE ASSA RUKOLINE, L-KUJULINE ÜMARATE KATETEGA LINK, HARJATUD, ROOSTEVABA, OTS TAGASIPÖÖRDEGA. HINGED VASTAVALT TOOTJALE.
2 x SU-10* | SU-10* | EI30 | VARUSTADA SOLENOIDMOOTORLUKUGA (VT. NÕRKVOOL). SISSEPOOLE LIBLIKLUKUSTUS, VÄLJASPOOLT LUKUSTATAV VÕTMEGA, PASSIIVSELE UKSELEHELE SERVARIIV. KÄEPIDE ASSA RUKOLINE, L-KUJULINE ÜMARATE KATETEGA LINK, HARJATUD, ROOSTEVABA, OTS TAGASIPÖÖRDEGA. HINGED VASTAVALT TOOTJALE. | EI-30

# IfcDoor: Double Door 24, VUA-02
In: Esimene korrus
Type - OperationType: DOUBLE_DOOR_SINGLE_SWING; ParameterTakesPrecedence: no; Sizeable: no
Type - Door Lining Properties - LiningThickness: 40 mm; ThresholdDepth: 210 mm; ThresholdThickness: 12 mm; LiningOffset: 250 mm; ThresholdOffset: 250 mm
Type - Door Panel Properties - Panel 1 - PanelDepth: 40 mm; PanelOperation: SWINGING; PanelWidth: 0.50625; PanelPosition: RIGHT
Type - Door Panel Properties - Panel 2 - PanelDepth: 40 mm; PanelOperation: SWINGING; PanelWidth: 0.50625; PanelPosition: LEFT
OverallHeight: 2400 mm; OverallWidth: 2000 mm; Classification: 1.10 IfcDoorStyle (uks) (RKAS BIM + ARCHICAD Classification); 433 Terasuksed ja -väravad (V1- EHITUSKULUDE LIIGITAMINE EVS 885:2005)
AR_Uks - 376_Viimistlus_väljast: <376_Viimistlus_väljast>; 375_Viimistlus_seest: <375_Viimistlus_seest>; 310_Materjal: TERAS; 001_Nimetus: VÄLISUKS, ABIHOONE; 300_Tüüp: VUA-02; 305_Ava_mõõt: 2 000x2 400; 315_Avanemine: VASAKUKÄE UKS; ARCHICAD tüüp: Side Hung; 320_Klaas: -; 325_Helipidavus: -; 330_Tulekindlus: nõudeid ei esitata; 335_Välispiire: no; 340_Soojusläbivus: 0; 345_Päikesekiirgus_tegur: -; 350_Klaaspakett: -; 355_Pindala: 4.8 m2; 360_Ratastooliga: no; 365_Isesulguv: no; 370_Evakuatsiooniväljapääs: no; 380_Lukustus: VÄLJASPOOLT LUKUSTATAV VÕTMEGA, PASSIIVSELE UKSELEHELE SERVARIIV. KÄEPIDE ASSA RUKOLINE, L-KUJULINE ÜMARATE KATETEGA LINK, HARJATUD, ROOSTEVABA, OTS TAGASIPÖÖRDEGA. HINGED VASTAVALT TOOTJALE.; 900_Tootja: SAKU METALL; 905_Mudel: -; 910_Tooteinfo: LÄHTUDA TOOTJAFIRMA INFOLEHEST; 915_Kasutus-ja_hooldusjuhend: LÄHTUDA TOOTJAFIRMA INFOLEHEST
Pset_DoorCommon - Reference: VUA-02; FireRating: EI-30/Sa; ThermalTransmittance: 0
Pset_FireRatingProperties - FireResistanceRating: EI-30/Sa
Pset_ManufacturerTypeInformation - Manufacturer: SAKU METALL VÕI ANALOOG
AC_Pset_RenovationAndPhasing - Renovation Status: New

# IfcDoor: Double Door 24 (2)
In: Esimene korrus
Type - OperationType: DOUBLE_DOOR_SINGLE_SWING; ParameterTakesPrecedence: no; Sizeable: no
Type - Door Lining Properties - LiningThickness: 40 mm; ThresholdDepth: 220 mm; ThresholdThickness: 12 mm; LiningOffset: 0 mm; ThresholdOffset: 0 mm
Type - Door Panel Properties - Panel 1 - PanelDepth: 40 mm; PanelOperation: SWINGING; PanelWidth: 0.504762; PanelPosition: RIGHT
Type - Door Panel Properties - Panel 2 - PanelDepth: 40 mm; PanelOperation: SWINGING; PanelWidth: 0.504762; PanelPosition: LEFT
OverallHeight: 2400 mm; OverallWidth: 2600 mm; Classification: 1.10 IfcDoorStyle (uks) (RKAS BIM + ARCHICAD Classification); 433 Terasuksed ja -väravad (V1- EHITUSKULUDE LIIGITAMINE EVS 885:2005)
AR_Uks - 315_Avanemine: PAREMAKÄE UKS; 376_Viimistlus_väljast: <376_Viimistlus_väljast>; 375_Viimistlus_seest: <375_Viimistlus_seest>; 310_Materjal: TERAS; 001_Nimetus: GARAAŽIUKS, ABIHOONE; 300_Tüüp: GUA-01; 305_Ava_mõõt: 2 600x2 400; 320_Klaas: -; 325_Helipidavus: -; 330_Tulekindlus: nõudeid ei esitata; 335_Välispiire: no; 340_Soojusläbivus: 0; 345_Päikesekiirgus_tegur: -; 350_Klaaspakett: -; 355_Pindala: 6.24 m2; 360_Ratastooliga: no; 365_Isesulguv: no; 370_Evakuatsiooniväljapääs: no; 380_Lukustus: ÜKS UKSELEHT SEESTPOOLT KINNITATAV SEESTPOOLT RIIVIGA. TEINE UKSELEHT VÄLJASPOOLT VÕTMEGA LUKUSTATAV. ASSA, HARJATUD, ROOSTEKINDEL. HINGED VASTAVALT TOOTJALE .; 900_Tootja: -; 905_Mudel: -; 910_Tooteinfo: LÄHTUDA TOOTJAFIRMA INFOLEHEST; 915_Kasutus-ja_hooldusjuhend: LÄHTUDA TOOTJAFIRMA INFOLEHEST
Pset_DoorCommon - Reference: GUA-01; ThermalTransmittance: 0
Pset_ManufacturerTypeInformation - Manufacturer: -
AC_Pset_RenovationAndPhasing - Renovation Status: New

# IfcDoor: Double Door 24 (2)
In: Esimene korrus
Type - OperationType: DOUBLE_DOOR_SINGLE_SWING; ParameterTakesPrecedence: no; Sizeable: no
Type - Door Lining Properties - LiningThickness: 40 mm; ThresholdDepth: 220 mm; ThresholdThickness: 12 mm; LiningOffset: 0 mm; ThresholdOffset: 40 mm
Type - Door Panel Properties - Panel 1 - PanelDepth: 40 mm; PanelOperation: SWINGING; PanelWidth: 0.50625; PanelPosition: RIGHT
Type - Door Panel Properties - Panel 2 - PanelDepth: 40 mm; PanelOperation: SWINGING; PanelWidth: 0.50625; PanelPosition: LEFT
OverallHeight: 2380 mm; OverallWidth: 2000 mm; Classification: 1.10 IfcDoorStyle (uks) (RKAS BIM + ARCHICAD Classification); 523 Terasuksed (V1- EHITUSKULUDE LIIGITAMINE EVS 885:2005)
Pset_DoorCommon - FireRating: -; ThermalTransmittance: 0
Pset_FireRatingProperties - FireResistanceRating: -
Pset_ManufacturerTypeInformation - Manufacturer: SAKU METALL
AR_Uks - 376_Viimistlus_väljast: <376_Viimistlus_väljast>; 375_Viimistlus_seest: <375_Viimistlus_seest>; 310_Materjal: TERAS; 001_Nimetus: SISEUKS, ABIHOONE; 305_Ava_mõõt: 2 000x2 380; 320_Klaas: -; 325_Helipidavus: -; 330_Tulekindlus: nõudeid ei esitata; 335_Välispiire: no; 340_Soojusläbivus: 0; 345_Päikesekiirgus_tegur: -; 350_Klaaspakett: -; 355_Pindala: 4.76 m2; 360_Ratastooliga: no; 365_Isesulguv: no; 370_Evakuatsiooniväljapääs: no; 380_Lukustus: MITTELUKUSTATAVAD. KÄEPIDE ASSA RUKOLINE, L-KUJULINE ÜMARATE KATETEGA LINK, HARJATUD, ROOSTEVABA, OTS TAGASIPÖÖRDEGA. HINGED VASTAVALT TOOTJALE.; 900_Tootja: SAKU METALL; 905_Mudel: -; 910_Tooteinfo: LÄHTUDA TOOTJAFIRMA INFOLEHEST; 915_Kasutus-ja_hooldusjuhend: LÄHTUDA TOOTJAFIRMA INFOLEHEST
AC_Pset_RenovationAndPhasing - Renovation Status: New
Name | Reference = 300_Tüüp | 315_Avanemine
SUA-01 | SUA-01 | PAREMAKÄE UKS; ARCHICAD tüüp: Side Hung
SUA-02 | SUA-02 | VASAKUKÄE UKS; ARCHICAD tüüp: Side Hung

# IfcDoor: Double Door 24, SU-11
In: Esimene korrus
Type - OperationType: DOUBLE_DOOR_SINGLE_SWING; ParameterTakesPrecedence: no; Sizeable: no
Type - Door Lining Properties - LiningThickness: 40 mm; ThresholdThickness: 12 mm; LiningOffset: 0 mm; ThresholdOffset: 40 mm
Type - Door Panel Properties - Panel 1 - PanelDepth: 40 mm; PanelOperation: SWINGING; PanelWidth: 0.307143; PanelPosition: LEFT
Type - Door Panel Properties - Panel 2 - PanelDepth: 40 mm; PanelOperation: SWINGING; PanelWidth: 0.714286; PanelPosition: RIGHT
OverallHeight: 2300 mm; OverallWidth: 1200 mm; Classification: 1.10 IfcDoorStyle (uks) (RKAS BIM + ARCHICAD Classification); 523 Terasuksed (V1- EHITUSKULUDE LIIGITAMINE EVS 885:2005)
Pset_ManufacturerTypeInformation - Manufacturer: SAKU METALL
AR_Uks - 310_Materjal: TERAS; 376_Viimistlus_väljast: LENG: HALL, RAL 7045, UKSELEHT: HALL, RAL 7045; 375_Viimistlus_seest: LENG: HALL, RAL 7045, UKSELEHT: HALL, RAL 7045; 001_Nimetus: SISEUKS; 300_Tüüp: SU-11; 305_Ava_mõõt: 1 200x2 300; 315_Avanemine: PAREMAKÄE UKS; ARCHICAD tüüp: Side Hung; 320_Klaas: -; 325_Helipidavus: -; 330_Tulekindlus: nõudeid ei esitata; 335_Välispiire: no; 340_Soojusläbivus: 0; 345_Päikesekiirgus_tegur: Undefined; 350_Klaaspakett: -; 355_Pindala: 2.76 m2; 360_Ratastooliga: no; 365_Isesulguv: no; 370_Evakuatsiooniväljapääs: no; 380_Lukustus: SISSEPOOLE LIBLIKLUKUSTUS, VÄLJASPOOLT LUKUSTATAV VÕTMEGA, PASSIIVSELE UKSELEHELE SERVARIIV. KÄEPIDE ASSA RUKOLINE, L-KUJULINE ÜMARATE KATETEGA LINK, HARJATUD, ROOSTEVABA, OTS TAGASIPÖÖRDEGA. HINGED VASTAVALT TOOTJALE.; 900_Tootja: SAKU METALL; 905_Mudel: -; 910_Tooteinfo: LÄHTUDA TOOTJAFIRMA INFOLEHEST; 915_Kasutus-ja_hooldusjuhend: LÄHTUDA TOOTJAFIRMA INFOLEHEST
Pset_DoorCommon - Reference: SU-11; ThermalTransmittance: 0
AC_Pset_RenovationAndPhasing - Renovation Status: New

# IfcDoor: Double Door with Sidelight 24, SU-09
In: Teine korrus
Type - OperationType: USERDEFINED; ParameterTakesPrecedence: no; Sizeable: no
OverallHeight: 2300 mm; OverallWidth: 4950 mm; Classification: 1.10 IfcDoorStyle (uks) (RKAS BIM + ARCHICAD Classification); 522 Alumiiniumuksed (V1- EHITUSKULUDE LIIGITAMINE EVS 885:2005)
AR_Uks - 310_Materjal: ALUMIINIUM, UKSELEHT: PUIT; 375_Viimistlus_seest: RAAM JA LENG: HALL, RAL 7045, UKSELEHED KASESPOON; 376_Viimistlus_väljast: RAAM JA LENG: HALL, RAL 7045, UKSELEHED KASESPOON; 001_Nimetus: SISEUKS; 300_Tüüp: SU-09; 305_Ava_mõõt: 4 950x2 300; 315_Avanemine: PAREMAKÄE UKS; ARCHICAD tüüp: Side Hung; 320_Klaas: ÜHEKORDNE KLAASPAKETT, KIRGAS; 325_Helipidavus: AKNA, UKSE HELIPIDAVUS 38 dB/ PAKETI HELIPIDAVUS 30 dB; 330_Tulekindlus: nõudeid ei esitata; 335_Välispiire: no; 340_Soojusläbivus: 0; 345_Päikesekiirgus_tegur: Undefined; 350_Klaaspakett: 1X, KARASTATUD, LAMINEERITUD; 355_Pindala: 11.385 m2; 360_Ratastooliga: no; 365_Isesulguv: no; 370_Evakuatsiooniväljapääs: yes; 380_Lukustus: UKS VARUSTADA SOLENOIDMOOTORLUKUGA KORIDORI POOLE (VT. NÕRKVOOLU PROJEKTI). SEESTPOOLT LIBLIKLUKUSTUSEGA, VÄLJASPOOLT VÕTMEGA LUKUSTATAV. KÄEPIDE ON ASSA RUKO-LINE, HARJATUD, TAGASIPÖÖRATUD OTSAGA, ROOSTEVABA. HINGED VASTAVALT TOOTJALE. UKSESULGURINA KASUTADA UKSE VÕI LENGI SISSE SÜVISTATAVAT MUDELIT.; 900_Tootja: SCHÜCO; 905_Mudel: AWS/ADS 50.NI; 910_Tooteinfo: LÄHTUDA TOOTJAFIRMA INFOLEHELT; 915_Kasutus-ja_hooldusjuhend: LÄHTUDA TOOTJAFIRMA INFOLEHELT
Pset_DoorCommon - Reference: SU-09; AcousticRating: 30dB; ThermalTransmittance: 0; GlazingAreaFraction: 7.7034
AC_Pset_RenovationAndPhasing - Renovation Status: New

# IfcDoor: Double Door with Transom 24, VU-01
In: Esimene korrus
Type - OperationType: DOUBLE_DOOR_SINGLE_SWING; ParameterTakesPrecedence: no; Sizeable: no
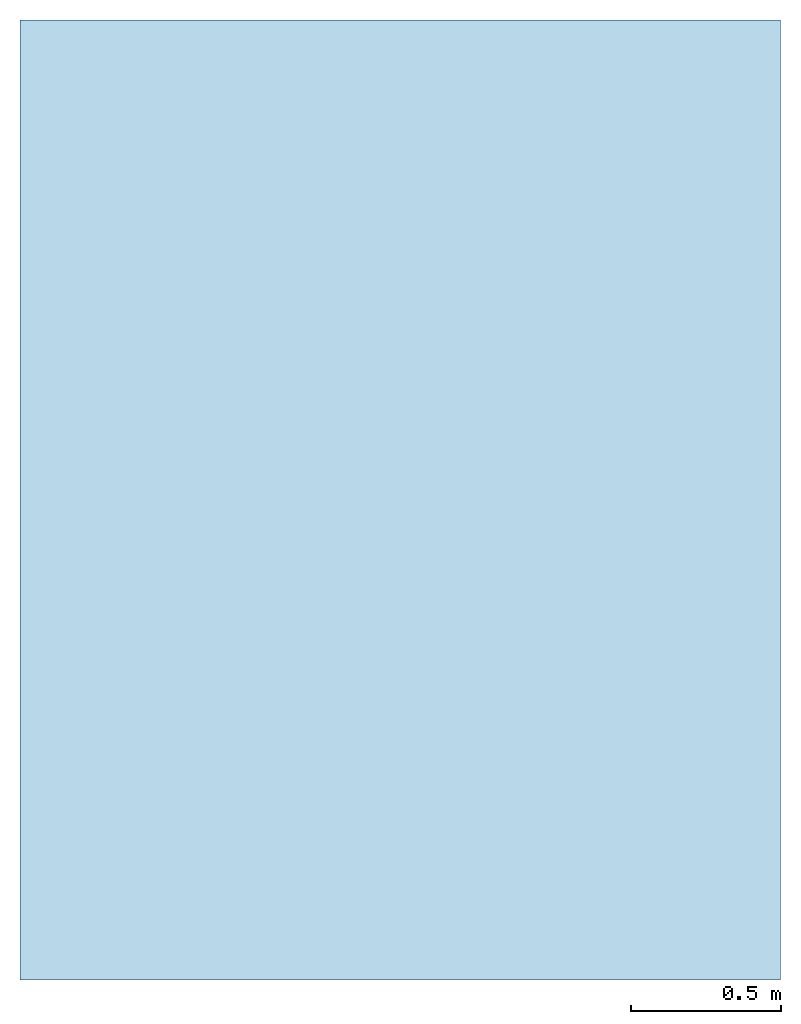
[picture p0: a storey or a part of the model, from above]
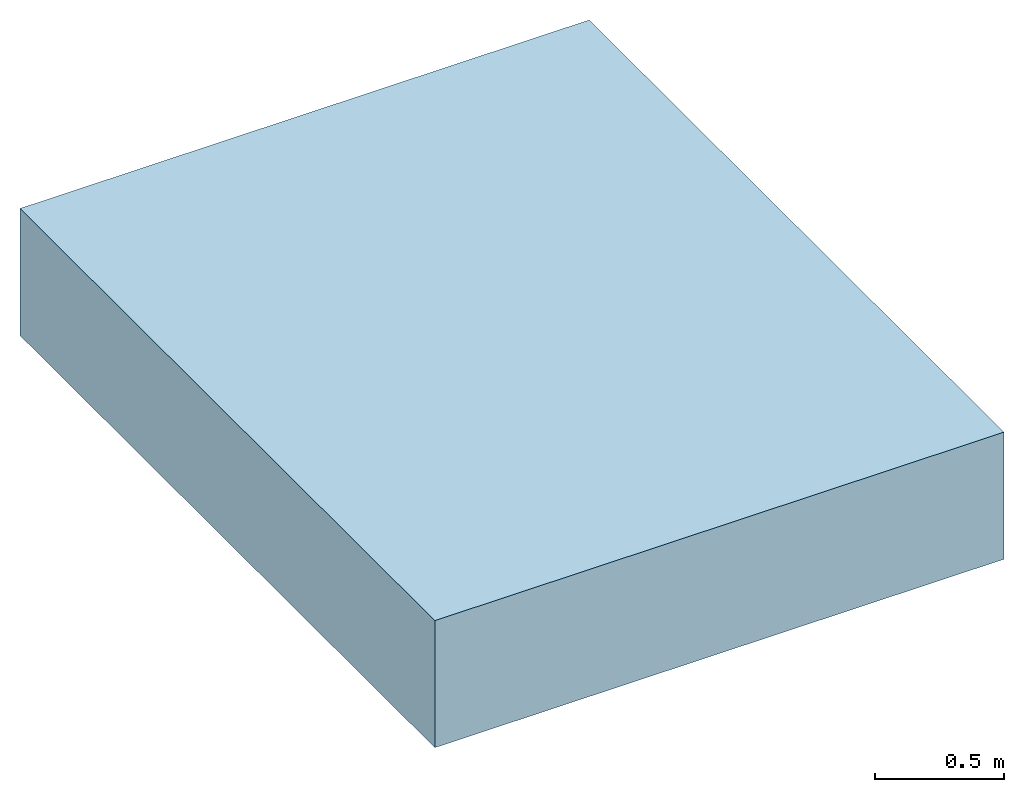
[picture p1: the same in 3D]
Properties of the parts of a building model (IFC2X3), part 3 of 4

# IfcDoor: Double Door with Transom 24, VU-01
Type - Door Lining Properties - LiningDepth: 115 mm; LiningThickness: 40 mm; TransomThickness: 40 mm; TransomOffset: 2300 mm; LiningOffset: 0 mm; CasingThickness: 25 mm; CasingDepth: 150 mm
Type - Door Panel Properties - Panel 1 - PanelDepth: 40 mm; PanelOperation: SWINGING; PanelWidth: 0.506977; PanelPosition: RIGHT
Type - Door Panel Properties - Panel 2 - PanelDepth: 40 mm; PanelOperation: SWINGING; PanelWidth: 0.506977; PanelPosition: LEFT
OverallHeight: 2800 mm; OverallWidth: 1800 mm; Classification: 1.10 IfcDoorStyle (uks) (RKAS BIM + ARCHICAD Classification); 432 Alumiiniumuksed ja -väravad (V1- EHITUSKULUDE LIIGITAMINE EVS 885:2005)
Avatäited - 06 Soojusläbivus: U≤1,0 W/m²K
Pset_ManufacturerTypeInformation - Manufacturer: SCHÜCO
AR_Uks - 315_Avanemine: <315_Avanemine>; 310_Materjal: ALUMIINIUM; 375_Viimistlus_seest: PULBERVÄRVITUD, TUMEHALL, RAL 7016; 376_Viimistlus_väljast: PULBERVÄRVITUD, TUMEHALL, RAL 7016; 001_Nimetus: VÄLISUKS; 300_Tüüp: VU-01; 305_Ava_mõõt: 1 800x2 800; 320_Klaas: 3X KLAASPAKETT, PAKETI VAHELIISTU TOON: TUMEHALL, RAL 7016; 325_Helipidavus: 30dB; 330_Tulekindlus: nõudeid ei esitata; 335_Välispiire: yes; 340_Soojusläbivus: 0; 345_Päikesekiirgus_tegur: g=0,55, VALGUSE LÄBIPAISTVUS 70%; 350_Klaaspakett: 6MM SELEKTIIV + 4 + 44.6 (P5A) LAMINEERITUD SELEKTIIV / 14MM CHRU; 355_Pindala: 5.04 m2; 360_Ratastooliga: yes; 365_Isesulguv: yes; 370_Evakuatsiooniväljapääs: yes; 380_Lukustus: VARUSTADA MOOTORELEKTRILUKUGA (VT. NÕRKVOOLU PROJEKTI). VÄLJASPOOLT LUKUSTAV VÕTMEGA. SISSEPOOLE AKTIIVSELE UKSELEHELE LIBLIKLUKUSTUS, PASSIIVSELE SERVARIIV. LUKUKORPUS VASTAVALT LUKUSTUSPROJEKTILE. KÕIK LUKUD PEAVAD OLEMA SARJASTATAVAD. KÄEPIDE ON DIAMANTEK OLD SF 2200 MM, HARJATUD, ROOSTEVABA. LISADA RAAMISISENE ASENDIANDUR.; 900_Tootja: SCHÜCO; 905_Mudel: AWS 90.SI+/ADS 90.SI; 910_Tooteinfo: LÄHTUDA TOOTJAFIRMA INFOLEHEST.; 915_Kasutus-ja_hooldusjuhend: LÄHTUDA TOOTJAFIRMA INFOLEHEST. TURVAMÄRGISTUS 1500MM KÕRGUSEL.
Pset_DoorCommon - Reference: VU-01; ThermalTransmittance: 0; GlazingAreaFraction: 3.42653; IsExternal: yes
AC_Pset_RenovationAndPhasing - Renovation Status: New

# IfcDoor: Overhead Garage Door 24, GUA-03
In: Esimene korrus
Type - OperationType: ROLLINGUP; ParameterTakesPrecedence: no; Sizeable: no
Type - Door Lining Properties - LiningThickness: 50 mm; LiningOffset: -350 mm
Type - Door Panel Properties - Panel 1 - PanelDepth: 40 mm; PanelOperation: ROLLINGUP; PanelWidth: 1; PanelPosition: MIDDLE
OverallHeight: 4200 mm; OverallWidth: 4000 mm; Classification: 1.10 IfcDoorStyle (uks) (RKAS BIM + ARCHICAD Classification); 433 Terasuksed ja -väravad (V1- EHITUSKULUDE LIIGITAMINE EVS 885:2005)
Pset_DoorCommon - FireRating: -; Reference: GUA-03; ThermalTransmittance: 0; GlazingAreaFraction: 2.64505
Pset_FireRatingProperties - FireResistanceRating: -
Pset_ManufacturerTypeInformation - Manufacturer: -
AR_Uks - 310_Materjal: TERAS; 375_Viimistlus_seest: LENG: HALL, RAL 7045, UKSELEHT: HALL, RAL 7045; 376_Viimistlus_väljast: LENG: HALL, RAL 7045, UKSELEHT: HALL, RAL 7045; 001_Nimetus: GARAAŽIUKS, ABIHOONE; 300_Tüüp: GUA-03; 305_Ava_mõõt: 4 000x4 200; 315_Avanemine: PAREMAKÄE UKS; 320_Klaas: -; 325_Helipidavus: -; 330_Tulekindlus: nõudeid ei esitata; 335_Välispiire: no; 340_Soojusläbivus: 0; 345_Päikesekiirgus_tegur: -; 350_Klaaspakett: -; 355_Pindala: 16.8 m2; 360_Ratastooliga: no; 365_Isesulguv: no; 370_Evakuatsiooniväljapääs: no; 380_Lukustus: AUTOMAATIKAGA AVATAV JA SULETAV.; 900_Tootja: -; 905_Mudel: -; 910_Tooteinfo: LÄHTUDA TOOTJAFIRMA INFOLEHEST; 915_Kasutus-ja_hooldusjuhend: LÄHTUDA TOOTJAFIRMA INFOLEHEST
AC_Pset_RenovationAndPhasing - Renovation Status: New

# IfcDoor: Overhead Garage Door 24 (5)
In: Esimene korrus
Type - OperationType: ROLLINGUP; ParameterTakesPrecedence: no; Sizeable: no
Type - Door Lining Properties - LiningThickness: 50 mm; LiningOffset: 0 mm
Type - Door Panel Properties - Panel 1 - PanelDepth: 40 mm; PanelOperation: ROLLINGUP; PanelWidth: 1; PanelPosition: MIDDLE
OverallHeight: 4200 mm; OverallWidth: 4000 mm; Classification: 1.10 IfcDoorStyle (uks) (RKAS BIM + ARCHICAD Classification); 433 Terasuksed ja -väravad (V1- EHITUSKULUDE LIIGITAMINE EVS 885:2005)
AR_Uks - 315_Avanemine: PAREMAKÄE UKS; 310_Materjal: TERAS; 375_Viimistlus_seest: LENG: HALL, RAL 7045, UKSELEHT: HALL, RAL 7045; 376_Viimistlus_väljast: LENG: HALL, RAL 7045, UKSELEHT: HALL, RAL 7045; 001_Nimetus: GARAAŽIUKS, ABIHOONE; 300_Tüüp: GUA-02; 305_Ava_mõõt: 4 000x4 200; 320_Klaas: -; 325_Helipidavus: -; 330_Tulekindlus: nõudeid ei esitata; 335_Välispiire: no; 340_Soojusläbivus: 0; 345_Päikesekiirgus_tegur: -; 350_Klaaspakett: -; 355_Pindala: 16.8 m2; 360_Ratastooliga: no; 365_Isesulguv: no; 370_Evakuatsiooniväljapääs: no; 380_Lukustus: AUTOMAATIKAGA AVATAV JA SULETAV.; 900_Tootja: -; 905_Mudel: -; 910_Tooteinfo: LÄHTUDA TOOTJAFIRMA INFOLEHEST; 915_Kasutus-ja_hooldusjuhend: LÄHTUDA TOOTJAFIRMA INFOLEHEST
Pset_ManufacturerTypeInformation - Manufacturer: -
Pset_DoorCommon - Reference: GUA-02; ThermalTransmittance: 0; GlazingAreaFraction: 2.64505
AC_Pset_RenovationAndPhasing - Renovation Status: New

# IfcFurnishingElement: Air Space 200 (2)
In: Esimene korrus
Classification: 1.11 IfcFurnitureType (mööbel) (RKAS BIM + ARCHICAD Classification); Material: Air Space
AR_001-002 - 001_Nimetus: plokk; 002_Tüüp: Air Space
Pset_QuantityTakeOff - Reference: Air Space
AC_Pset_RenovationAndPhasing - Renovation Status: New

# IfcMember: IfcMember (22)
In: Esimene korrus
Type - ElementType: Stair Riser; PredefinedType: USERDEFINED
Classification: Stair Riser (RKAS BIM + ARCHICAD Classification); Material: SV-02_Puit - Põrand
Pset_MemberCommon - Reference: Riser
AR_001-002 - 002_Tüüp: Riser
AC_Pset_RenovationAndPhasing - Renovation Status: New
Name | 001_Nimetus
SL RISER - 001 | SL RISER - 001
TV TÕUS - 021 | TV TÕUS - 021
TV TÕUS - 022 | TV TÕUS - 022
TV TÕUS - 023 | TV TÕUS - 023
TV TÕUS - 024 | TV TÕUS - 024
TV TÕUS - 025 | TV TÕUS - 025
TV TÕUS - 026 | TV TÕUS - 026
TV TÕUS - 027 | TV TÕUS - 027
TV TÕUS - 028 | TV TÕUS - 028
TV TÕUS - 029 | TV TÕUS - 029
TV TÕUS - 030 | TV TÕUS - 030
TV TÕUS - 031 | TV TÕUS - 031
TV TÕUS - 032 | TV TÕUS - 032
TV TÕUS - 033 | TV TÕUS - 033
TV TÕUS - 034 | TV TÕUS - 034
TV TÕUS - 035 | TV TÕUS - 035
TV TÕUS - 036 | TV TÕUS - 036
TV TÕUS - 037 | TV TÕUS - 037
TV TÕUS - 038 | TV TÕUS - 038
TV TÕUS - 039 | TV TÕUS - 039
TV TÕUS - 040 | TV TÕUS - 040
TV TÕUS - 041 | TV TÕUS - 041

# IfcMember: IfcMember (4)
In: Esimene korrus
Type - ElementType: Stair Structure; PredefinedType: USERDEFINED
Classification: Stair Structure (RKAS BIM + ARCHICAD Classification); Material: KON-04_Betoon - Konstuktsioon
Pset_MemberCommon - Reference: KON-04
AR_001-002 - 002_Tüüp: KON-04
AC_Pset_RenovationAndPhasing - Renovation Status: New
Name | 001_Nimetus
TT KONSTRUKTSIOON - 001 | TT KONSTRUKTSIOON - 001
TM KONSTRUKTSIOON - 001 | TM KONSTRUKTSIOON - 001
TT KONSTRUKTSIOON - 002 | TT KONSTRUKTSIOON - 002
TT KONSTRUKTSIOON - 003 | TT KONSTRUKTSIOON - 003

# IfcMember: IfcMember (22)
In: Esimene korrus
Type - ElementType: Stair Tread; PredefinedType: USERDEFINED
Classification: Stair Tread (RKAS BIM + ARCHICAD Classification); Material: SV-02_Puit - Põrand
Pset_MemberCommon - Reference: Tread
AR_001-002 - 002_Tüüp: Tread
AC_Pset_RenovationAndPhasing - Renovation Status: New
Name | 001_Nimetus
SL TREAD - 001 | SL TREAD - 001
TV ASTE - 021 | TV ASTE - 021
TV ASTE - 022 | TV ASTE - 022
TV ASTE - 023 | TV ASTE - 023
TV ASTE - 024 | TV ASTE - 024
TV ASTE - 025 | TV ASTE - 025
TV ASTE - 026 | TV ASTE - 026
TV ASTE - 027 | TV ASTE - 027
TV ASTE - 028 | TV ASTE - 028
TV ASTE - 029 | TV ASTE - 029
TV ASTE - 030 | TV ASTE - 030
TV ASTE - 031 | TV ASTE - 031
TV ASTE - 032 | TV ASTE - 032
TV ASTE - 033 | TV ASTE - 033
TV ASTE - 034 | TV ASTE - 034
TV ASTE - 035 | TV ASTE - 035
TV ASTE - 036 | TV ASTE - 036
TV ASTE - 037 | TV ASTE - 037
TV ASTE - 038 | TV ASTE - 038
TV ASTE - 039 | TV ASTE - 039
TV ASTE - 040 | TV ASTE - 040
TV ASTE - 041 | TV ASTE - 041

# IfcOpeningElement: OPENING (11)
Classification: 1.14 IfcOpeningElement (avaelement) (RKAS BIM + ARCHICAD Classification)
AR_001-002 - 001_Nimetus: AVA
AC_Pset_RenovationAndPhasing - Renovation Status: New
Name | In | Reference = 002_Tüüp
3 x AVA | Esimene korrus | AVA: 2 028x1 400
5 x AVA | Teine korrus | AVA: 2 028x1 400
3 x AVA | Teine korrus | AVA: 2 028x700

# IfcPlate: A-PP01 370, A-PP01
In: Esimene korrus
Classification: 1.15 IfcPlateType (plaat) (RKAS BIM + ARCHICAD Classification)
AR_001-002 - 001_Nimetus: A-PP01
AC_Pset_RenovationAndPhasing - Renovation Status: Existing
Pset_PlateCommon - LoadBearing: no; IsExternal: no

# IfcRailing: Air Space 200 (1676)
In: Esimene korrus
Classification: 1.16 IfcRailingType (piire) (RKAS BIM + ARCHICAD Classification); Material: Air Space
Pset_RailingCommon - Reference: Air Space; IsExternal: no
AR_001-002 - 001_Nimetus: plokk; 002_Tüüp: Air Space
AC_Pset_RenovationAndPhasing - Renovation Status: New

# IfcRailing: COLUMBIA KIVI (BETONEERITUD) 10 (6)
In: Teine korrus
Classification: 1.16 IfcRailingType (piire) (RKAS BIM + ARCHICAD Classification); Material: COLUMBIA KIVI (BETONEERITUD)
Pset_RailingCommon - Reference: COLUMBIA KIVI (BETONEERITUD); IsExternal: no
AR_001-002 - 001_Nimetus: TORULIFTI PIIRE; 002_Tüüp: COLUMBIA KIVI (BETONEERITUD)
AC_Pset_RenovationAndPhasing - Renovation Status: Existing

# IfcSlab: GENERIC - STRUCTURAL 300 (2)
In: Teine korrus
Type - PredefinedType: ROOF
Classification: 1.19 IfcSlabType.ROOF (katus) (RKAS BIM + ARCHICAD Classification); Material: GENERIC - STRUCTURAL 300 mm
Pset_SlabCommon - Reference: GENERIC - STRUCTURAL; LoadBearing: yes; IsExternal: yes
AR_Katus - 001_Nimetus: Varikatus; 205_Tüüp: GENERIC - STRUCTURAL; 325_Helipidavus: Undefined; 330_Tulekindlus: Undefined; 340_Soojusläbivus: 0; sets with these values: 2
AC_Pset_RenovationAndPhasing - Renovation Status: Existing

# IfcSlab: GKK-01_Geneeriline Katus/Koorik 465 (3)
Type - PredefinedType: ROOF
Classification: 1.19 IfcSlabType.ROOF (katus) (RKAS BIM + ARCHICAD Classification)
Pset_SlabCommon - Reference: GKK-01
AR_Katus - 001_Nimetus: KATUS; 205_Tüüp: GKK-01; 325_Helipidavus: Undefined; 330_Tulekindlus: Undefined; 340_Soojusläbivus: 0
AR_Vahelagi - 001_Nimetus: KATUS; 205_Tüüp: GKK-01; 325_Helipidavus: Undefined; 330_Tulekindlus: Undefined; 340_Soojusläbivus: 0
AC_Pset_RenovationAndPhasing - Renovation Status: New
Name | In | 520_Pindala (m2)
KATUS | Esimene korrus | 245.507
KATUS | Esimene korrus | 166.637
KATUS | Teine korrus | 219.102

# IfcSlab: GPK-01_Geneeriline Plaat/Katus 300 (2)
In: Teine korrus
Classification: 1.20 IfcSlabType (vahelagi) (RKAS BIM + ARCHICAD Classification)
Pset_SlabCommon - Reference: GPK-01; LoadBearing: yes; IsExternal: yes
AR_Katus - 001_Nimetus: VL-04; 205_Tüüp: GPK-01; 325_Helipidavus: Undefined; 330_Tulekindlus: Undefined; 340_Soojusläbivus: 0
AR_Vahelagi - 001_Nimetus: VL-04; 205_Tüüp: GPK-01; 325_Helipidavus: Undefined; 330_Tulekindlus: Undefined; 335_Välispiire: yes; 340_Soojusläbivus: 0; 505_Paksus: 300 mm; 500_Kandev: yes
AC_Pset_RenovationAndPhasing - Renovation Status: New
Name | 510_Bruto_pindala (m2) = 515_Neto_pindala (m2)
VL-04 | 22.2074
VL-04 | 44.4932

# IfcSlab: KON-04_Betoon - Konstuktsioon 315, KL-01
In: Teine korrus
Type - PredefinedType: ROOF
Classification: 1.19 IfcSlabType.ROOF (katus) (RKAS BIM + ARCHICAD Classification); Material: KON-04_Betoon - Konstuktsioon 315 mm
Pset_SlabCommon - Reference: KON-04; LoadBearing: yes; IsExternal: no
AR_Katus - 001_Nimetus: KL-01; 205_Tüüp: KON-04; 325_Helipidavus: Undefined; 330_Tulekindlus: Undefined; 340_Soojusläbivus: 0; sets with these values: 2
AC_Pset_RenovationAndPhasing - Renovation Status: New

# IfcSlab: P-01 PORAND PINNASEL 535 (12)
Type - PredefinedType: BASESLAB
Classification: Base Slab (RKAS BIM + ARCHICAD Classification)
Pset_SlabCommon - Reference: P-01 PORAND PINNASEL; LoadBearing: no; IsExternal: no
AR_Katus - 205_Tüüp: P-01 PORAND PINNASEL; 325_Helipidavus: Undefined; 330_Tulekindlus: Undefined; 340_Soojusläbivus: 0
AR_Vahelagi - 205_Tüüp: P-01 PORAND PINNASEL; 325_Helipidavus: Undefined; 330_Tulekindlus: Undefined; 335_Välispiire: no; 340_Soojusläbivus: 0; 505_Paksus: 535 mm; 500_Kandev: no
Name | In | AR_Katus, 001_Nimetus = AR_Vahelagi, 001_Nimetus | 510_Bruto_pindala (m2) | 515_Neto_pindala (m2) | Renovation Status
10 x PP-02 | Vundament | PP-02 | 0.27 | 0.27 | New
PP-02 | Esimene korrus | PP-02 | 401.173 | 391.273 | Existing
PP-01 | Esimene korrus | PP-01 | 449.185 | 449.185 | New

# IfcSlab: SBS Rullmaterjal, Vent pipe antifreeze-110
In: Teine korrus
Type - PredefinedType: ROOF
Description: Sewer component; Classification: 1.19 IfcSlabType.ROOF (katus) (RKAS BIM + ARCHICAD Classification); Material: SBS Rullmaterjal
Pset_SlabCommon - Reference: SBS Rullmaterjal
AR_Katus - 001_Nimetus: katusekalle; 205_Tüüp: SBS Rullmaterjal; 325_Helipidavus: Undefined; 330_Tulekindlus: Undefined; 340_Soojusläbivus: 0; sets with these values: 2
AC_Pset_RenovationAndPhasing - Renovation Status: Existing

# IfcSlab: VL-01 RB/OONESPANEEL 265 400, VL-01
In: Teine korrus
Classification: 1.20 IfcSlabType (vahelagi) (RKAS BIM + ARCHICAD Classification)
Pset_SlabCommon - Reference: VL-01 RB/OONESPANEEL 265; LoadBearing: yes; IsExternal: no
AR_Katus - 001_Nimetus: VL-01; 205_Tüüp: VL-01 RB/OONESPANEEL 265; 325_Helipidavus: Undefined; 330_Tulekindlus: Undefined; 340_Soojusläbivus: 0
AR_Vahelagi - 001_Nimetus: VL-01; 205_Tüüp: VL-01 RB/OONESPANEEL 265; 325_Helipidavus: Undefined; 330_Tulekindlus: Undefined; 335_Välispiire: no; 340_Soojusläbivus: 0; 505_Paksus: 400 mm; 510_Bruto_pindala: 445.006 m2; 515_Neto_pindala: 438.941 m2; 500_Kandev: yes
AC_Pset_RenovationAndPhasing - Renovation Status: Existing

# IfcSlab: VL-01 RB/OONESPANEEL 265 soojustusega 601, VL-02
In: Esimene korrus
Classification: 1.20 IfcSlabType (vahelagi) (RKAS BIM + ARCHICAD Classification)
Pset_SlabCommon - Reference: VL-01 RB/OONESPANEEL 265 soojustusega; LoadBearing: yes; IsExternal: yes
AR_Katus - 001_Nimetus: VL-02; 205_Tüüp: VL-01 RB/OONESPANEEL 265 soojustusega; 325_Helipidavus: Undefined; 330_Tulekindlus: Undefined; 340_Soojusläbivus: 0
AR_Vahelagi - 001_Nimetus: VL-02; 205_Tüüp: VL-01 RB/OONESPANEEL 265 soojustusega; 325_Helipidavus: Undefined; 330_Tulekindlus: Undefined; 335_Välispiire: yes; 340_Soojusläbivus: 0; 505_Paksus: 601 mm; 510_Bruto_pindala: 14.5042 m2; 515_Neto_pindala: 14.2505 m2; 500_Kandev: yes
AC_Pset_RenovationAndPhasing - Renovation Status: New

# IfcSlab: Vahtpolüstüreen (4) (2)
Type - PredefinedType: ROOF
Classification: 1.19 IfcSlabType.ROOF (katus) (RKAS BIM + ARCHICAD Classification); Material: Vahtpolüstüreen (4)
Pset_SlabCommon - Reference: Vahtpolüstüreen (4)
AR_Katus - 001_Nimetus: KATUSEKALDED; 205_Tüüp: Vahtpolüstüreen (4); 325_Helipidavus: Undefined; 330_Tulekindlus: Undefined; 340_Soojusläbivus: 0; sets with these values: 2
Name | In | Renovation Status
KATUSEKALDED | Katusekorrus | Existing
KATUSEKALDED | 4. Story | New

# IfcStair (2)
In: Esimene korrus
Classification: 1.22 IfcStair (trepp) (RKAS BIM + ARCHICAD Classification)
Pset_StairCommon - NumberOfRiser: 21; NumberOfTreads: 21; RiserHeight: 171.429 mm; RequiredHeadroom: 2200 mm
AR_001-002 - 001_Nimetus: TREPP
AC_Pset_RenovationAndPhasing - Renovation Status: New
Name | Reference = 002_Tüüp
TREPP | TREPP: 171 ( R ) ; 275 ( G ) ; KÄIGUTEE: 6 900
TREPP | TREPP: 171 ( R ) ; 270 ( G ) ; KÄIGUTEE: 5 670

# IfcWall: A-SS01 260 (5)
Classification: 1.24 IfcWallType (sein) (RKAS BIM + ARCHICAD Classification)
Pset_WallCommon - Reference: A-SS01; LoadBearing: yes; IsExternal: yes
AR_Sein - 205_Tüüp: A-SS01; 325_Helipidavus: Undefined; 330_Tulekindlus: Undefined; 335_Välispiire: yes; 340_Soojusläbivus: 0; 376_Viimistlus_väljast: Telje poolne pind: Paint-03; Telje vastaspoolne pind: Paint-03; 505_Paksus: 260 mm; 376_Viimistlus_väljast (MUDELIS): Krohv; COLUMBIA KIVI; Krohv; 500_Kandev: yes
AC_Pset_RenovationAndPhasing - Renovation Status: New
Name | In | 001_Nimetus | 605_Neto_pindala (m2) | 600_Bruto_pindala (m2)
VS-06 | Esimene korrus | VS-06 | 7.88263 | 21.1472
VS-07 | Teine korrus | VS-07 | 18.6813 | 18.6813
VS-07 | Teine korrus | VS-07 | 20.7488 | 20.7826
VS-07 | Teine korrus | VS-07 | 25.3742 | 25.4046
VS-07 | Teine korrus | VS-07 | 25.3404 | 25.4046

# IfcWall: A-SS01 260 (3)
In: Esimene korrus
Type - ElementType: PARTITIONING; PredefinedType: USERDEFINED
Classification: Partitioning Wall (RKAS BIM + ARCHICAD Classification)
Pset_WallCommon - Reference: A-SS01; LoadBearing: yes; IsExternal: yes
AR_Sein - 001_Nimetus: SISESEIN; 205_Tüüp: A-SS01; 325_Helipidavus: Undefined; 330_Tulekindlus: Undefined; 335_Välispiire: yes; 376_Viimistlus_väljast: Telje poolne pind: Paint-03; Telje vastaspoolne pind: Paint-03; 505_Paksus: 260 mm; 376_Viimistlus_väljast (MUDELIS): Krohv; COLUMBIA KIVI; Krohv; 500_Kandev: yes
AC_Pset_RenovationAndPhasing - Renovation Status: New
Name | 605_Neto_pindala (m2) | 600_Bruto_pindala (m2)
ASS-01 | 9.37324 | 15.2364
ASS-01 | 44.3549 | 53.5573
ASS-01 | 13.4756 | 16.0638

# IfcWall: A-SS02 200 (2)
In: Esimene korrus
Type - ElementType: PARTITIONING; PredefinedType: USERDEFINED
Classification: Partitioning Wall (RKAS BIM + ARCHICAD Classification)
Pset_WallCommon - Reference: A-SS02; LoadBearing: yes; IsExternal: yes
AR_Sein - 001_Nimetus: SISESEIN; 205_Tüüp: A-SS02; 325_Helipidavus: Undefined; 330_Tulekindlus: Undefined; 335_Välispiire: yes; 376_Viimistlus_väljast: Telje poolne pind: Paint-03; Telje vastaspoolne pind: Paint-03; 505_Paksus: 200 mm; 376_Viimistlus_väljast (MUDELIS): Krohv; COLUMBIA KIVI; Krohv; 500_Kandev: yes
AC_Pset_RenovationAndPhasing - Renovation Status: New
Name | 605_Neto_pindala (m2) | 600_Bruto_pindala (m2)
ASS-01 | 5.43156 | 10.9294
ASS-01 | 6.22227 | 8.41026

# IfcWall: A-VS01 497, A-VS02
In: Esimene korrus
Classification: 1.24 IfcWallType (sein) (RKAS BIM + ARCHICAD Classification)
Pset_WallCommon - Reference: A-VS01; LoadBearing: yes; IsExternal: yes
AR_Sein - 001_Nimetus: VÄLISSEIN; 205_Tüüp: A-VS01; 325_Helipidavus: Undefined; 330_Tulekindlus: REI-M 120; 335_Välispiire: yes; 340_Soojusläbivus: 1.1; 376_Viimistlus_väljast: Telje poolne pind: Paint-03; Telje vastaspoolne pind: Paint-03; 505_Paksus: 497 mm; 605_Neto_pindala: 71.0346 m2; 600_Bruto_pindala: 72.4546 m2; 376_Viimistlus_väljast (MUDELIS): Krohv; COLUMBIA KIVI; Mineraalvill; COLUMBIA KIVI; Krohv; 500_Kandev: yes
AC_Pset_RenovationAndPhasing - Renovation Status: New

# IfcWall: A-VS01a 547, VS-06
In: Esimene korrus
Classification: 1.24 IfcWallType (sein) (RKAS BIM + ARCHICAD Classification)
Pset_WallCommon - Reference: A-VS01a; LoadBearing: yes; IsExternal: yes
AR_Sein - 001_Nimetus: VS-06; 205_Tüüp: A-VS01a; 325_Helipidavus: Undefined; 330_Tulekindlus: Undefined; 335_Välispiire: yes; 340_Soojusläbivus: 0; 376_Viimistlus_väljast: Telje poolne pind: Paint-03; Telje vastaspoolne pind: Paint-03; 505_Paksus: 547 mm; 605_Neto_pindala: 37.2702 m2; 600_Bruto_pindala: 38.0675 m2; 376_Viimistlus_väljast (MUDELIS): Krohv; COLUMBIA KIVI; Mineraalvill; COLUMBIA KIVI; Krohv; 500_Kandev: yes
AC_Pset_RenovationAndPhasing - Renovation Status: New

# IfcWall: A-VS01b 350 (2)
In: Esimene korrus
Classification: 1.24 IfcWallType (sein) (RKAS BIM + ARCHICAD Classification)
Pset_WallCommon - Reference: A-VS01b; LoadBearing: yes; IsExternal: yes
AR_Sein - 205_Tüüp: A-VS01b; 325_Helipidavus: Undefined; 330_Tulekindlus: Undefined; 335_Välispiire: yes; 376_Viimistlus_väljast: Telje poolne pind: Paint-03; Telje vastaspoolne pind: Paint-03; 505_Paksus: 350 mm; 376_Viimistlus_väljast (MUDELIS): Krohv; COLUMBIA KIVI; Mineraalvill; Krohv; 500_Kandev: yes
AC_Pset_RenovationAndPhasing - Renovation Status: New
Name | 001_Nimetus | 340_Soojusläbivus | 605_Neto_pindala (m2) | 600_Bruto_pindala (m2)
VS-04 | VÄLISSEIN | 1.1 | 64.6832 | 86.3239
VS-06 | VS-06 | 0 | 53.0419 | 56.3584

# IfcWall: A-VS02 250 (6)
In: Esimene korrus
Classification: 1.24 IfcWallType (sein) (RKAS BIM + ARCHICAD Classification)
Pset_WallCommon - Reference: A-VS02; LoadBearing: yes; IsExternal: yes
AR_Sein - 205_Tüüp: A-VS02; 325_Helipidavus: Undefined; 335_Välispiire: yes; 376_Viimistlus_väljast: Telje poolne pind: Paint-03; Telje vastaspoolne pind: Paint-03; 505_Paksus: 250 mm; 376_Viimistlus_väljast (MUDELIS): Krohv; COLUMBIA KIVI (BETONEERITUD); Krohv; 500_Kandev: yes
AC_Pset_RenovationAndPhasing - Renovation Status: New
Name | 001_Nimetus | 330_Tulekindlus | 340_Soojusläbivus | 605_Neto_pindala (m2) | 600_Bruto_pindala (m2)
VS-06 | VS-06 | Undefined | 0 | 73.64 | 73.668
VS-04 | VÄLISSEIN | Undefined | 1.1 | 50.3532 | 135.753
A-VS02 | VÄLISSEIN | REI-M 120 | 1.1 | 97.6619 | 99.3855
A-VS01 | VÄLISSEIN | Undefined | 1.1 | 36.7148 | 37.4648
VS-04 | VÄLISSEIN | Undefined | 1.1 | 7.9406 | 10.7585
A-VS02 | VÄLISSEIN | REI-M 120 | 1.1 | 135.781 | 135.809

# IfcWall: MISSING, Vent pipe antifreeze-110
In: Esimene korrus
Type - ElementType: PARTITIONING; PredefinedType: USERDEFINED
Description: Sewer component; Classification: 1311 Vaheseinad (Talo 2000 - ehitiseosade liigitus); Partitioning Wall (RKAS BIM + ARCHICAD Classification)
Pset_WallCommon - Reference: MISSING; LoadBearing: no; IsExternal: no
AR_Sein - 001_Nimetus: SS-02; 205_Tüüp: MISSING; 325_Helipidavus: Undefined; 330_Tulekindlus: Undefined; 335_Välispiire: no; 340_Soojusläbivus: 0; 500_Kandev: no
AC_Pset_RenovationAndPhasing - Renovation Status: New

# IfcWall: SS-03 (COLUMBIA 140) 140, SS-14
In: Esimene korrus
Type - ElementType: PARTITIONING; PredefinedType: USERDEFINED
Classification: 1311 Vaheseinad (Talo 2000 - ehitiseosade liigitus); Partitioning Wall (RKAS BIM + ARCHICAD Classification); Material: Kergplokk
Pset_WallCommon - Reference: SS-03 (COLUMBIA 140); LoadBearing: no; IsExternal: no
AR_Sein - 001_Nimetus: SISESEIN; 205_Tüüp: SS-03 (COLUMBIA 140); 325_Helipidavus: Undefined; 330_Tulekindlus: Undefined; 335_Välispiire: no; 376_Viimistlus_väljast: Telje poolne pind: Krohv; Telje vastaspoolne pind: Krohv; 505_Paksus: 140 mm; 605_Neto_pindala: 0.228399 m2; 600_Bruto_pindala: 2.25366 m2; 376_Viimistlus_väljast (MUDELIS): Kergplokk; 500_Kandev: no
AC_Pset_RenovationAndPhasing - Renovation Status: New

# IfcWall: SS-07 LEILIRUUMI SEIN 297 (6)
In: Teine korrus
Type - ElementType: PARTITIONING; PredefinedType: USERDEFINED
Classification: Partitioning Wall (RKAS BIM + ARCHICAD Classification)
Pset_WallCommon - Reference: SS-07 LEILIRUUMI SEIN; LoadBearing: no; IsExternal: no
AR_Sein - 001_Nimetus: SISESEIN; 205_Tüüp: SS-07 LEILIRUUMI SEIN; 325_Helipidavus: Undefined; 330_Tulekindlus: Undefined; 335_Välispiire: no; 376_Viimistlus_väljast: Telje poolne pind: Siding - Dark; Telje vastaspoolne pind: _Columbia_puhasvuuk; 505_Paksus: 297 mm; 376_Viimistlus_väljast (MUDELIS): Laudis; Air Space; Air Space; Air Space; COLUMBIA KIVI (BETONEERITUD); 500_Kandev: no
AC_Pset_RenovationAndPhasing - Renovation Status: New
Name | 605_Neto_pindala (m2) | 600_Bruto_pindala (m2)
SS-07 | 6.22717 | 8.5536
SS-07 | 5.84107 | 8.5536
SS-07 | 4.85947 | 7.45789
SS-07 | 5.10205 | 8.44689
SS-07 | 5.18205 | 8.57489
SS-07 | 4.42537 | 7.13789

# IfcWall: VS- SOKKEL 500 (8)
In: Vundament
Classification: 1.24 IfcWallType (sein) (RKAS BIM + ARCHICAD Classification)
Pset_WallCommon - Reference: VS- SOKKEL; LoadBearing: yes; IsExternal: yes
AR_Sein - 001_Nimetus: VS-SOKKEL; 205_Tüüp: VS- SOKKEL; 325_Helipidavus: Undefined; 330_Tulekindlus: Undefined; 335_Välispiire: yes; 340_Soojusläbivus: 0; 376_Viimistlus_väljast: Telje poolne pind: _Maxwell_Generic_concrete; Telje vastaspoolne pind: _Maxwell_Generic_concrete; 505_Paksus: 500 mm; 376_Viimistlus_väljast (MUDELIS): Vahtpolüstüreen (4); Concrete, Cast In Situ; Vahtpolüstüreen (4); Vahtpolüstüreen (4); 500_Kandev: yes
AC_Pset_RenovationAndPhasing - Renovation Status: New
Name | 605_Neto_pindala (m2) | 600_Bruto_pindala (m2)
VS-SOKKEL | 7.5255 | 13.44
VS-SOKKEL | 3.33044 | 6.09032
VS-SOKKEL | 9.77484 | 16.6606
VS-SOKKEL | 33.3412 | 55.2226
VS-SOKKEL | 26.9402 | 44.3026
VS-SOKKEL | 17.7754 | 30.0294
VS-SOKKEL | 11.2445 | 19.4592
VS-SOKKEL | 1.211 | 2.52

# IfcWall: VS-01 430 (16)
Classification: 1.24 IfcWallType (sein) (RKAS BIM + ARCHICAD Classification)
Pset_WallCommon - Reference: VS-01; LoadBearing: yes; IsExternal: yes
AR_Sein - 001_Nimetus: VÄLISSEIN; 205_Tüüp: VS-01; 325_Helipidavus: Undefined; 330_Tulekindlus: Undefined; 335_Välispiire: yes; 340_Soojusläbivus: 1.1; 376_Viimistlus_väljast: BETOONIPIND MATRIITSI MUSTRIGA; 505_Paksus: 430 mm; 376_Viimistlus_väljast (MUDELIS): Raudbetoon Paneelid (2); Vahtpolüstüreen (4); Raudbetoon Paneelid (2); 500_Kandev: yes
Name | In | 605_Neto_pindala (m2) | 600_Bruto_pindala (m2) | Renovation Status
VS-01 | Esimene korrus | 28.8 | 29.088 | New
VS-01 | Esimene korrus | 33.5259 | 50.6139 | New
VS-01 | Esimene korrus | 24.6428 | 35.136 | New
VS-01 | Esimene korrus | 10.7888 | 15.4088 | New
VS-01 | Esimene korrus | 78.5129 | 113.669 | New
VS-01 | Esimene korrus | 4.788 | 6.228 | New
VS-01 | Esimene korrus | 27.2689 | 113.669 | New
VS-01 | Esimene korrus | 74.9865 | 77.7945 | New
VS-01 | Teine korrus | 3.04747 | 3.38227 | New
VS-01 | Teine korrus | 72.5291 | 72.5291 | Existing
VS-01 | Teine korrus | 84.5013 | 90.4361 | New
VS-01 | Teine korrus | 33.2011 | 40.5359 | New
VS-01 | Teine korrus | 74.3493 | 106.549 | New
VS-01 | Teine korrus | 16.1132 | 17.9127 | New
VS-01 | Teine korrus | 101.021 | 132.14 | New
VS-01 | Teine korrus | 30.376 | 40.8456 | New

# IfcWall: VS-02 480, VS-02
In: Esimene korrus
Classification: 1.24 IfcWallType (sein) (RKAS BIM + ARCHICAD Classification)
Pset_WallCommon - Reference: VS-02; LoadBearing: yes; IsExternal: yes
AR_Sein - 001_Nimetus: VÄLISSEIN; 205_Tüüp: VS-02; 325_Helipidavus: Undefined; 330_Tulekindlus: Undefined; 335_Välispiire: yes; 340_Soojusläbivus: 1.1; 376_Viimistlus_väljast: BETOONIPIND MATRIITSI MUSTRIGA; 505_Paksus: 480 mm; 605_Neto_pindala: 24.8014 m2; 600_Bruto_pindala: 42.5894 m2; 376_Viimistlus_väljast (MUDELIS): Raudbetoon Paneelid (2); Vahtpolüstüreen (4); Raudbetoon Paneelid (2); 500_Kandev: yes
AC_Pset_RenovationAndPhasing - Renovation Status: New

# IfcWall: VS-03 430, VS-03
In: Teine korrus
Classification: 1.24 IfcWallType (sein) (RKAS BIM + ARCHICAD Classification)
Pset_WallCommon - Reference: VS-03; LoadBearing: yes; IsExternal: yes
AR_Sein - 001_Nimetus: VÄLISSEIN; 205_Tüüp: VS-03; 325_Helipidavus: Undefined; 330_Tulekindlus: Undefined; 335_Välispiire: yes; 340_Soojusläbivus: 1.1; 376_Viimistlus_väljast: BETOONIPIND MATRIITSI MUSTRIGA; 505_Paksus: 430 mm; 605_Neto_pindala: 33.1377 m2; 600_Bruto_pindala: 54.7389 m2; 376_Viimistlus_väljast (MUDELIS): Raudbetoon Paneelid (2); Vahtpolüstüreen (4); Raudbetoon Paneelid (2); 500_Kandev: yes
AC_Pset_RenovationAndPhasing - Renovation Status: New

# IfcWallStandardCase: Concrete 300 (2)
In: Esimene korrus
Classification: 1.24 IfcWallType (sein) (RKAS BIM + ARCHICAD Classification); Material: Concrete 300 mm
Pset_WallCommon - Reference: Concrete; LoadBearing: yes; IsExternal: yes
AR_Sein - 001_Nimetus: VS-SOKKEL; 205_Tüüp: Concrete; 325_Helipidavus: Undefined; 330_Tulekindlus: Undefined; 335_Välispiire: yes; 340_Soojusläbivus: 0; 505_Paksus: 300 mm; 376_Viimistlus_väljast (MUDELIS): Concrete; 500_Kandev: yes
AC_Pset_RenovationAndPhasing - Renovation Status: New
Name | 376_Viimistlus_väljast | 605_Neto_pindala (m2) = 600_Bruto_pindala (m2)
VS-SOKKEL | Telje poolne pind: _Maxwell_Generic_concrete; Telje vastaspoolne pind: _Maxwell_Generic_concrete | 13.1683
VS-SOKKEL | Telje poolne pind: TOON: MUST, RR33; Telje vastaspoolne pind: TOON: MUST, RR33 | 0.164604

# IfcWallStandardCase: Kipsplaat (3) 24 (4)
Type - ElementType: PARTITIONING; PredefinedType: USERDEFINED
Classification: Partitioning Wall (RKAS BIM + ARCHICAD Classification); Material: Kipsplaat (3) 24 mm
Pset_WallCommon - Reference: Kipsplaat (3); LoadBearing: no; IsExternal: no
AR_Sein - 001_Nimetus: SISESEIN; 205_Tüüp: Kipsplaat (3); 325_Helipidavus: Undefined; 330_Tulekindlus: Undefined; 335_Välispiire: no; 376_Viimistlus_väljast: Telje poolne pind: _Columbia_puhasvuuk; Telje vastaspoolne pind: _Columbia_puhasvuuk; 505_Paksus: 24 mm; 376_Viimistlus_väljast (MUDELIS): Kipsplaat (3); 500_Kandev: no
AC_Pset_RenovationAndPhasing - Renovation Status: New
Name | In | 605_Neto_pindala (m2) | 600_Bruto_pindala (m2)
KIPSPLAAT | Esimene korrus | 3.584 | 4.8
KIPSPLAAT | Teine korrus | 7.03996 | 8.576
KIPSPLAAT | Teine korrus | 3.03998 | 3.52
KIPSPLAAT | Teine korrus | 3.06879 | 3.9968

# IfcWallStandardCase: Paroc paneel 200, VS-03
In: Teine korrus
Classification: 1.24 IfcWallType (sein) (RKAS BIM + ARCHICAD Classification); Material: Paroc paneel 200 mm
Pset_WallCommon - Reference: Paroc paneel; LoadBearing: no; IsExternal: no
AR_Sein - 001_Nimetus: VS-03; 205_Tüüp: Paroc paneel; 325_Helipidavus: Undefined; 330_Tulekindlus: Undefined; 335_Välispiire: no; 340_Soojusläbivus: 0; 376_Viimistlus_väljast: Telje poolne pind: _Columbia_puhasvuuk; Telje vastaspoolne pind: _Columbia_puhasvuuk; 505_Paksus: 200 mm; 605_Neto_pindala: 17.6815 m2; 600_Bruto_pindala: 19.8387 m2; 376_Viimistlus_väljast (MUDELIS): Paroc paneel; 500_Kandev: no
AC_Pset_RenovationAndPhasing - Renovation Status: New

# IfcWallStandardCase: Raudbetoon Paneelid 140 (2)
In: Esimene korrus
Classification: 1.24 IfcWallType (sein) (RKAS BIM + ARCHICAD Classification); Material: Raudbetoon Paneelid 140 mm
Pset_WallCommon - Reference: Raudbetoon Paneelid; LoadBearing: no; IsExternal: no
AR_Sein - 001_Nimetus: SS-03; 205_Tüüp: Raudbetoon Paneelid; 325_Helipidavus: Undefined; 330_Tulekindlus: Undefined; 335_Välispiire: no; 340_Soojusläbivus: 0; 376_Viimistlus_väljast: Telje poolne pind: _Maxwell_Generic_concrete; Telje vastaspoolne pind: _Maxwell_Generic_concrete; 505_Paksus: 140 mm; 605_Neto_pindala: 11.385 m2; 600_Bruto_pindala: 11.385 m2; 376_Viimistlus_väljast (MUDELIS): Raudbetoon Paneelid; 500_Kandev: no
AC_Pset_RenovationAndPhasing - Renovation Status: Existing

# IfcWallStandardCase: Raudbetoon Paneelid 200, SS-03
In: Esimene korrus
Type - ElementType: PARTITIONING; PredefinedType: USERDEFINED
Classification: Partitioning Wall (RKAS BIM + ARCHICAD Classification); Material: Raudbetoon Paneelid 200 mm
Pset_WallCommon - Reference: Raudbetoon Paneelid; LoadBearing: no; IsExternal: no
AR_Sein - 001_Nimetus: SISESEIN; 205_Tüüp: Raudbetoon Paneelid; 325_Helipidavus: Undefined; 330_Tulekindlus: Undefined; 335_Välispiire: no; 376_Viimistlus_väljast: Telje poolne pind: _Maxwell_Generic_concrete; Telje vastaspoolne pind: _Maxwell_Generic_concrete; 505_Paksus: 200 mm; 605_Neto_pindala: 4.524 m2; 600_Bruto_pindala: 4.5244 m2; 376_Viimistlus_väljast (MUDELIS): Raudbetoon Paneelid; 500_Kandev: no
AC_Pset_RenovationAndPhasing - Renovation Status: New

# IfcWallStandardCase: SS-01 240 (6)
Type - ElementType: PARTITIONING; PredefinedType: USERDEFINED
Material: COLUMBIA KIVI (BETONEERITUD) 240 mm
Pset_WallCommon - Reference: SS-01; LoadBearing: no; IsExternal: no
AR_Sein - 001_Nimetus: SISESEIN; 205_Tüüp: SS-01; 325_Helipidavus: Undefined; 335_Välispiire: no; 505_Paksus: 240 mm; 376_Viimistlus_väljast (MUDELIS): COLUMBIA KIVI (BETONEERITUD); 500_Kandev: no
AC_Pset_RenovationAndPhasing - Renovation Status: New
Name | In | Classification | 330_Tulekindlus | 376_Viimistlus_väljast | 605_Neto_pindala (m2) | 600_Bruto_pindala (m2)
SS-01 | Esimene korrus | 1311 Vaheseinad (Talo 2000 - ehitiseosade liigitus); Partitioning Wall (RKAS BIM + ARCHICAD Classification) | EI30 | Telje poolne pind: _Columbia_puhasvuuk; Telje vastaspoolne pind: _Columbia_puhasvuuk | 17.6579 | 25.9379
SS-01 | Esimene korrus | 1311 Vaheseinad (Talo 2000 - ehitiseosade liigitus); Partitioning Wall (RKAS BIM + ARCHICAD Classification) | EI30 | Telje poolne pind: _Columbia_puhasvuuk; Telje vastaspoolne pind: _Columbia_puhasvuuk | 4.77706 | 8.22306
SS-01 | Esimene korrus | 1311 Vaheseinad (Talo 2000 - ehitiseosade liigitus); Partitioning Wall (RKAS BIM + ARCHICAD Classification) | Undefined | Telje poolne pind: _Columbia_puhasvuuk; Telje vastaspoolne pind: _Columbia_puhasvuuk | 36.8081 | 42.5581
SS-01 | Esimene korrus | 1311 Vaheseinad (Talo 2000 - ehitiseosade liigitus); Partitioning Wall (RKAS BIM + ARCHICAD Classification) | Undefined | Telje poolne pind: _Columbia_puhasvuuk; Telje vastaspoolne pind: _Columbia_puhasvuuk | 2.96 | 4.8
SS-01 | Teine korrus | Partitioning Wall (RKAS BIM + ARCHICAD Classification); 0 TELLIJA KULUD (V1- EHITUSKULUDE LIIGITAMINE EVS 885:2005) | Undefined | Telje poolne pind: _Columbia_puhasvuuk; Telje vastaspoolne pind: Wood - Pine Grained Horizontal | 4.455 | 16.48
SS-01 | Teine korrus | Partitioning Wall (RKAS BIM + ARCHICAD Classification) | Undefined | Telje poolne pind: _Columbia_puhasvuuk; Telje vastaspoolne pind: _Columbia_puhasvuuk | 70.2974 | 101.039

# IfcWallStandardCase: SS-02 190 (44)
Type - ElementType: PARTITIONING; PredefinedType: USERDEFINED
Material: COLUMBIA KIVI (BETONEERITUD) 190 mm
Pset_WallCommon - Reference: SS-02; LoadBearing: no; IsExternal: no
AR_Sein - 001_Nimetus: SISESEIN; 205_Tüüp: SS-02; 325_Helipidavus: Undefined; 335_Välispiire: no; 505_Paksus: 190 mm; 376_Viimistlus_väljast (MUDELIS): COLUMBIA KIVI (BETONEERITUD); 500_Kandev: no
AC_Pset_RenovationAndPhasing - Renovation Status: New
Name | In | Classification | 330_Tulekindlus | 376_Viimistlus_väljast | 605_Neto_pindala (m2) | 600_Bruto_pindala (m2)
SS-02 | Esimene korrus | 1311 Vaheseinad (Talo 2000 - ehitiseosade liigitus); Partitioning Wall (RKAS BIM + ARCHICAD Classification) | Undefined | Telje poolne pind: Krohv; Telje vastaspoolne pind: Krohv | 15.4727 | 21.6787
SS-07 | Esimene korrus | 1311 Vaheseinad (Talo 2000 - ehitiseosade liigitus); Partitioning Wall (RKAS BIM + ARCHICAD Classification) | EI30 | Telje poolne pind: Krohv; Telje vastaspoolne pind: Krohv | 2.79725 | 2.79725
SS-02 | Esimene korrus | 1311 Vaheseinad (Talo 2000 - ehitiseosade liigitus); Partitioning Wall (RKAS BIM + ARCHICAD Classification) | Undefined | Telje poolne pind: Krohv; Telje vastaspoolne pind: Krohv | 10.9645 | 15.7085
SS-02 | Esimene korrus | 1311 Vaheseinad (Talo 2000 - ehitiseosade liigitus); Partitioning Wall (RKAS BIM + ARCHICAD Classification) | Undefined | Telje poolne pind: Krohv; Telje vastaspoolne pind: Krohv | 5.81559 | 7.19159
SS-02 | Esimene korrus | 1311 Vaheseinad (Talo 2000 - ehitiseosade liigitus); Partitioning Wall (RKAS BIM + ARCHICAD Classification) | Undefined | Telje poolne pind: Krohv; Telje vastaspoolne pind: Krohv | 6.35959 | 7.12759
SS-02 | Esimene korrus | 1311 Vaheseinad (Talo 2000 - ehitiseosade liigitus); Partitioning Wall (RKAS BIM + ARCHICAD Classification) | Undefined | Telje poolne pind: Krohv; Telje vastaspoolne pind: Krohv | 6.42359 | 7.19159
SS-02 | Esimene korrus | 1311 Vaheseinad (Talo 2000 - ehitiseosade liigitus); Partitioning Wall (RKAS BIM + ARCHICAD Classification) | EI30 | Telje poolne pind: Krohv; Telje vastaspoolne pind: Krohv | 24.1587 | 26.3027
SS-02 | Esimene korrus | 1311 Vaheseinad (Talo 2000 - ehitiseosade liigitus); Partitioning Wall (RKAS BIM + ARCHICAD Classification) | EI30 | Telje poolne pind: _Columbia_puhasvuuk; Telje vastaspoolne pind: _Columbia_puhasvuuk | 24.1587 | 26.3027
SS-02 | Esimene korrus | 1311 Vaheseinad (Talo 2000 - ehitiseosade liigitus); Partitioning Wall (RKAS BIM + ARCHICAD Classification) | EI30 | Telje poolne pind: Krohv; Telje vastaspoolne pind: Krohv | 19.264 | 19.264
SS-02 | Esimene korrus | 1311 Vaheseinad (Talo 2000 - ehitiseosade liigitus); Partitioning Wall (RKAS BIM + ARCHICAD Classification) | EI30 | Telje poolne pind: Krohv; Telje vastaspoolne pind: _Columbia_puhasvuuk | 22.9239 | 26.3699
2 x SS-02 | Esimene korrus | 1311 Vaheseinad (Talo 2000 - ehitiseosade liigitus); Partitioning Wall (RKAS BIM + ARCHICAD Classification) | Undefined | Telje poolne pind: Krohv; Telje vastaspoolne pind: Krohv | 12.032 | 14.016
SS-02 | Esimene korrus | 1311 Vaheseinad (Talo 2000 - ehitiseosade liigitus); Partitioning Wall (RKAS BIM + ARCHICAD Classification) | Undefined | Telje poolne pind: Krohv; Telje vastaspoolne pind: Krohv | 18.9919 | 31.0999
SS-03 | Esimene korrus | 1311 Vaheseinad (Talo 2000 - ehitiseosade liigitus); Partitioning Wall (RKAS BIM + ARCHICAD Classification) | Undefined | Telje poolne pind: Krohv; Telje vastaspoolne pind: Krohv | 6.144 | 7.84
SS-07 | Esimene korrus | 1311 Vaheseinad (Talo 2000 - ehitiseosade liigitus); Partitioning Wall (RKAS BIM + ARCHICAD Classification) | Undefined | Telje poolne pind: Krohv; Telje vastaspoolne pind: Krohv | 5.408 | 7.264
SS-02 | Esimene korrus | 1311 Vaheseinad (Talo 2000 - ehitiseosade liigitus); Partitioning Wall (RKAS BIM + ARCHICAD Classification) | EI30 | Telje poolne pind: Krohv; Telje vastaspoolne pind: Krohv | 30.1096 | 38.0646
SS-02 | Esimene korrus | 1311 Vaheseinad (Talo 2000 - ehitiseosade liigitus); Partitioning Wall (RKAS BIM + ARCHICAD Classification) | Undefined | Telje poolne pind: Krohv; Telje vastaspoolne pind: Krohv | 7.468 | 11.808
SS-02 | Esimene korrus | 1311 Vaheseinad (Talo 2000 - ehitiseosade liigitus); Partitioning Wall (RKAS BIM + ARCHICAD Classification) | EI30 | Telje poolne pind: _Columbia_puhasvuuk; Telje vastaspoolne pind: _Columbia_puhasvuuk | 27.7803 | 42.7808
SS-02 | Esimene korrus | 1311 Vaheseinad (Talo 2000 - ehitiseosade liigitus); Partitioning Wall (RKAS BIM + ARCHICAD Classification) | Undefined | Telje poolne pind: Krohv; Telje vastaspoolne pind: Krohv | 8.48 | 10.016
SS-03 | Esimene korrus | 1311 Vaheseinad (Talo 2000 - ehitiseosade liigitus); Partitioning Wall (RKAS BIM + ARCHICAD Classification) | EI30 | Telje poolne pind: Krohv; Telje vastaspoolne pind: Krohv | 11.232 | 11.84
SS-02 | Esimene korrus | 1311 Vaheseinad (Talo 2000 - ehitiseosade liigitus); Partitioning Wall (RKAS BIM + ARCHICAD Classification) | Undefined | Telje poolne pind: Krohv; Telje vastaspoolne pind: Krohv | 15.1437 | 18.9597
SS-02 | Esimene korrus | 1311 Vaheseinad (Talo 2000 - ehitiseosade liigitus); Partitioning Wall (RKAS BIM + ARCHICAD Classification) | Undefined | Telje poolne pind: Krohv; Telje vastaspoolne pind: Krohv | 1.35214 | 2.56814
SS-02 | Esimene korrus | 1311 Vaheseinad (Talo 2000 - ehitiseosade liigitus); Partitioning Wall (RKAS BIM + ARCHICAD Classification) | Undefined | Telje poolne pind: Krohv; Telje vastaspoolne pind: Krohv | 13.81 | 18.784
SS-02 | Esimene korrus | 1311 Vaheseinad (Talo 2000 - ehitiseosade liigitus); Partitioning Wall (RKAS BIM + ARCHICAD Classification) | Undefined | Telje poolne pind: Krohv; Telje vastaspoolne pind: Krohv | 12.078 | 17.056
SS-03 | Esimene korrus | 1311 Vaheseinad (Talo 2000 - ehitiseosade liigitus); Partitioning Wall (RKAS BIM + ARCHICAD Classification) | EI30 | Telje poolne pind: Krohv; Telje vastaspoolne pind: Krohv | 7.90466 | 8.54849
SS-02 | Esimene korrus | 1311 Vaheseinad (Talo 2000 - ehitiseosade liigitus); Partitioning Wall (RKAS BIM + ARCHICAD Classification) | Undefined | Telje poolne pind: Krohv; Telje vastaspoolne pind: Krohv | 2.39415 | 7.75015
SS-02 | Esimene korrus | 1311 Vaheseinad (Talo 2000 - ehitiseosade liigitus); Partitioning Wall (RKAS BIM + ARCHICAD Classification) | EI30 | Telje poolne pind: Krohv; Telje vastaspoolne pind: Krohv | 4.89993 | 6.72393
SS-02 | Esimene korrus | 1311 Vaheseinad (Talo 2000 - ehitiseosade liigitus); Partitioning Wall (RKAS BIM + ARCHICAD Classification) | Undefined | Telje poolne pind: Krohv; Telje vastaspoolne pind: Krohv | 3.74559 | 7.19159
SS-02 | Esimene korrus | 1311 Vaheseinad (Talo 2000 - ehitiseosade liigitus); Partitioning Wall (RKAS BIM + ARCHICAD Classification) | EI30 | Telje poolne pind: Krohv; Telje vastaspoolne pind: Krohv | 17.7991 | 19.1751
SS-02 | Esimene korrus | 1311 Vaheseinad (Talo 2000 - ehitiseosade liigitus); Partitioning Wall (RKAS BIM + ARCHICAD Classification) | Undefined | Telje poolne pind: Krohv; Telje vastaspoolne pind: Krohv | 39.0165 | 42.9925
SS-02 | Teine korrus | Partitioning Wall (RKAS BIM + ARCHICAD Classification) | Undefined | Telje poolne pind: Krohv; Telje vastaspoolne pind: Krohv | 1.17 | 5.376
SS-05 | Teine korrus | Partitioning Wall (RKAS BIM + ARCHICAD Classification) | Undefined | Telje poolne pind: _Columbia_puhasvuuk; Telje vastaspoolne pind: _Columbia_puhasvuuk | 15.5104 | 15.5104
SS-02 | Teine korrus | Partitioning Wall (RKAS BIM + ARCHICAD Classification) | Undefined | Telje poolne pind: Wood - Pine Grained Horizontal; Telje vastaspoolne pind: _Columbia_puhasvuuk | 23.595 | 42.2432
2 x SS-05 | Teine korrus | Partitioning Wall (RKAS BIM + ARCHICAD Classification) | Undefined | Telje poolne pind: Krohv; Telje vastaspoolne pind: Krohv | 12.032 | 14.016
SS-02 | Teine korrus | Partitioning Wall (RKAS BIM + ARCHICAD Classification) | Undefined | Telje poolne pind: _Columbia_puhasvuuk; Telje vastaspoolne pind: _Columbia_puhasvuuk | 18.4759 | 25.6019
SS-02 | Teine korrus | Partitioning Wall (RKAS BIM + ARCHICAD Classification) | Undefined | Telje poolne pind: Krohv; Telje vastaspoolne pind: Krohv | 19.7062 | 30.8991
SS-05 | Teine korrus | Partitioning Wall (RKAS BIM + ARCHICAD Classification) | Undefined | Telje poolne pind: _Columbia_puhasvuuk; Telje vastaspoolne pind: _Columbia_puhasvuuk | 13.9911 | 18.6995
SS-05 | Teine korrus | Partitioning Wall (RKAS BIM + ARCHICAD Classification) | Undefined | Telje poolne pind: Krohv; Telje vastaspoolne pind: Krohv | 16.2325 | 17.3205
SS-06 | Teine korrus | Partitioning Wall (RKAS BIM + ARCHICAD Classification) | Undefined | Telje poolne pind: Krohv; Telje vastaspoolne pind: Krohv | 5.472 | 6.08
SS-06 | Teine korrus | Partitioning Wall (RKAS BIM + ARCHICAD Classification) | Undefined | Telje poolne pind: Krohv; Telje vastaspoolne pind: Krohv | 16.2325 | 17.3525
SS-06 | Teine korrus | Partitioning Wall (RKAS BIM + ARCHICAD Classification) | Undefined | Telje poolne pind: _Columbia_puhasvuuk; Telje vastaspoolne pind: _Columbia_puhasvuuk | 8.8531 | 13.7715
SS-05 | Teine korrus | Partitioning Wall (RKAS BIM + ARCHICAD Classification) | Undefined | Telje poolne pind: Krohv; Telje vastaspoolne pind: Krohv | 12.7825 | 19.2405
SS-02 | Teine korrus | Partitioning Wall (RKAS BIM + ARCHICAD Classification) | Undefined | Telje poolne pind: Krohv; Telje vastaspoolne pind: Krohv | 1.17003 | 5.376

# IfcWallStandardCase: SS-03 (COLUMBIA 140) 140 (19)
Type - ElementType: PARTITIONING; PredefinedType: USERDEFINED
Material: Kergplokk 140 mm
Pset_WallCommon - Reference: SS-03 (COLUMBIA 140)
AR_Sein - 001_Nimetus: SISESEIN; 205_Tüüp: SS-03 (COLUMBIA 140); 325_Helipidavus: Undefined; 505_Paksus: 140 mm; 376_Viimistlus_väljast (MUDELIS): Kergplokk
AC_Pset_RenovationAndPhasing - Renovation Status: New
Name | In | Classification | LoadBearing = IsExternal = 335_Välispiire = 500_Kandev | 330_Tulekindlus | 376_Viimistlus_väljast | 605_Neto_pindala (m2) | 600_Bruto_pindala (m2)
SS-06 | Esimene korrus | 1311 Vaheseinad (Talo 2000 - ehitiseosade liigitus); Partitioning Wall (RKAS BIM + ARCHICAD Classification) | no | Undefined | Telje poolne pind: Krohv; Telje vastaspoolne pind: Krohv | 4.86493 | 5.47293
SS-13 | Esimene korrus | 1311 Vaheseinad (Talo 2000 - ehitiseosade liigitus); Partitioning Wall (RKAS BIM + ARCHICAD Classification) | no | Undefined | Telje poolne pind: Krohv; Telje vastaspoolne pind: Krohv | 0.974079 | 3.52739
ASS-01 | Esimene korrus | Partitioning Wall (RKAS BIM + ARCHICAD Classification) | yes | Undefined | Telje poolne pind: Paint-03; Telje vastaspoolne pind: Paint-03 | 5.07503 | 7.58959
SS-03 | Esimene korrus | 1311 Vaheseinad (Talo 2000 - ehitiseosade liigitus); Partitioning Wall (RKAS BIM + ARCHICAD Classification) | no | Undefined | Telje poolne pind: Krohv; Telje vastaspoolne pind: Krohv | 3.79389 | 7.19159
SS-03 | Esimene korrus | 1311 Vaheseinad (Talo 2000 - ehitiseosade liigitus); Partitioning Wall (RKAS BIM + ARCHICAD Classification) | no | EI30 | Telje poolne pind: Krohv; Telje vastaspoolne pind: Krohv | 5.024 | 6.08
SS-06 | Esimene korrus | 1311 Vaheseinad (Talo 2000 - ehitiseosade liigitus); Partitioning Wall (RKAS BIM + ARCHICAD Classification) | no | EI30 | Telje poolne pind: Krohv; Telje vastaspoolne pind: Krohv | 6.84706 | 8.22306
SS-03 | Esimene korrus | 1311 Vaheseinad (Talo 2000 - ehitiseosade liigitus); Partitioning Wall (RKAS BIM + ARCHICAD Classification) | no | Undefined | Telje poolne pind: Krohv; Telje vastaspoolne pind: Krohv | 13.77 | 17.824
ASS-01 | Esimene korrus | Partitioning Wall (RKAS BIM + ARCHICAD Classification) | yes | Undefined | Telje poolne pind: Paint-03; Telje vastaspoolne pind: Paint-03 | 3.92746 | 6.50428
SS-02 | Teine korrus | 1311 Vaheseinad (Talo 2000 - ehitiseosade liigitus); Partitioning Wall (RKAS BIM + ARCHICAD Classification) | no | Undefined | Telje poolne pind: Krohv; Telje vastaspoolne pind: Krohv | 6.08048 | 7.16848
SS-03 | Teine korrus | 1311 Vaheseinad (Talo 2000 - ehitiseosade liigitus); Partitioning Wall (RKAS BIM + ARCHICAD Classification) | no | Undefined | Telje poolne pind: Krohv; Telje vastaspoolne pind: Krohv | 3.07331 | 3.71331
SS-05 | Teine korrus | Partitioning Wall (RKAS BIM + ARCHICAD Classification) | no | Undefined | Telje poolne pind: _Columbia_puhasvuuk; Telje vastaspoolne pind: _Columbia_puhasvuuk | 20.1766 | 20.7846
SS-05 | Teine korrus | Partitioning Wall (RKAS BIM + ARCHICAD Classification) | no | Undefined | Telje poolne pind: _Columbia_puhasvuuk; Telje vastaspoolne pind: _Columbia_puhasvuuk | 12.9756 | 17.1036
SS-06 | Teine korrus | Partitioning Wall (RKAS BIM + ARCHICAD Classification) | no | Undefined | Telje poolne pind: _Columbia_puhasvuuk; Telje vastaspoolne pind: _Columbia_puhasvuuk | 28.0287 | 32.0827
SS-06 | Teine korrus | Partitioning Wall (RKAS BIM + ARCHICAD Classification) | no | Undefined | Telje poolne pind: _Columbia_puhasvuuk; Telje vastaspoolne pind: _Columbia_puhasvuuk | 10.2688 | 15.1872
SS-06 | Teine korrus | Partitioning Wall (RKAS BIM + ARCHICAD Classification) | no | Undefined | Telje poolne pind: _Columbia_puhasvuuk; Telje vastaspoolne pind: _Columbia_puhasvuuk | 7.52 | 8.576
SS-05 | Teine korrus | Partitioning Wall (RKAS BIM + ARCHICAD Classification) | no | Undefined | Telje poolne pind: _Columbia_puhasvuuk; Telje vastaspoolne pind: _Columbia_puhasvuuk | 13.6296 | 13.6296
SS-05 | Teine korrus | Partitioning Wall (RKAS BIM + ARCHICAD Classification) | no | Undefined | Telje poolne pind: _Columbia_puhasvuuk; Telje vastaspoolne pind: _Columbia_puhasvuuk | 1.6628 | 5.1008
SS-03 | Teine korrus | 1311 Vaheseinad (Talo 2000 - ehitiseosade liigitus); Partitioning Wall (RKAS BIM + ARCHICAD Classification) | no | Undefined | Telje poolne pind: Krohv; Telje vastaspoolne pind: Krohv | 2.62531 | 3.71331
SS-05 | Teine korrus | Partitioning Wall (RKAS BIM + ARCHICAD Classification) | no | Undefined | Telje poolne pind: _Columbia_puhasvuuk; Telje vastaspoolne pind: _Columbia_puhasvuuk | 1.218 | 4.656

# IfcWallStandardCase: SS-04 (FIBO 200) 200 (7)
Type - ElementType: PARTITIONING; PredefinedType: USERDEFINED
Classification: Partitioning Wall (RKAS BIM + ARCHICAD Classification); Material: Kergplokk 200 mm
Pset_WallCommon - Reference: SS-04 (FIBO 200); LoadBearing: no; IsExternal: no
AR_Sein - 001_Nimetus: SISESEIN; 205_Tüüp: SS-04 (FIBO 200); 325_Helipidavus: Undefined; 330_Tulekindlus: Undefined; 335_Välispiire: no; 376_Viimistlus_väljast: Telje poolne pind: Krohv; Telje vastaspoolne pind: Krohv; 505_Paksus: 200 mm; 376_Viimistlus_väljast (MUDELIS): Kergplokk; 500_Kandev: no
AC_Pset_RenovationAndPhasing - Renovation Status: New
Name | In | 605_Neto_pindala (m2) | 600_Bruto_pindala (m2)
SS-04 | Esimene korrus | 4.176 | 4.176
4 x SS-04 | Teine korrus | 12 | 14.016
SS-04 | Teine korrus | 7.84 | 7.84
SS-04 | Teine korrus | 35.7296 | 49.8236

# IfcWallStandardCase: SS-05 150 (2)
In: Esimene korrus
Type - ElementType: PARTITIONING; PredefinedType: USERDEFINED
Classification: 1311 Vaheseinad (Talo 2000 - ehitiseosade liigitus); Partitioning Wall (RKAS BIM + ARCHICAD Classification); Material: COLUMBIA KIVI (BETONEERITUD) 150 mm
Pset_WallCommon - Reference: SS-05; LoadBearing: no; IsExternal: no
AR_Sein - 001_Nimetus: SISESEIN; 205_Tüüp: SS-05; 325_Helipidavus: Undefined; 330_Tulekindlus: Undefined; 335_Välispiire: no; 376_Viimistlus_väljast: Telje poolne pind: Krohv; Telje vastaspoolne pind: Krohv; 505_Paksus: 150 mm; 376_Viimistlus_väljast (MUDELIS): COLUMBIA KIVI (BETONEERITUD); 500_Kandev: no
AC_Pset_RenovationAndPhasing - Renovation Status: New
Name | 605_Neto_pindala (m2) | 600_Bruto_pindala (m2)
SS-02 | 2.65731 | 3.13731
SS-02 | 1.96014 | 2.56814

# IfcWallStandardCase: SS-06 150 (6)
Type - ElementType: PARTITIONING; PredefinedType: USERDEFINED
Classification: Partitioning Wall (RKAS BIM + ARCHICAD Classification); Material: COLUMBIA KIVI (BETONEERITUD) 150 mm
Pset_WallCommon - Reference: SS-06; LoadBearing: no; IsExternal: no
AR_Sein - 001_Nimetus: SISESEIN; 205_Tüüp: SS-06; 325_Helipidavus: Undefined; 330_Tulekindlus: Undefined; 335_Välispiire: no; 505_Paksus: 150 mm; 376_Viimistlus_väljast (MUDELIS): COLUMBIA KIVI (BETONEERITUD); 500_Kandev: no
AC_Pset_RenovationAndPhasing - Renovation Status: New
Name | In | 376_Viimistlus_väljast | 605_Neto_pindala (m2) | 600_Bruto_pindala (m2)
SS-06 | Esimene korrus | Telje poolne pind: Krohv; Telje vastaspoolne pind: Krohv | 17.728 | 18.368
SS-06 | Teine korrus | Telje poolne pind: _Columbia_puhasvuuk; Telje vastaspoolne pind: _Columbia_puhasvuuk | 3.0688 | 3.9968
SS-06 | Teine korrus | Telje poolne pind: _Columbia_puhasvuuk; Telje vastaspoolne pind: _Columbia_puhasvuuk | 7.23089 | 8.44689
SS-06 | Teine korrus | Telje poolne pind: _Columbia_puhasvuuk; Telje vastaspoolne pind: _Columbia_puhasvuuk | 4.688 | 5.584
SS-06 | Teine korrus | Telje poolne pind: _Columbia_puhasvuuk; Telje vastaspoolne pind: _Columbia_puhasvuuk | 7.48688 | 8.09488
SS-06 | Teine korrus | Telje poolne pind: Krohv; Telje vastaspoolne pind: Krohv | 11.072 | 13.056

# IfcWallStandardCase: SS-08 KIHTPLAST 10mm 10 (2)
Type - ElementType: PARTITIONING; PredefinedType: USERDEFINED
Classification: Partitioning Wall (RKAS BIM + ARCHICAD Classification); Material: Kihtplast 10 mm
Pset_WallCommon - Reference: SS-08 KIHTPLAST 10mm; LoadBearing: no; IsExternal: no
AR_Sein - 001_Nimetus: SISESEIN; 205_Tüüp: SS-08 KIHTPLAST 10mm; 335_Välispiire: no; 376_Viimistlus_väljast: Telje poolne pind: Glass - Lamp; Telje vastaspoolne pind: Glass - Lamp; 505_Paksus: 10 mm; 376_Viimistlus_väljast (MUDELIS): Kihtplast; 500_Kandev: no
AC_Pset_RenovationAndPhasing - Renovation Status: New
Name | In | 605_Neto_pindala (m2) | 600_Bruto_pindala (m2)
SS-08 | Esimene korrus | 37.912 | 42.1472
SS-08 | Teine korrus | 40.4252 | 42.8452

# IfcWindow: Double Window 24 (8)
In: Teine korrus
Type - OperationType: DOUBLE_PANEL_VERTICAL; ParameterTakesPrecedence: no; Sizeable: no
Type - Window Lining Properties - LiningDepth: 50 mm; LiningThickness: 90 mm; MullionThickness: 90 mm; FirstMullionOffset: 0.482143
Type - Window Panel Properties - Panel 1 - OperationType: FIXEDCASEMENT; PanelPosition: LEFT
Type - Window Panel Properties - Panel 2 - OperationType: TILTANDTURNLEFTHAND; PanelPosition: RIGHT; FrameDepth: 50 mm; FrameThickness: 50 mm
OverallHeight: 2000 mm; OverallWidth: 1400 mm; Classification: 1.25 IfcWindowStyle (aken) (RKAS BIM + ARCHICAD Classification); 422 Alumiiniumaknad (V1- EHITUSKULUDE LIIGITAMINE EVS 885:2005)
Avatäited - 11 Vastupanu tulekoormusele: KLASS C3 (EVS-EN 12210: 2016); 05 Asukoha info: Väline avatäide; 17 Sulused, lukustus: AVANEV OSA VARUSTADA FIKSAATORIGA, KÄEPIDE (ASSA RUKOLINE VÕI ANALOOG, LKUJULINE ÜMARATE KATETEGA LINK, HARJATUD, ROOSTEVABA, OTS SIRGE) HARJATUD, ROOSTEVABA); 09 Õhuläbilaskvus: KLASS 4 (EVS-EN 12207: 2016); 14 Päikesekiirgus tegur (g-väärtus): g=0,55; VALGUSE LÄBIPAISTVUS 70%; 18 Viimistlus: LENG JA RAAM VÄLJAST: PULBERVÄRVITUD, TUMEHALL, RAL 7016; LENG JA RAAM SEEST: PULBERVÄRVITUD, TOON: TUMEHALL, RAL 7016
AR_Aken - 001_Nimetus: VÄLISAKEN; 310_Materjal: ALUMIINIUM; VIHMAVEE ÄRAVOOLUKS AKEN VARUSTADA TERASEST LISARAAMIGA, LEHTTERAS 5 MM, KALLE 5 KRAADI, TOON: TUMEHALL, RAL 7016. KUUMTSINGIKIHT VÄHEMALT 350 GR/M2. KINNITID PEAVAD OLEMA KORROSIOONIKINDLAD. AKENDE VT. JOONISEID AR-7-02 JA AR-8-82.; 375_Viimistlus_seest: PULBERVÄRVITUD, TUMEHALL, RAL 7016; 376_Viimistlus_väljast: PULBERVÄRVITUD, TUMEHALL, RAL 7016; 305_Ava_mõõt: 1 400x2 000; 315_Avanemine: PÖÖRD- JA KALDAVATAV, SISSEPOOLE, VASAK - Vasak ; ARCHICAD tüüp: Fixed Glass; 320_Klaas: 3X KLAASPAKETT, PAKETI VAHELIISTU TOON: TUMEHALL, RAL 7016; 325_Helipidavus: AKNA HELIPIDAVUS 38 dB/ PAKETI HELIPIDAVUS 30 dB; 330_Tulekindlus: nõudeid ei esitata; 335_Välispiire: yes; 340_Soojusläbivus: 0.82; 355_Pindala: 2.8 m2; 900_Tootja: SCHÜCO; 905_Mudel: AWS 90.SI+/ADS 90.SI; 910_Tooteinfo: LÄHTUDA TOOTJAFIRMA INFOLEHEST; 915_Kasutus-ja_hooldusjuhend: LÄHTUDA TOOTJAFIRMA INFOLEHEST
Pset_WindowCommon - ThermalTransmittance: 0; GlazingAreaFraction: 1.9386; IsExternal: yes
AC_Pset_RenovationAndPhasing - Renovation Status: New
Name | 03 Tähistus | 300_Tüüp = Reference | 345_Päikesekiirgus_tegur | 350_Klaaspakett
A-07 | A-07 | A-07 | g=0,38, VALGUSE LÄBIPAISTVUS 63% | 6MM SUNGUARD SN70/37 + 4 + 6MM SELEKTIIV / 14MM CHRU
6 x A-08 | A-03 | A-08 | g=0,55; VALGUSE LÄBIPAISTVUS 70% | 6 MM SELEKTIIV + 4 + 6 MM SELEKTIIV / 14mm ChrU
A-08 | A-08 | A-08 | g=0,55; VALGUSE LÄBIPAISTVUS 70% | 6 MM SELEKTIIV + 4 + 6 MM SELEKTIIV / 14mm ChrU

# IfcWindow: Double Window 24 (8)
In: Esimene korrus
Type - OperationType: DOUBLE_PANEL_VERTICAL; ParameterTakesPrecedence: no; Sizeable: no
Type - Window Lining Properties - LiningDepth: 50 mm; LiningThickness: 90 mm; MullionThickness: 90 mm; FirstMullionOffset: 0.482143
Type - Window Panel Properties - Panel 1 - OperationType: SIDEHUNGLEFTHAND; PanelPosition: RIGHT; FrameDepth: 50 mm; FrameThickness: 50 mm
Type - Window Panel Properties - Panel 2 - OperationType: FIXEDCASEMENT; PanelPosition: LEFT
OverallHeight: 2000 mm; OverallWidth: 1400 mm; Classification: 1.25 IfcWindowStyle (aken) (RKAS BIM + ARCHICAD Classification); 422 Alumiiniumaknad (V1- EHITUSKULUDE LIIGITAMINE EVS 885:2005)
Avatäited - 11 Vastupanu tulekoormusele: KLASS C3 (EVS-EN 12210: 2016); 17 Sulused, lukustus: AVANEV OSA VARUSTADA FIKSAATORIGA, KÄEPIDE (ASSA RUKOLINE VÕI ANALOOG, LKUJULINE ÜMARATE KATETEGA LINK, HARJATUD, ROOSTEVABA, OTS SIRGE) HARJATUD, ROOSTEVABA); 09 Õhuläbilaskvus: KLASS 4 (EVS-EN 12207: 2016); 14 Päikesekiirgus tegur (g-väärtus): g=0,55; VALGUSE LÄBIPAISTVUS 70%; 18 Viimistlus: LENG JA RAAM VÄLJAST: PULBERVÄRVITUD, TUMEHALL, RAL 7016; LENG JA RAAM SEEST: PULBERVÄRVITUD, TOON: TUMEHALL, RAL 7016; 05 Asukoha info: VÄLISFASSAAD, 1. KORRUS
AR_Aken - 375_Viimistlus_seest: PULBERVÄRVITUD, TUMEHALL, RAL 7016; 376_Viimistlus_väljast: PULBERVÄRVITUD, TUMEHALL, RAL 7016; 310_Materjal: ALUMIINIUM; VIHMAVEE ÄRAVOOLUKS AKEN VARUSTADA TERASEST LISARAAMIGA, LEHTTERAS 5 MM, KALLE 5 KRAADI, TOON: TUMEHALL, RAL 7016. KUUMTSINGIKIHT VÄHEMALT 350 GR/M2. KINNITID PEAVAD OLEMA KORROSIOONIKINDLAD. AKENDE VT. JOONISEID AR-7-02 JA AR-8-82.; 001_Nimetus: VÄLISAKEN; 300_Tüüp: A-05; 305_Ava_mõõt: 1 400x2 000; 315_Avanemine: PÖÖRDAVATAV, SISSEPOOLE, VASAK - Vasak ; ARCHICAD tüüp: Side Hung Mirrored; 320_Klaas: 3X KLAASPAKETT, PAKETI VAHELIISTU TOON: TUMEHALL, RAL 7016; 325_Helipidavus: AKNA HELIPIDAVUS 38 dB/ PAKETI HELIPIDAVUS 30 dB; 330_Tulekindlus: nõudeid ei esitata; 335_Välispiire: yes; 340_Soojusläbivus: 0.91; 345_Päikesekiirgus_tegur: g=0,55; VALGUSE LÄBIPAISTVUS 70%; 350_Klaaspakett: 6Sel+4+44.6Sel-18ChrU; 355_Pindala: 2.8 m2; 900_Tootja: SCHÜCO; 905_Mudel: AWS 90.SI+/ADS 90.SI; 910_Tooteinfo: LÄHTUDA TOOTJAFIRMA INFOLEHEST; 915_Kasutus-ja_hooldusjuhend: LÄHTUDA TOOTJAFIRMA INFOLEHEST
Pset_WindowCommon - Reference: A-05; ThermalTransmittance: 0; GlazingAreaFraction: 1.9386; IsExternal: yes
AC_Pset_RenovationAndPhasing - Renovation Status: New
Name | 03 Tähistus
7 x A-05 | A-03
A-05 | A-05

# IfcWindow: Horizontal Multi-Sash Window 24, A-11
In: Esimene korrus
Type - OperationType: USERDEFINED; ParameterTakesPrecedence: no; Sizeable: no
OverallHeight: 1600 mm; OverallWidth: 7000 mm; Classification: 1.25 IfcWindowStyle (aken) (RKAS BIM + ARCHICAD Classification); 422 Alumiiniumaknad (V1- EHITUSKULUDE LIIGITAMINE EVS 885:2005)
Avatäited - 18 Viimistlus: LENG JA RAAM VÄLJAST: PULBERVÄRVITUD, TUMEHALL, RAL 7016; LENG JA RAAM SEEST: PULBERVÄRVITUD, TOON: TUMEHALL, RAL 7016
AR_Aken - 001_Nimetus: VÄLISAKEN; 300_Tüüp: A-11; 305_Ava_mõõt: 7 000x1 600; 310_Materjal: MUDELIS: väljast PULBERVÄRVITUD, TOON: TUMEHALL, RAL 7016; PULBERVÄRVITUD, TOON: TUMEHALL, RAL 7016; seest PULBERVÄRVITUD, TOON: TUMEHALL, RAL 7016; PULBERVÄRVITUD, TOON: TUMEHALL, RAL 7016; MÄRKUS: ALUMIINIUM; 315_Avanemine: PÖÖRDAVATAV, SISSEPOOLE, VASAK JA PAREM ; ARCHICAD tüüp: Side Hung Mirrored; 320_Klaas: 3X KLAASPAKETT, PAKETI VAHELIISTU TOON: TUMEHALL, RAL 7016; 325_Helipidavus: AKNA HELIPIDAVUS 38 dB/ PAKETI HELIPIDAVUS 30 dB; 330_Tulekindlus: nõudeid ei esitata; 335_Välispiire: yes; 340_Soojusläbivus: 0.8; 345_Päikesekiirgus_tegur: g=0,55; VALGUSE LÄBIPAISTVUS 70%; 350_Klaaspakett: 6Sel+4+44.6Sel-18ChrU; 355_Pindala: 11.2 m2; 375_Viimistlus_seest: MUDELIS: PULBERVÄRVITUD, TOON: TUMEHALL, RAL 7016; PULBERVÄRVITUD, TOON: TUMEHALL, RAL 7016; MÄRKUS: PULBERVÄRVITUD, TUMEHALL, RAL 7016; 376_Viimistlus_väljast: MUDELIS: PULBERVÄRVITUD, TOON: TUMEHALL, RAL 7016; PULBERVÄRVITUD, TOON: TUMEHALL, RAL 7016; MÄRKUS: PULBERVÄRVITUD, TUMEHALL, RAL 7016; 900_Tootja: SCHÜCO; 905_Mudel: AWS 90.SI+/ADS 90.SI; 910_Tooteinfo: LÄHTUDA TOOTJAFIRMA INFOLEHEST; 915_Kasutus-ja_hooldusjuhend: LÄHTUDA TOOTJAFIRMA INFOLEHEST
Pset_WindowCommon - Reference: A-11; AcousticRating: 38dB/ 30 dB; ThermalTransmittance: 0; GlazingAreaFraction: 8.57168; IsExternal: yes
Pset_ManufacturerTypeInformation - Manufacturer: SCHÜCO/ AWS 90.SI VÕI SAMAVÄÄRNE ANALOOG
AC_Pset_RenovationAndPhasing - Renovation Status: New

# IfcWindow: Orivent savunpoistoluukut (3)
In: Katusekorrus
Type - ParameterTakesPrecedence: no; Sizeable: no
Classification: 1.25 IfcWindowStyle (aken) (RKAS BIM + ARCHICAD Classification); 415 Suitsuluugid, katusaknad (V1- EHITUSKULUDE LIIGITAMINE EVS 885:2005)
Avatäited - 01 Nimetus: Katuseluuk
AR_Aken - 375_Viimistlus_seest: TOON: HALL, RAL 7045; 376_Viimistlus_väljast: TOON: MUST, RR33; 310_Materjal: KUUMTSINGITUD PLEKK; 001_Nimetus: KATUSEAKEN; 300_Tüüp: KA-05; 305_Ava_mõõt: 1 800x1200; 315_Avanemine: AUTOMAATIKAGA AVATAV, 24 VDC; 320_Klaas: SELEKTIIV, ARGOONTÄITEGA; 325_Helipidavus: Undefined; 330_Tulekindlus: EI30; 335_Välispiire: yes; 340_Soojusläbivus: 1.26; 345_Päikesekiirgus_tegur: Undefined; 350_Klaaspakett: 3X; 900_Tootja: KERAPLAST; 905_Mudel: Orivent 51 lasi; 910_Tooteinfo: Undefined; 915_Kasutus-ja_hooldusjuhend: Undefined
Pset_WindowCommon - Reference: KA-05; ThermalTransmittance: 0; IsExternal: yes
AC_Pset_RenovationAndPhasing - Renovation Status: Existing

# IfcWindow: Skylight Dome Rect (5)
In: Katusekorrus
Type - ParameterTakesPrecedence: no; Sizeable: no
Classification: 1.25 IfcWindowStyle (aken) (RKAS BIM + ARCHICAD Classification); 415 Suitsuluugid, katusaknad (V1- EHITUSKULUDE LIIGITAMINE EVS 885:2005)
AR_Aken - 375_Viimistlus_seest: TOON: HALL, RAL 7045; 376_Viimistlus_väljast: TOON: MUST, RR33; 310_Materjal: KUUMTSINGITUD PLEKK; 001_Nimetus: KATUSEAKEN; 320_Klaas: AKRÜÜLPLASTIK; 325_Helipidavus: Undefined; 330_Tulekindlus: nõudeid ei esitata; 335_Välispiire: yes; 340_Soojusläbivus: 1.2; 345_Päikesekiirgus_tegur: Undefined; 350_Klaaspakett: 3X; 900_Tootja: KERAPLAST; 905_Mudel: M3; 910_Tooteinfo: VASTAVALT TOOTJAFIRMA INFOLEHELE; 915_Kasutus-ja_hooldusjuhend: VASTAVALT TOOTJAFIRMA INFOLEHELE
Pset_WindowCommon - ThermalTransmittance: 0; IsExternal: yes
AC_Pset_RenovationAndPhasing - Renovation Status: Existing
Name | 01 Nimetus | 300_Tüüp = Reference | 305_Ava_mõõt | 315_Avanemine
2 x KA-04 | Katuseluuk | KA-04 | 1 400x1200 | MITTEAVATAV
KA-01 |  | KA-01 | 950x950 | MITTEAVATAV
KA-03 | Katuseluuk | KA-03 | 1 200x1200 | MANUAALSELT AVATAV JA LUKUSTATAV
KA-02 | Katuseluuk | KA-02 | 1 200x1200 | MITTEAVATAV

# IfcWindow: Triple Window 24 (5)
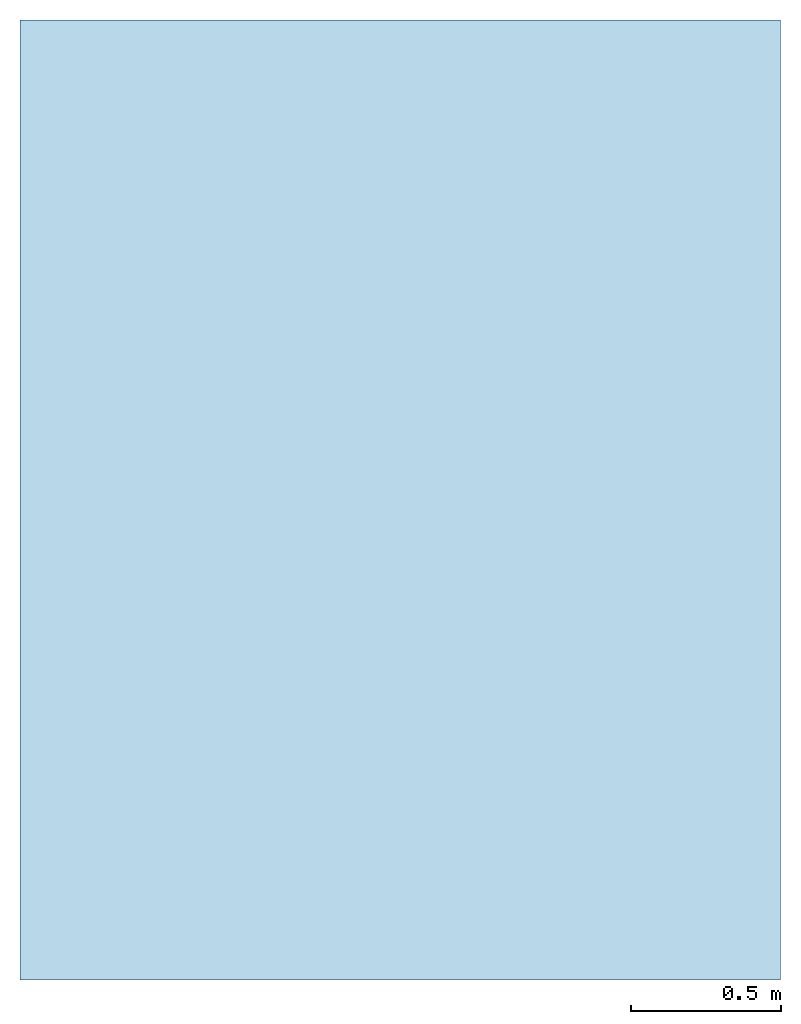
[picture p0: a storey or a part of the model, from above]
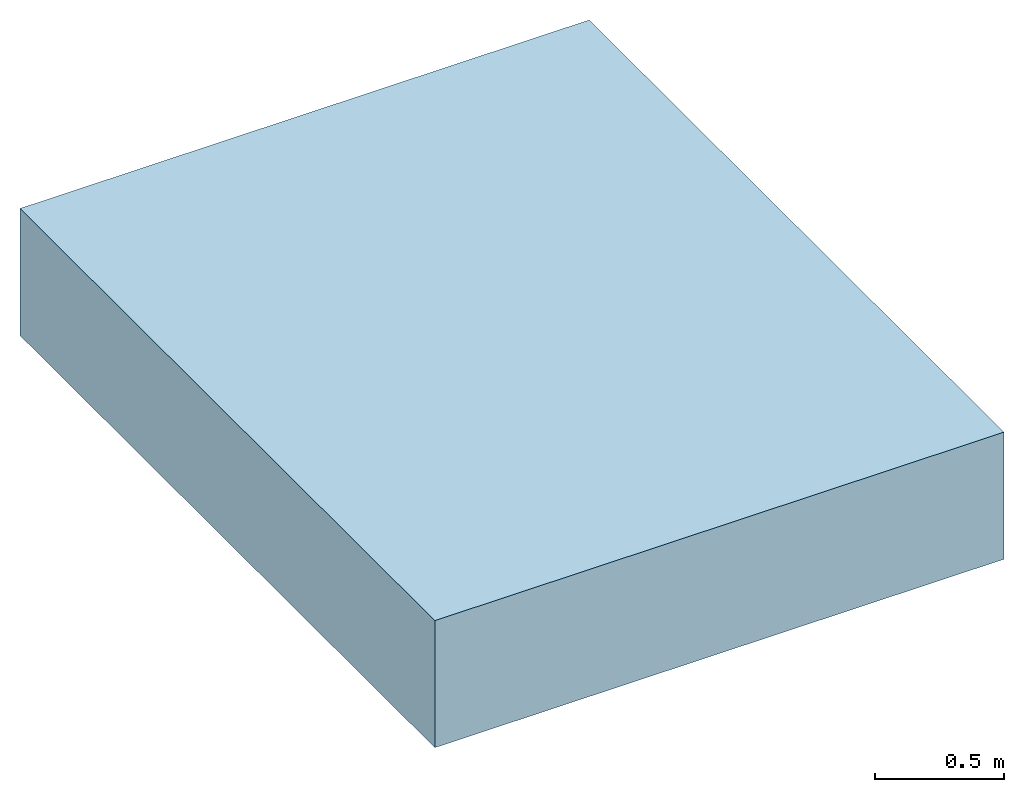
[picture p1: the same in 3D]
Properties of the parts of a building model (IFC2X3), part 4 of 4

# IfcWindow: Triple Window 24 (5)
In: Teine korrus
Type - OperationType: TRIPLE_PANEL_VERTICAL; ParameterTakesPrecedence: no; Sizeable: no
Type - Window Lining Properties - LiningDepth: 50 mm; LiningThickness: 90 mm; MullionThickness: 90 mm; FirstMullionOffset: 0.33254; SecondMullionOffset: 0.643651
Type - Window Panel Properties - Panel 1 - OperationType: FIXEDCASEMENT; PanelPosition: LEFT
Type - Window Panel Properties - Panel 2 - OperationType: FIXEDCASEMENT; PanelPosition: MIDDLE
Type - Window Panel Properties - Panel 3 - OperationType: TILTANDTURNLEFTHAND; PanelPosition: RIGHT; FrameDepth: 50 mm; FrameThickness: 50 mm
OverallHeight: 2000 mm; OverallWidth: 2100 mm; Classification: 1.25 IfcWindowStyle (aken) (RKAS BIM + ARCHICAD Classification); 422 Alumiiniumaknad (V1- EHITUSKULUDE LIIGITAMINE EVS 885:2005)
Avatäited - 10 Tulekindlus: nõudeid ei esitata; 05 Asukoha info: Väline avatäide; 17 Sulused, lukustus: AVANEV OSA VARUSTADA FIKSAATORIGA, KÄEPIDE (ASSA RUKOLINE VÕI ANALOOG, LKUJULINE ÜMARATE KATETEGA LINK, HARJATUD, ROOSTEVABA, OTS SIRGE) HARJATUD, ROOSTEVABA); 09 Õhuläbilaskvus: KLASS 4 (EVS-EN 12207: 2016); 14 Päikesekiirgus tegur (g-väärtus): g=0,55; VALGUSE LÄBIPAISTVUS 70%; 18 Viimistlus: LENG JA RAAM VÄLJAST: PULBERVÄRVITUD, TUMEHALL, RAL 7016; LENG JA RAAM SEEST: PULBERVÄRVITUD, TOON: TUMEHALL, RAL 7016
AR_Aken - 001_Nimetus: VÄLISAKEN; 310_Materjal: ALUMIINIUM; VIHMAVEE ÄRAVOOLUKS AKEN VARUSTADA TERASEST LISARAAMIGA, LEHTTERAS 5 MM, KALLE 5 KRAADI, TOON: TUMEHALL, RAL 7016. KUUMTSINGIKIHT VÄHEMALT 350 GR/M2. KINNITID PEAVAD OLEMA KORROSIOONIKINDLAD. AKENDE VT. JOONISEID AR-7-02 JA AR-8-82.; 375_Viimistlus_seest: PULBERVÄRVITUD, TUMEHALL, RAL 7016; 376_Viimistlus_väljast: PULBERVÄRVITUD, TUMEHALL, RAL 7016; 305_Ava_mõõt: 2 100x2 000; 315_Avanemine: PÖÖRD- JA KALDAVATAV, SISSEPOOLE, VASAK ; ARCHICAD tüüp: Fixed Glass; 320_Klaas: 3X KLAASPAKETT, PAKETI VAHELIISTU TOON: TUMEHALL, RAL 7016; 325_Helipidavus: AKNA HELIPIDAVUS 38 dB/ PAKETI HELIPIDAVUS 30 dB; 330_Tulekindlus: nõudeid ei esitata; 335_Välispiire: yes; 355_Pindala: 4.2 m2; 900_Tootja: SCHÜCO; 910_Tooteinfo: LÄHTUDA TOOTJAFIRMA INFOLEHEST; 915_Kasutus-ja_hooldusjuhend: LÄHTUDA TOOTJAFIRMA INFOLEHEST
Pset_WindowCommon - ThermalTransmittance: 0; GlazingAreaFraction: 3.04763; IsExternal: yes
AC_Pset_RenovationAndPhasing - Renovation Status: New
Name | 03 Tähistus | 300_Tüüp = Reference | 340_Soojusläbivus | 345_Päikesekiirgus_tegur | 350_Klaaspakett | 905_Mudel
A-06 | A-03 | A-06 | 0.86 | g=0,38, VALGUSE LÄBIPAISTVUS 63% | 6MM SUNGUARD SN70/37 + 4 + 6MM SELEKTIIV / 14MM CHRU | Undefined
4 x A-10 | A-10 | A-10 | 0.8 | g=0,55; VALGUSE LÄBIPAISTVUS 70% | 6 MM SELEKTIIV + 4 + 6 MM SELEKTIIV / 14mm ChrU | AWS 90.SI+/ADS 90.SI

# IfcWindow: Triple Window 24 (2)
In: Esimene korrus
Type - OperationType: TRIPLE_PANEL_VERTICAL; ParameterTakesPrecedence: no; Sizeable: no
Type - Window Lining Properties - LiningDepth: 50 mm; LiningThickness: 90 mm; MullionThickness: 90 mm; FirstMullionOffset: 0.33254; SecondMullionOffset: 0.643651
Type - Window Panel Properties - Panel 1 - OperationType: SIDEHUNGLEFTHAND; PanelPosition: RIGHT; FrameDepth: 50 mm; FrameThickness: 50 mm
Type - Window Panel Properties - Panel 2 - OperationType: FIXEDCASEMENT; PanelPosition: MIDDLE
Type - Window Panel Properties - Panel 3 - OperationType: FIXEDCASEMENT; PanelPosition: LEFT
OverallHeight: 2000 mm; OverallWidth: 2100 mm; Classification: 1.25 IfcWindowStyle (aken) (RKAS BIM + ARCHICAD Classification); 422 Alumiiniumaknad (V1- EHITUSKULUDE LIIGITAMINE EVS 885:2005)
Avatäited - 03 Tähistus: A-03; 17 Sulused, lukustus: AVANEV OSA VARUSTADA FIKSAATORIGA, KÄEPIDE (ASSA RUKOLINE VÕI ANALOOG, LKUJULINE ÜMARATE KATETEGA LINK, HARJATUD, ROOSTEVABA, OTS SIRGE) HARJATUD, ROOSTEVABA); 09 Õhuläbilaskvus: KLASS 4 (EVS-EN 12207: 2016); 14 Päikesekiirgus tegur (g-väärtus): g=0,55; VALGUSE LÄBIPAISTVUS 70%; 18 Viimistlus: LENG JA RAAM VÄLJAST: PULBERVÄRVITUD, TUMEHALL, RAL 7016; LENG JA RAAM SEEST: PULBERVÄRVITUD, TOON: TUMEHALL, RAL 7016; 05 Asukoha info: VÄLISFASSAAD, 1. KORRUS
AR_Aken - 001_Nimetus: VÄLISAKEN; 375_Viimistlus_seest: PULBERVÄRVITUD, TUMEHALL, RAL 7016; 376_Viimistlus_väljast: PULBERVÄRVITUD, TUMEHALL, RAL 7016; 310_Materjal: ALUMIINIUM; VIHMAVEE ÄRAVOOLUKS AKEN VARUSTADA TERASEST LISARAAMIGA, LEHTTERAS 5 MM, KALLE 5 KRAADI, TOON: TUMEHALL, RAL 7016. KUUMTSINGIKIHT VÄHEMALT 350 GR/M2. KINNITID PEAVAD OLEMA KORROSIOONIKINDLAD. AKENDE VT. JOONISEID AR-7-02 JA AR-8-82.; 300_Tüüp: A-09; 305_Ava_mõõt: 2 100x2 000; 315_Avanemine: PÖÖRDAVATAV, SISSEPOOLE, VASAK ; ARCHICAD tüüp: Fixed Glass; 320_Klaas: 3X KLAASPAKETT, PAKETI VAHELIISTU TOON: TUMEHALL, RAL 7016; 325_Helipidavus: AKNA HELIPIDAVUS 38 dB/ PAKETI HELIPIDAVUS 30 dB; 330_Tulekindlus: nõudeid ei esitata; 335_Välispiire: yes; 340_Soojusläbivus: 0.86; 345_Päikesekiirgus_tegur: g=0,55; VALGUSE LÄBIPAISTVUS 70%; 350_Klaaspakett: 6Sel+4+44.6Sel-18ChrU; 355_Pindala: 4.2 m2; 900_Tootja: SCHÜCO; 905_Mudel: AWS 90.SI+/ADS 90.SI; 910_Tooteinfo: LÄHTUDA TOOTJAFIRMA INFOLEHEST; 915_Kasutus-ja_hooldusjuhend: LÄHTUDA TOOTJAFIRMA INFOLEHEST
Pset_WindowCommon - Reference: A-09; ThermalTransmittance: 0; GlazingAreaFraction: 3.04763; IsExternal: yes
AC_Pset_RenovationAndPhasing - Renovation Status: New

# IfcWindow: Triple Window 24, A-10
In: Teine korrus
Type - OperationType: TRIPLE_PANEL_VERTICAL; ParameterTakesPrecedence: no; Sizeable: no
Type - Window Lining Properties - LiningDepth: 50 mm; LiningThickness: 90 mm; MullionThickness: 90 mm; FirstMullionOffset: 0.356349; SecondMullionOffset: 0.66746
Type - Window Panel Properties - Panel 1 - OperationType: FIXEDCASEMENT; PanelPosition: RIGHT
Type - Window Panel Properties - Panel 2 - OperationType: FIXEDCASEMENT; PanelPosition: MIDDLE
Type - Window Panel Properties - Panel 3 - OperationType: TILTANDTURNRIGHTHAND; PanelPosition: LEFT; FrameDepth: 50 mm; FrameThickness: 50 mm
OverallHeight: 2000 mm; OverallWidth: 2100 mm; Classification: 1.25 IfcWindowStyle (aken) (RKAS BIM + ARCHICAD Classification); 422 Alumiiniumaknad (V1- EHITUSKULUDE LIIGITAMINE EVS 885:2005)
Avatäited - 05 Asukoha info: Väline avatäide; 17 Sulused, lukustus: AVANEV OSA VARUSTADA FIKSAATORIGA, KÄEPIDE (ASSA RUKOLINE VÕI ANALOOG, LKUJULINE ÜMARATE KATETEGA LINK, HARJATUD, ROOSTEVABA, OTS SIRGE) HARJATUD, ROOSTEVABA); 09 Õhuläbilaskvus: KLASS 4 (EVS-EN 12207: 2016); 14 Päikesekiirgus tegur (g-väärtus): g=0,55; VALGUSE LÄBIPAISTVUS 70%; 18 Viimistlus: LENG JA RAAM VÄLJAST: PULBERVÄRVITUD, TUMEHALL, RAL 7016; LENG JA RAAM SEEST: PULBERVÄRVITUD, TOON: TUMEHALL, RAL 7016; 03 Tähistus: A-10
AR_Aken - 001_Nimetus: VÄLISAKEN; 310_Materjal: ALUMIINIUM; VIHMAVEE ÄRAVOOLUKS AKEN VARUSTADA TERASEST LISARAAMIGA, LEHTTERAS 5 MM, KALLE 5 KRAADI, TOON: TUMEHALL, RAL 7016. KUUMTSINGIKIHT VÄHEMALT 350 GR/M2. KINNITID PEAVAD OLEMA KORROSIOONIKINDLAD. AKENDE VT. JOONISEID AR-7-02 JA AR-8-82.; 375_Viimistlus_seest: PULBERVÄRVITUD, TUMEHALL, RAL 7016; 376_Viimistlus_väljast: PULBERVÄRVITUD, TUMEHALL, RAL 7016; 300_Tüüp: A-10; 305_Ava_mõõt: 2 100x2 000; 315_Avanemine: PÖÖRD- JA KALDAVATAV, SISSEPOOLE, VASAK ; ARCHICAD tüüp: Fixed Glass; 320_Klaas: 3X KLAASPAKETT, PAKETI VAHELIISTU TOON: TUMEHALL, RAL 7016; 325_Helipidavus: AKNA HELIPIDAVUS 38 dB/ PAKETI HELIPIDAVUS 30 dB; 330_Tulekindlus: nõudeid ei esitata; 335_Välispiire: yes; 340_Soojusläbivus: 0.8; 345_Päikesekiirgus_tegur: g=0,55; VALGUSE LÄBIPAISTVUS 70%; 350_Klaaspakett: 6 MM SELEKTIIV + 4 + 6 MM SELEKTIIV / 14mm ChrU; 355_Pindala: 4.2 m2; 900_Tootja: SCHÜCO; 905_Mudel: AWS 90.SI+/ADS 90.SI; 910_Tooteinfo: LÄHTUDA TOOTJAFIRMA INFOLEHEST; 915_Kasutus-ja_hooldusjuhend: LÄHTUDA TOOTJAFIRMA INFOLEHEST
Pset_WindowCommon - Reference: A-10; ThermalTransmittance: 0; GlazingAreaFraction: 3.04763; IsExternal: yes
AC_Pset_RenovationAndPhasing - Renovation Status: New

# IfcWindow: Window 24 (7)
In: Teine korrus
Type - OperationType: SINGLE_PANEL; ParameterTakesPrecedence: no; Sizeable: no
Type - Window Lining Properties - LiningDepth: 40 mm; LiningThickness: 32 mm
Type - Window Panel Properties - Panel 1 - OperationType: TILTANDTURNLEFTHAND; PanelPosition: MIDDLE; FrameDepth: 50 mm; FrameThickness: 50 mm
OverallHeight: 1500 mm; Classification: 1.25 IfcWindowStyle (aken) (RKAS BIM + ARCHICAD Classification); 518 Siseaknad (V1- EHITUSKULUDE LIIGITAMINE EVS 885:2005)
Avatäited - 03 Tähistus: A-03; 05 Asukoha info: Väline avatäide; 17 Sulused, lukustus: AVANEV OSA VARUSTADA FIKSAATORIGA, KÄEPIDE (ASSA RUKOLINE VÕI ANALOOG, LKUJULINE ÜMARATE KATETEGA LINK, HARJATUD, ROOSTEVABA, OTS SIRGE) HARJATUD, ROOSTEVABA)
Pset_WindowCommon - FireRating: EI-30/ Sa; AcousticRating: 30dB; ThermalTransmittance: 0
AR_Aken - 001_Nimetus: SISEAKEN; 310_Materjal: MUDELIS: väljast PULBERVÄRVITUD, TOON: HALL, RAL 7045; PULBERVÄRVITUD, TOON: HALL, RAL 7045; seest PULBERVÄRVITUD, TOON: HALL, RAL 7045; PULBERVÄRVITUD, TOON: HALL, RAL 7045; MÄRKUS: ALUMIINIUM; 320_Klaas: ÜHEKORDNE KLAASPAKETT; 325_Helipidavus: AKNA HELIPIDAVUS 38 dB/ PAKETI HELIPIDAVUS 30 dB; 330_Tulekindlus: EI30; 335_Välispiire: no; 340_Soojusläbivus: 0; 345_Päikesekiirgus_tegur: -; 350_Klaaspakett: KARASTATUD, LAMINEERITUD; 375_Viimistlus_seest: MUDELIS: PULBERVÄRVITUD, TOON: HALL, RAL 7045; PULBERVÄRVITUD, TOON: HALL, RAL 7045; MÄRKUS: RAAM JA JAOTISED: HALL, RAL 7045; 376_Viimistlus_väljast: MUDELIS: PULBERVÄRVITUD, TOON: HALL, RAL 7045; PULBERVÄRVITUD, TOON: HALL, RAL 7045; MÄRKUS: RAAM JA JAOTISED: HALL, RAL 7045; 905_Mudel: ADS 80 FR 30; 910_Tooteinfo: LÄHTUDA TOOTJAFIRMA INFOLEHELT; 915_Kasutus-ja_hooldusjuhend: LÄHTUDA TOOTJAFIRMA INFOLEHELT
Pset_FireRatingProperties - FireResistanceRating: EI-30/ Sa
Pset_ManufacturerTypeInformation - Manufacturer: MALMERK FASSAADID/ S32 VÕI ANALOOG
AC_Pset_RenovationAndPhasing - Renovation Status: New
Name | OverallWidth (mm) | Reference = 300_Tüüp | GlazingAreaFraction | 305_Ava_mõõt | 315_Avanemine | 355_Pindala (m2) | 900_Tootja
2 x SA-06 | 2594.78 | SA-06 | 3.35244 | 2 595x1 500 | MITTEAVATAV; ARCHICAD tüüp: Tilt-Turn | 3.89218 | SCHÜCO
2 x SA-05 | 2755 | SA-05 | 3.48856 | 2 755x1 500 | MITTEAVATAV ; ARCHICAD tüüp: Tilt-Turn | 4.1325 | -
3 x SA-03 | 2422.5 | SA-03 | 3.11365 | 2 423x1 500 | MITTEAVATAV ; ARCHICAD tüüp: Tilt-Turn | 3.63375 | -

# IfcWindow: Window 24 (6)
Type - OperationType: SINGLE_PANEL; ParameterTakesPrecedence: no; Sizeable: no
Type - Window Lining Properties - LiningDepth: 40 mm; LiningThickness: 32 mm
Type - Window Panel Properties - Panel 1 - OperationType: TILTANDTURNRIGHTHAND; PanelPosition: MIDDLE; FrameDepth: 50 mm; FrameThickness: 50 mm
OverallHeight: 1500 mm; Classification: 1.25 IfcWindowStyle (aken) (RKAS BIM + ARCHICAD Classification); 518 Siseaknad (V1- EHITUSKULUDE LIIGITAMINE EVS 885:2005)
Avatäited - 03 Tähistus: A-03; 05 Asukoha info: Väline avatäide; 17 Sulused, lukustus: AVANEV OSA VARUSTADA FIKSAATORIGA, KÄEPIDE (ASSA RUKOLINE VÕI ANALOOG, LKUJULINE ÜMARATE KATETEGA LINK, HARJATUD, ROOSTEVABA, OTS SIRGE) HARJATUD, ROOSTEVABA)
AR_Aken - 900_Tootja: -; 001_Nimetus: SISEAKEN; 310_Materjal: MUDELIS: väljast PULBERVÄRVITUD, TOON: HALL, RAL 7045; PULBERVÄRVITUD, TOON: HALL, RAL 7045; seest PULBERVÄRVITUD, TOON: HALL, RAL 7045; PULBERVÄRVITUD, TOON: HALL, RAL 7045; MÄRKUS: ALUMIINIUM; 315_Avanemine: MITTEAVATAV ; ARCHICAD tüüp: Tilt-Turn; 320_Klaas: ÜHEKORDNE KLAASPAKETT; 325_Helipidavus: AKNA HELIPIDAVUS 38 dB/ PAKETI HELIPIDAVUS 30 dB; 330_Tulekindlus: EI30; 335_Välispiire: no; 340_Soojusläbivus: 0; 345_Päikesekiirgus_tegur: -; 350_Klaaspakett: KARASTATUD, LAMINEERITUD; 375_Viimistlus_seest: MUDELIS: PULBERVÄRVITUD, TOON: HALL, RAL 7045; PULBERVÄRVITUD, TOON: HALL, RAL 7045; MÄRKUS: RAAM JA JAOTISED: HALL, RAL 7045; 376_Viimistlus_väljast: MUDELIS: PULBERVÄRVITUD, TOON: HALL, RAL 7045; PULBERVÄRVITUD, TOON: HALL, RAL 7045; MÄRKUS: RAAM JA JAOTISED: HALL, RAL 7045; 905_Mudel: ADS 80 FR 30; 910_Tooteinfo: LÄHTUDA TOOTJAFIRMA INFOLEHELT; 915_Kasutus-ja_hooldusjuhend: LÄHTUDA TOOTJAFIRMA INFOLEHELT
Pset_WindowCommon - FireRating: EI-30/ Sa; AcousticRating: 30dB; ThermalTransmittance: 0
Pset_FireRatingProperties - FireResistanceRating: EI-30/ Sa
Pset_ManufacturerTypeInformation - Manufacturer: MALMERK FASSAADID/ S32 VÕI ANALOOG
AC_Pset_RenovationAndPhasing - Renovation Status: New
Name | In | OverallWidth (mm) | 300_Tüüp = Reference | 305_Ava_mõõt | 355_Pindala (m2) | GlazingAreaFraction
2 x SA-04 | Esimene korrus | 2471.5 | SA-04 | 2 472x1 500 | 3.70725 | 3.18156
2 x SA-04 | Teine korrus | 2471.5 | SA-04 | 2 472x1 500 | 3.70725 | 3.18156
2 x SA-05 | Teine korrus | 2682.5 | SA-05 | 2 683x1 500 | 4.02375 | 3.38808

# IfcWindow: Window 24 (3)
Type - OperationType: SINGLE_PANEL; ParameterTakesPrecedence: no; Sizeable: no
Type - Window Lining Properties - LiningDepth: 50 mm; LiningThickness: 35 mm
Type - Window Panel Properties - Panel 1 - OperationType: FIXEDCASEMENT; PanelPosition: MIDDLE
OverallHeight: 2000 mm; OverallWidth: 1400 mm; Classification: 1.25 IfcWindowStyle (aken) (RKAS BIM + ARCHICAD Classification)
Pset_WindowCommon - Reference: VR-01; ThermalTransmittance: 0; IsExternal: yes
AR_Aken - 300_Tüüp: VR-01; 305_Ava_mõõt: 1 400x2 000; 320_Klaas: -; 325_Helipidavus: -; 330_Tulekindlus: nõudeid ei esitata; 335_Välispiire: yes; 340_Soojusläbivus: 0; 345_Päikesekiirgus_tegur: -; 350_Klaaspakett: -; 355_Pindala: 2.8 m2; 900_Tootja: -; 905_Mudel: -; 910_Tooteinfo: -; 915_Kasutus-ja_hooldusjuhend: -
AC_Pset_RenovationAndPhasing - Renovation Status: New
Name | In | 001_Nimetus | 310_Materjal | 315_Avanemine | 375_Viimistlus_seest = 376_Viimistlus_väljast
VR-01 | Esimene korrus | VÄLISAKEN | MUDELIS: väljast PULBERVÄRVITUD, TOON: TUMEHALL, RAL 7016; PULBERVÄRVITUD, TOON: TUMEHALL, RAL 7016; seest PULBERVÄRVITUD, TOON: TUMEHALL, RAL 7016; PULBERVÄRVITUD, TOON: TUMEHALL, RAL 7016; MÄRKUS: KUUMTSINGITUD TERAS | MITTEAVATAV ; ARCHICAD tüüp: Fixed Sash | MUDELIS: PULBERVÄRVITUD, TOON: TUMEHALL, RAL 7016; PULBERVÄRVITUD, TOON: TUMEHALL, RAL 7016; MÄRKUS: PULBERVÄRVITUD, TOON: TUMEHALL, RAL 7016 | Pset_WindowCommon - AcousticRating: 38dB
2 x VR-01 | Teine korrus | VENTILATSIOONIREST | KUUMTSINGITUD TERAS | MITTEAVATAV | PULBERVÄRVITUD, TOON: TUMEHALL, RAL 7016

# IfcWindow: Window 24 (3)
In: Teine korrus
Type - OperationType: SINGLE_PANEL; ParameterTakesPrecedence: no; Sizeable: no
Type - Window Lining Properties - LiningDepth: 50 mm; LiningThickness: 90 mm
Type - Window Panel Properties - Panel 1 - OperationType: FIXEDCASEMENT; PanelPosition: MIDDLE
OverallHeight: 2000 mm; OverallWidth: 700 mm; Classification: 1.25 IfcWindowStyle (aken) (RKAS BIM + ARCHICAD Classification); 422 Alumiiniumaknad (V1- EHITUSKULUDE LIIGITAMINE EVS 885:2005)
Avatäited - 03 Tähistus: A-03; 17 Sulused, lukustus: AVANEV OSA VARUSTADA FIKSAATORIGA, KÄEPIDE (ASSA RUKOLINE VÕI ANALOOG, LKUJULINE ÜMARATE KATETEGA LINK, HARJATUD, ROOSTEVABA, OTS SIRGE) HARJATUD, ROOSTEVABA); 09 Õhuläbilaskvus: KLASS 4 (EVS-EN 12207: 2016); 14 Päikesekiirgus tegur (g-väärtus): g=0,55; VALGUSE LÄBIPAISTVUS 70%; 18 Viimistlus: LENG JA RAAM VÄLJAST: PULBERVÄRVITUD, TUMEHALL, RAL 7016; LENG JA RAAM SEEST: PULBERVÄRVITUD, TOON: TUMEHALL, RAL 7016; 05 Asukoha info: VÄLISFASSAAD, 2. KORRUS
AR_Aken - 310_Materjal: ALUMIINIUM; VIHMAVEE ÄRAVOOLUKS AKEN VARUSTADA TERASEST LISARAAMIGA, LEHTTERAS 5 MM, KALLE 5 KRAADI, TOON: TUMEHALL, RAL 7016. KUUMTSINGIKIHT VÄHEMALT 350 GR/M2. KINNITID PEAVAD OLEMA KORROSIOONIKINDLAD. AKENDE VT. JOONISEID AR-7-02 JA AR-8-82.; 375_Viimistlus_seest: PULBERVÄRVITUD, TUMEHALL, RAL 7016; 376_Viimistlus_väljast: PULBERVÄRVITUD, TUMEHALL, RAL 7016; 001_Nimetus: VÄLISAKEN; 305_Ava_mõõt: 700x2 000; 315_Avanemine: MITTEAVATAV ; ARCHICAD tüüp: Fixed Glass; 320_Klaas: 3X KLAASPAKETT, PAKETI VAHELIISTU TOON: TUMEHALL, RAL 7016; 325_Helipidavus: AKNA HELIPIDAVUS 38 dB/ PAKETI HELIPIDAVUS 30 dB; 335_Välispiire: yes; 345_Päikesekiirgus_tegur: g=0,55; VALGUSE LÄBIPAISTVUS 70%; 355_Pindala: 1.4 m2; 900_Tootja: SCHÜCO; 905_Mudel: AWS 90.SI VÕI SAMAVÄÄRNE ANALOOG; 910_Tooteinfo: LÄHTUDA TOOTJAFIRMA INFOLEHEST; 915_Kasutus-ja_hooldusjuhend: LÄHTUDA TOOTJAFIRMA INFOLEHEST
Pset_WindowCommon - FireRating: EI-30/Sa; AcousticRating: 38dB/ 30 dB; ThermalTransmittance: 0; GlazingAreaFraction: 0.9464; IsExternal: yes
Pset_FireRatingProperties - FireResistanceRating: EI-30/Sa
Pset_ManufacturerTypeInformation - Manufacturer: SCHÜCO/ AWS 90.SI VÕI SAMAVÄÄRNE ANALOOG
AC_Pset_RenovationAndPhasing - Renovation Status: New
Name | 10 Tulekindlus = 330_Tulekindlus | 300_Tüüp = Reference | 340_Soojusläbivus | 350_Klaaspakett
A-03 | nõudeid ei esitata | A-03 | 0.88 | 6 MM SELEKTIIV + 4 + 6 MM SELEKTIIV / 14mm ChrU
2 x A-02* | EI30 | A-02* | 2 | 4 + 6 MM SELEKTIIV / 14mm ChrU

# IfcWindow: Window 24 (5)
In: Esimene korrus
Type - OperationType: SINGLE_PANEL; ParameterTakesPrecedence: no; Sizeable: no
Type - Window Lining Properties - LiningDepth: 50 mm; LiningThickness: 90 mm
Type - Window Panel Properties - Panel 1 - OperationType: SIDEHUNGLEFTHAND; PanelPosition: MIDDLE; FrameDepth: 50 mm; FrameThickness: 50 mm
OverallHeight: 2000 mm; OverallWidth: 700 mm; Classification: 1.25 IfcWindowStyle (aken) (RKAS BIM + ARCHICAD Classification); 422 Alumiiniumaknad (V1- EHITUSKULUDE LIIGITAMINE EVS 885:2005)
Avatäited - 11 Vastupanu tulekoormusele: KLASS C3 (EVS-EN 12210: 2016); 03 Tähistus: A-03; 17 Sulused, lukustus: AVANEV OSA VARUSTADA FIKSAATORIGA, KÄEPIDE (ASSA RUKOLINE VÕI ANALOOG, LKUJULINE ÜMARATE KATETEGA LINK, HARJATUD, ROOSTEVABA, OTS SIRGE) HARJATUD, ROOSTEVABA); 14 Päikesekiirgus tegur (g-väärtus): VALGUSE LÄBIPAISTVUS 63%; 09 Õhuläbilaskvus: KLASS 4 (EVS-EN 12207: 2016); 05 Asukoha info: VÄLISFASSAAD, 1. KORRUS; 18 Viimistlus: LENG JA RAAM VÄLJAST: PULBERVÄRVITUD, TUMEHALL, RAL 7016; LENG JA RAAM SEEST: PULBERVÄRVITUD, TOON: TUMEHALL, RAL 7016; 12 Klaaspakett: 3X KLAASPAKETT, 6MM SELEKTIIV + 4 + 44.6 (P5A) LAMINEERITUD SELEKTIIV / 14MM CHRU, PAKETI VAHELIISTU TOON: TUMEHALL, RAL 7016
AR_Aken - 900_Tootja: SCHÜCO; 001_Nimetus: VÄLISAKEN; 340_Soojusläbivus: 0.8; 320_Klaas: 6Sel+4+44.6Sel-18ChrU; 350_Klaaspakett: 3X KLAASPAKETT, PAKETI VAHELIISTU TOON: TUMEHALL, RAL 7016; 905_Mudel: AWS 90.SI VÕI SAMAVÄÄRNE ANALOOG; 375_Viimistlus_seest: PULBERVÄRVITUD, TUMEHALL, RAL 7016; 376_Viimistlus_väljast: PULBERVÄRVITUD, TUMEHALL, RAL 7016; 310_Materjal: ALUMIINIUM; VIHMAVEE ÄRAVOOLUKS AKEN VARUSTADA TERASEST LISARAAMIGA, LEHTTERAS 5 MM, KALLE 5 KRAADI, TOON: TUMEHALL, RAL 7016. KUUMTSINGIKIHT VÄHEMALT 350 GR/M2. KINNITID PEAVAD OLEMA KORROSIOONIKINDLAD. AKENDE VT. JOONISEID AR-7-02 JA AR-8-82.; 300_Tüüp: A-01; 305_Ava_mõõt: 700x2 000; 315_Avanemine: MITTEAVATAV ; ARCHICAD tüüp: Side Hung Mirrored; 325_Helipidavus: AKNA HELIPIDAVUS 38 dB/ PAKETI HELIPIDAVUS 30 dB; 330_Tulekindlus: nõudeid ei esitata; 335_Välispiire: yes; 345_Päikesekiirgus_tegur: g=0,55; VALGUSE LÄBIPAISTVUS 70%; 355_Pindala: 1.4 m2; 910_Tooteinfo: LÄHTUDA TOOTJAFIRMA INFOLEHEST; 915_Kasutus-ja_hooldusjuhend: LÄHTUDA TOOTJAFIRMA INFOLEHEST
Pset_ManufacturerTypeInformation - Manufacturer: AWS 90.SI VÕI SAMAVÄÄRNE ANALOOG
Pset_WindowCommon - Reference: A-01; AcousticRating: 38dB/ 30 dB; ThermalTransmittance: 0; GlazingAreaFraction: 0.8319; IsExternal: yes
AC_Pset_RenovationAndPhasing - Renovation Status: New

# IfcWindow: Window 24 (6)
In: Teine korrus
Type - OperationType: SINGLE_PANEL; ParameterTakesPrecedence: no; Sizeable: no
Type - Window Lining Properties - LiningDepth: 50 mm; LiningThickness: 90 mm
Type - Window Panel Properties - Panel 1 - OperationType: TILTANDTURNLEFTHAND; PanelPosition: MIDDLE; FrameDepth: 50 mm; FrameThickness: 50 mm
OverallHeight: 2000 mm; OverallWidth: 700 mm; Classification: 1.25 IfcWindowStyle (aken) (RKAS BIM + ARCHICAD Classification); 422 Alumiiniumaknad (V1- EHITUSKULUDE LIIGITAMINE EVS 885:2005)
Avatäited - 10 Tulekindlus: nõudeid ei esitata; 11 Vastupanu tulekoormusele: KLASS C3 (EVS-EN 12210: 2016); 03 Tähistus: A-03; 05 Asukoha info: Väline avatäide; 17 Sulused, lukustus: AVANEV OSA VARUSTADA FIKSAATORIGA, KÄEPIDE (ASSA RUKOLINE VÕI ANALOOG, LKUJULINE ÜMARATE KATETEGA LINK, HARJATUD, ROOSTEVABA, OTS SIRGE) HARJATUD, ROOSTEVABA); 09 Õhuläbilaskvus: KLASS 4 (EVS-EN 12207: 2016); 14 Päikesekiirgus tegur (g-väärtus): g=0,55; VALGUSE LÄBIPAISTVUS 70%; 18 Viimistlus: LENG JA RAAM VÄLJAST: PULBERVÄRVITUD, TUMEHALL, RAL 7016; LENG JA RAAM SEEST: PULBERVÄRVITUD, TOON: TUMEHALL, RAL 7016
AR_Aken - 310_Materjal: ALUMIINIUM; VIHMAVEE ÄRAVOOLUKS AKEN VARUSTADA TERASEST LISARAAMIGA, LEHTTERAS 5 MM, KALLE 5 KRAADI, TOON: TUMEHALL, RAL 7016. KUUMTSINGIKIHT VÄHEMALT 350 GR/M2. KINNITID PEAVAD OLEMA KORROSIOONIKINDLAD. AKENDE VT. JOONISEID AR-7-02 JA AR-8-82.; 375_Viimistlus_seest: PULBERVÄRVITUD, TUMEHALL, RAL 7016; 376_Viimistlus_väljast: PULBERVÄRVITUD, TUMEHALL, RAL 7016; 001_Nimetus: VÄLISAKEN; 300_Tüüp: A-04; 305_Ava_mõõt: 700x2 000; 315_Avanemine: PÖÖRD- JA KALDAVATAV, SISSEPOOLE, VASAK - Vasak ; ARCHICAD tüüp: Tilt-Turn; 320_Klaas: 3X KLAASPAKETT, PAKETI VAHELIISTU TOON: TUMEHALL, RAL 7016; 325_Helipidavus: AKNA HELIPIDAVUS 38 dB/ PAKETI HELIPIDAVUS 30 dB; 330_Tulekindlus: nõudeid ei esitata; 335_Välispiire: yes; 340_Soojusläbivus: 0.88; 345_Päikesekiirgus_tegur: g=0,55; VALGUSE LÄBIPAISTVUS 70%; 350_Klaaspakett: 6 MM SELEKTIIV + 4 + 6 MM SELEKTIIV / 14mm ChrU; 355_Pindala: 1.4 m2; 900_Tootja: SCHÜCO; 905_Mudel: AWS 90.SI+/ADS 90.SI; 910_Tooteinfo: LÄHTUDA TOOTJAFIRMA INFOLEHEST; 915_Kasutus-ja_hooldusjuhend: LÄHTUDA TOOTJAFIRMA INFOLEHEST
Pset_WindowCommon - Reference: A-04; AcousticRating: 38dB/ 30 dB; ThermalTransmittance: 0; GlazingAreaFraction: 0.8319; IsExternal: yes
Pset_ManufacturerTypeInformation - Manufacturer: SCHÜCO/ AWS 90.SI VÕI SAMAVÄÄRNE ANALOOG
AC_Pset_RenovationAndPhasing - Renovation Status: New
